VERSION 5.8 ;
BUSBITCHARS "[]" ;
DIVIDERCHAR "/" ;
UNITS
    DATABASE MICRONS 1000 ;
END UNITS

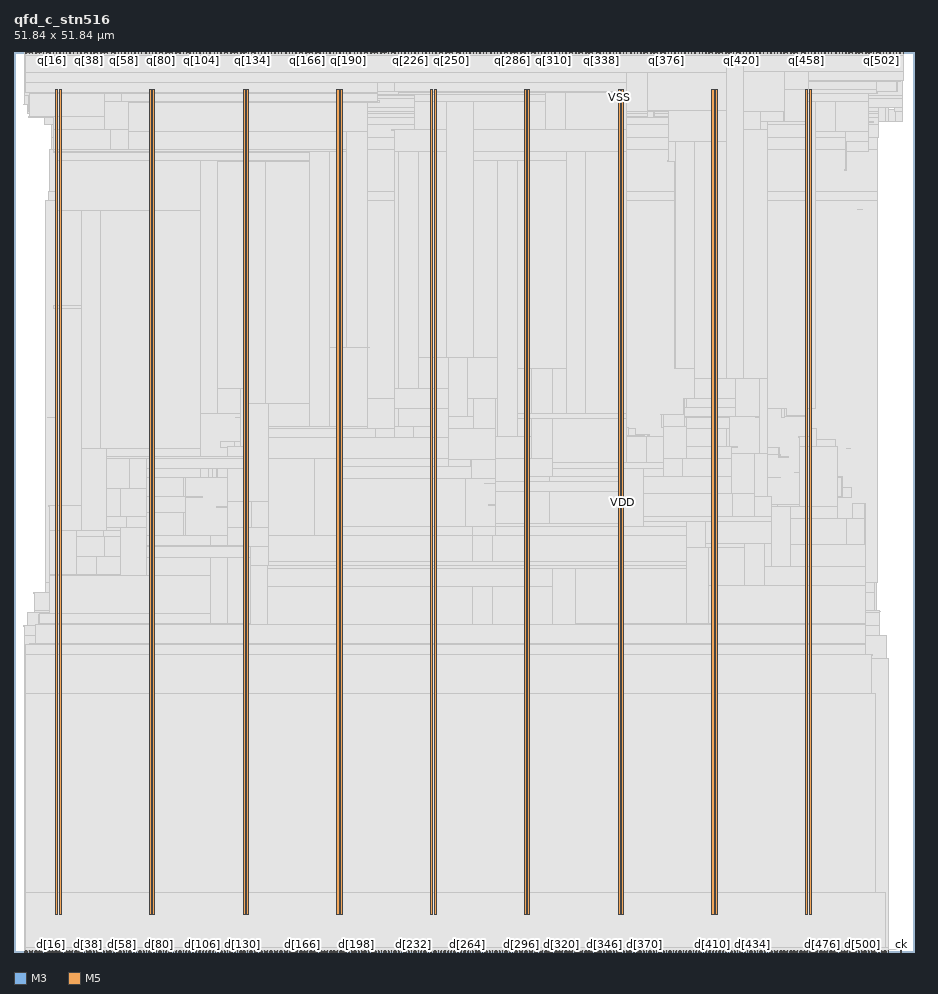
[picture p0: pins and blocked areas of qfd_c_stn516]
MACRO qfd_c_stn516
  FOREIGN qfd_c_stn516 0 0 ;
  CLASS BLOCK ;
  SIZE 51.84 BY 51.84 ;
  PIN ck
    DIRECTION INPUT ;
    USE SIGNAL ;
    PORT
      LAYER M3 ;
        RECT  51.084 0 51.102 0.038 ;
    END
    PORT
      LAYER M3 ;
        RECT  51.084 0.012 51.102 0.173 ;
    END
  END ck
  PIN d[0]
    DIRECTION INPUT ;
    USE SIGNAL ;
    PORT
      LAYER M3 ;
        RECT  0.576 0 0.594 0.038 ;
    END
  END d[0]
  PIN d[100]
    DIRECTION INPUT ;
    USE SIGNAL ;
    PORT
      LAYER M3 ;
        RECT  10.26 0 10.278 0.038 ;
    END
  END d[100]
  PIN d[101]
    DIRECTION INPUT ;
    USE SIGNAL ;
    PORT
      LAYER M5 ;
        RECT  10.32 0 10.344 0.084 ;
    END
  END d[101]
  PIN d[102]
    DIRECTION INPUT ;
    USE SIGNAL ;
    PORT
      LAYER M3 ;
        RECT  10.44 0 10.458 0.038 ;
    END
  END d[102]
  PIN d[103]
    DIRECTION INPUT ;
    USE SIGNAL ;
    PORT
      LAYER M5 ;
        RECT  10.512 0 10.536 0.084 ;
    END
  END d[103]
  PIN d[104]
    DIRECTION INPUT ;
    USE SIGNAL ;
    PORT
      LAYER M3 ;
        RECT  10.62 0 10.638 0.038 ;
    END
  END d[104]
  PIN d[105]
    DIRECTION INPUT ;
    USE SIGNAL ;
    PORT
      LAYER M5 ;
        RECT  10.704 0 10.728 0.084 ;
    END
  END d[105]
  PIN d[106]
    DIRECTION INPUT ;
    USE SIGNAL ;
    PORT
      LAYER M3 ;
        RECT  10.836 0 10.854 0.038 ;
    END
  END d[106]
  PIN d[107]
    DIRECTION INPUT ;
    USE SIGNAL ;
    PORT
      LAYER M5 ;
        RECT  10.896 0 10.92 0.084 ;
    END
  END d[107]
  PIN d[108]
    DIRECTION INPUT ;
    USE SIGNAL ;
    PORT
      LAYER M3 ;
        RECT  11.016 0 11.034 0.038 ;
    END
  END d[108]
  PIN d[109]
    DIRECTION INPUT ;
    USE SIGNAL ;
    PORT
      LAYER M5 ;
        RECT  11.088 0 11.112 0.084 ;
    END
  END d[109]
  PIN d[10]
    DIRECTION INPUT ;
    USE SIGNAL ;
    PORT
      LAYER M3 ;
        RECT  1.548 0 1.566 0.038 ;
    END
  END d[10]
  PIN d[110]
    DIRECTION INPUT ;
    USE SIGNAL ;
    PORT
      LAYER M3 ;
        RECT  11.196 0 11.214 0.038 ;
    END
  END d[110]
  PIN d[111]
    DIRECTION INPUT ;
    USE SIGNAL ;
    PORT
      LAYER M5 ;
        RECT  11.28 0 11.304 0.084 ;
    END
  END d[111]
  PIN d[112]
    DIRECTION INPUT ;
    USE SIGNAL ;
    PORT
      LAYER M3 ;
        RECT  11.412 0 11.43 0.038 ;
    END
  END d[112]
  PIN d[113]
    DIRECTION INPUT ;
    USE SIGNAL ;
    PORT
      LAYER M5 ;
        RECT  11.472 0 11.496 0.084 ;
    END
  END d[113]
  PIN d[114]
    DIRECTION INPUT ;
    USE SIGNAL ;
    PORT
      LAYER M3 ;
        RECT  11.592 0 11.61 0.038 ;
    END
  END d[114]
  PIN d[115]
    DIRECTION INPUT ;
    USE SIGNAL ;
    PORT
      LAYER M5 ;
        RECT  11.712 0 11.736 0.084 ;
    END
  END d[115]
  PIN d[116]
    DIRECTION INPUT ;
    USE SIGNAL ;
    PORT
      LAYER M3 ;
        RECT  11.772 0 11.79 0.038 ;
    END
  END d[116]
  PIN d[117]
    DIRECTION INPUT ;
    USE SIGNAL ;
    PORT
      LAYER M5 ;
        RECT  11.904 0 11.928 0.084 ;
    END
  END d[117]
  PIN d[118]
    DIRECTION INPUT ;
    USE SIGNAL ;
    PORT
      LAYER M3 ;
        RECT  11.988 0 12.006 0.038 ;
    END
  END d[118]
  PIN d[119]
    DIRECTION INPUT ;
    USE SIGNAL ;
    PORT
      LAYER M5 ;
        RECT  12.096 0 12.12 0.084 ;
    END
  END d[119]
  PIN d[11]
    DIRECTION INPUT ;
    USE SIGNAL ;
    PORT
      LAYER M5 ;
        RECT  1.632 0 1.656 0.084 ;
    END
  END d[11]
  PIN d[120]
    DIRECTION INPUT ;
    USE SIGNAL ;
    PORT
      LAYER M3 ;
        RECT  12.168 0 12.186 0.038 ;
    END
  END d[120]
  PIN d[121]
    DIRECTION INPUT ;
    USE SIGNAL ;
    PORT
      LAYER M5 ;
        RECT  12.288 0 12.312 0.084 ;
    END
  END d[121]
  PIN d[122]
    DIRECTION INPUT ;
    USE SIGNAL ;
    PORT
      LAYER M3 ;
        RECT  12.384 0 12.402 0.038 ;
    END
  END d[122]
  PIN d[123]
    DIRECTION INPUT ;
    USE SIGNAL ;
    PORT
      LAYER M5 ;
        RECT  12.48 0 12.504 0.084 ;
    END
  END d[123]
  PIN d[124]
    DIRECTION INPUT ;
    USE SIGNAL ;
    PORT
      LAYER M3 ;
        RECT  12.564 0 12.582 0.038 ;
    END
  END d[124]
  PIN d[125]
    DIRECTION INPUT ;
    USE SIGNAL ;
    PORT
      LAYER M5 ;
        RECT  12.672 0 12.696 0.084 ;
    END
  END d[125]
  PIN d[126]
    DIRECTION INPUT ;
    USE SIGNAL ;
    PORT
      LAYER M3 ;
        RECT  12.744 0 12.762 0.038 ;
    END
  END d[126]
  PIN d[127]
    DIRECTION INPUT ;
    USE SIGNAL ;
    PORT
      LAYER M5 ;
        RECT  12.864 0 12.888 0.084 ;
    END
  END d[127]
  PIN d[128]
    DIRECTION INPUT ;
    USE SIGNAL ;
    PORT
      LAYER M3 ;
        RECT  12.96 0 12.978 0.038 ;
    END
  END d[128]
  PIN d[129]
    DIRECTION INPUT ;
    USE SIGNAL ;
    PORT
      LAYER M5 ;
        RECT  13.056 0 13.08 0.084 ;
    END
  END d[129]
  PIN d[12]
    DIRECTION INPUT ;
    USE SIGNAL ;
    PORT
      LAYER M3 ;
        RECT  1.728 0 1.746 0.038 ;
    END
  END d[12]
  PIN d[130]
    DIRECTION INPUT ;
    USE SIGNAL ;
    PORT
      LAYER M3 ;
        RECT  13.14 0 13.158 0.038 ;
    END
  END d[130]
  PIN d[131]
    DIRECTION INPUT ;
    USE SIGNAL ;
    PORT
      LAYER M5 ;
        RECT  13.248 0 13.272 0.084 ;
    END
  END d[131]
  PIN d[132]
    DIRECTION INPUT ;
    USE SIGNAL ;
    PORT
      LAYER M3 ;
        RECT  13.32 0 13.338 0.038 ;
    END
  END d[132]
  PIN d[133]
    DIRECTION INPUT ;
    USE SIGNAL ;
    PORT
      LAYER M5 ;
        RECT  13.44 0 13.464 0.084 ;
    END
  END d[133]
  PIN d[134]
    DIRECTION INPUT ;
    USE SIGNAL ;
    PORT
      LAYER M3 ;
        RECT  13.536 0 13.554 0.038 ;
    END
  END d[134]
  PIN d[135]
    DIRECTION INPUT ;
    USE SIGNAL ;
    PORT
      LAYER M5 ;
        RECT  13.632 0 13.656 0.084 ;
    END
  END d[135]
  PIN d[136]
    DIRECTION INPUT ;
    USE SIGNAL ;
    PORT
      LAYER M3 ;
        RECT  13.716 0 13.734 0.038 ;
    END
  END d[136]
  PIN d[137]
    DIRECTION INPUT ;
    USE SIGNAL ;
    PORT
      LAYER M5 ;
        RECT  13.824 0 13.848 0.084 ;
    END
  END d[137]
  PIN d[138]
    DIRECTION INPUT ;
    USE SIGNAL ;
    PORT
      LAYER M3 ;
        RECT  13.932 0 13.95 0.038 ;
    END
  END d[138]
  PIN d[139]
    DIRECTION INPUT ;
    USE SIGNAL ;
    PORT
      LAYER M5 ;
        RECT  14.016 0 14.04 0.084 ;
    END
  END d[139]
  PIN d[13]
    DIRECTION INPUT ;
    USE SIGNAL ;
    PORT
      LAYER M5 ;
        RECT  1.824 0 1.848 0.084 ;
    END
  END d[13]
  PIN d[140]
    DIRECTION INPUT ;
    USE SIGNAL ;
    PORT
      LAYER M3 ;
        RECT  14.112 0 14.13 0.038 ;
    END
  END d[140]
  PIN d[141]
    DIRECTION INPUT ;
    USE SIGNAL ;
    PORT
      LAYER M5 ;
        RECT  14.208 0 14.232 0.084 ;
    END
  END d[141]
  PIN d[142]
    DIRECTION INPUT ;
    USE SIGNAL ;
    PORT
      LAYER M3 ;
        RECT  14.292 0 14.31 0.038 ;
    END
  END d[142]
  PIN d[143]
    DIRECTION INPUT ;
    USE SIGNAL ;
    PORT
      LAYER M5 ;
        RECT  14.4 0 14.424 0.084 ;
    END
  END d[143]
  PIN d[144]
    DIRECTION INPUT ;
    USE SIGNAL ;
    PORT
      LAYER M3 ;
        RECT  14.508 0 14.526 0.038 ;
    END
  END d[144]
  PIN d[145]
    DIRECTION INPUT ;
    USE SIGNAL ;
    PORT
      LAYER M5 ;
        RECT  14.592 0 14.616 0.084 ;
    END
  END d[145]
  PIN d[146]
    DIRECTION INPUT ;
    USE SIGNAL ;
    PORT
      LAYER M3 ;
        RECT  14.688 0 14.706 0.038 ;
    END
  END d[146]
  PIN d[147]
    DIRECTION INPUT ;
    USE SIGNAL ;
    PORT
      LAYER M5 ;
        RECT  14.784 0 14.808 0.084 ;
    END
  END d[147]
  PIN d[148]
    DIRECTION INPUT ;
    USE SIGNAL ;
    PORT
      LAYER M3 ;
        RECT  14.868 0 14.886 0.038 ;
    END
  END d[148]
  PIN d[149]
    DIRECTION INPUT ;
    USE SIGNAL ;
    PORT
      LAYER M5 ;
        RECT  14.976 0 15 0.084 ;
    END
  END d[149]
  PIN d[14]
    DIRECTION INPUT ;
    USE SIGNAL ;
    PORT
      LAYER M3 ;
        RECT  1.944 0 1.962 0.038 ;
    END
  END d[14]
  PIN d[150]
    DIRECTION INPUT ;
    USE SIGNAL ;
    PORT
      LAYER M3 ;
        RECT  15.084 0 15.102 0.038 ;
    END
  END d[150]
  PIN d[151]
    DIRECTION INPUT ;
    USE SIGNAL ;
    PORT
      LAYER M5 ;
        RECT  15.168 0 15.192 0.084 ;
    END
  END d[151]
  PIN d[152]
    DIRECTION INPUT ;
    USE SIGNAL ;
    PORT
      LAYER M3 ;
        RECT  15.264 0 15.282 0.038 ;
    END
  END d[152]
  PIN d[153]
    DIRECTION INPUT ;
    USE SIGNAL ;
    PORT
      LAYER M5 ;
        RECT  15.36 0 15.384 0.084 ;
    END
  END d[153]
  PIN d[154]
    DIRECTION INPUT ;
    USE SIGNAL ;
    PORT
      LAYER M3 ;
        RECT  15.444 0 15.462 0.038 ;
    END
  END d[154]
  PIN d[155]
    DIRECTION INPUT ;
    USE SIGNAL ;
    PORT
      LAYER M5 ;
        RECT  15.552 0 15.576 0.084 ;
    END
  END d[155]
  PIN d[156]
    DIRECTION INPUT ;
    USE SIGNAL ;
    PORT
      LAYER M3 ;
        RECT  15.66 0 15.678 0.038 ;
    END
  END d[156]
  PIN d[157]
    DIRECTION INPUT ;
    USE SIGNAL ;
    PORT
      LAYER M5 ;
        RECT  15.744 0 15.768 0.084 ;
    END
  END d[157]
  PIN d[158]
    DIRECTION INPUT ;
    USE SIGNAL ;
    PORT
      LAYER M3 ;
        RECT  15.84 0 15.858 0.038 ;
    END
  END d[158]
  PIN d[159]
    DIRECTION INPUT ;
    USE SIGNAL ;
    PORT
      LAYER M5 ;
        RECT  15.936 0 15.96 0.084 ;
    END
  END d[159]
  PIN d[15]
    DIRECTION INPUT ;
    USE SIGNAL ;
    PORT
      LAYER M5 ;
        RECT  2.016 0 2.04 0.084 ;
    END
  END d[15]
  PIN d[160]
    DIRECTION INPUT ;
    USE SIGNAL ;
    PORT
      LAYER M3 ;
        RECT  16.056 0 16.074 0.038 ;
    END
  END d[160]
  PIN d[161]
    DIRECTION INPUT ;
    USE SIGNAL ;
    PORT
      LAYER M5 ;
        RECT  16.128 0 16.152 0.084 ;
    END
  END d[161]
  PIN d[162]
    DIRECTION INPUT ;
    USE SIGNAL ;
    PORT
      LAYER M3 ;
        RECT  16.236 0 16.254 0.038 ;
    END
  END d[162]
  PIN d[163]
    DIRECTION INPUT ;
    USE SIGNAL ;
    PORT
      LAYER M5 ;
        RECT  16.32 0 16.344 0.084 ;
    END
  END d[163]
  PIN d[164]
    DIRECTION INPUT ;
    USE SIGNAL ;
    PORT
      LAYER M3 ;
        RECT  16.416 0 16.434 0.038 ;
    END
  END d[164]
  PIN d[165]
    DIRECTION INPUT ;
    USE SIGNAL ;
    PORT
      LAYER M5 ;
        RECT  16.512 0 16.536 0.084 ;
    END
  END d[165]
  PIN d[166]
    DIRECTION INPUT ;
    USE SIGNAL ;
    PORT
      LAYER M3 ;
        RECT  16.632 0 16.65 0.038 ;
    END
  END d[166]
  PIN d[167]
    DIRECTION INPUT ;
    USE SIGNAL ;
    PORT
      LAYER M5 ;
        RECT  16.704 0 16.728 0.084 ;
    END
  END d[167]
  PIN d[168]
    DIRECTION INPUT ;
    USE SIGNAL ;
    PORT
      LAYER M3 ;
        RECT  16.812 0 16.83 0.038 ;
    END
  END d[168]
  PIN d[169]
    DIRECTION INPUT ;
    USE SIGNAL ;
    PORT
      LAYER M5 ;
        RECT  16.896 0 16.92 0.084 ;
    END
  END d[169]
  PIN d[16]
    DIRECTION INPUT ;
    USE SIGNAL ;
    PORT
      LAYER M3 ;
        RECT  2.124 0 2.142 0.038 ;
    END
  END d[16]
  PIN d[170]
    DIRECTION INPUT ;
    USE SIGNAL ;
    PORT
      LAYER M3 ;
        RECT  16.992 0 17.01 0.038 ;
    END
  END d[170]
  PIN d[171]
    DIRECTION INPUT ;
    USE SIGNAL ;
    PORT
      LAYER M5 ;
        RECT  17.088 0 17.112 0.084 ;
    END
  END d[171]
  PIN d[172]
    DIRECTION INPUT ;
    USE SIGNAL ;
    PORT
      LAYER M3 ;
        RECT  17.208 0 17.226 0.038 ;
    END
  END d[172]
  PIN d[173]
    DIRECTION INPUT ;
    USE SIGNAL ;
    PORT
      LAYER M5 ;
        RECT  17.28 0 17.304 0.084 ;
    END
  END d[173]
  PIN d[174]
    DIRECTION INPUT ;
    USE SIGNAL ;
    PORT
      LAYER M3 ;
        RECT  17.388 0 17.406 0.038 ;
    END
  END d[174]
  PIN d[175]
    DIRECTION INPUT ;
    USE SIGNAL ;
    PORT
      LAYER M5 ;
        RECT  17.472 0 17.496 0.084 ;
    END
  END d[175]
  PIN d[176]
    DIRECTION INPUT ;
    USE SIGNAL ;
    PORT
      LAYER M3 ;
        RECT  17.604 0 17.622 0.038 ;
    END
  END d[176]
  PIN d[177]
    DIRECTION INPUT ;
    USE SIGNAL ;
    PORT
      LAYER M5 ;
        RECT  17.664 0 17.688 0.084 ;
    END
  END d[177]
  PIN d[178]
    DIRECTION INPUT ;
    USE SIGNAL ;
    PORT
      LAYER M3 ;
        RECT  17.784 0 17.802 0.038 ;
    END
  END d[178]
  PIN d[179]
    DIRECTION INPUT ;
    USE SIGNAL ;
    PORT
      LAYER M5 ;
        RECT  17.856 0 17.88 0.084 ;
    END
  END d[179]
  PIN d[17]
    DIRECTION INPUT ;
    USE SIGNAL ;
    PORT
      LAYER M5 ;
        RECT  2.208 0 2.232 0.084 ;
    END
  END d[17]
  PIN d[180]
    DIRECTION INPUT ;
    USE SIGNAL ;
    PORT
      LAYER M3 ;
        RECT  17.964 0 17.982 0.038 ;
    END
  END d[180]
  PIN d[181]
    DIRECTION INPUT ;
    USE SIGNAL ;
    PORT
      LAYER M5 ;
        RECT  18.048 0 18.072 0.084 ;
    END
  END d[181]
  PIN d[182]
    DIRECTION INPUT ;
    USE SIGNAL ;
    PORT
      LAYER M3 ;
        RECT  18.18 0 18.198 0.038 ;
    END
  END d[182]
  PIN d[183]
    DIRECTION INPUT ;
    USE SIGNAL ;
    PORT
      LAYER M5 ;
        RECT  18.24 0 18.264 0.084 ;
    END
  END d[183]
  PIN d[184]
    DIRECTION INPUT ;
    USE SIGNAL ;
    PORT
      LAYER M3 ;
        RECT  18.36 0 18.378 0.038 ;
    END
  END d[184]
  PIN d[185]
    DIRECTION INPUT ;
    USE SIGNAL ;
    PORT
      LAYER M5 ;
        RECT  18.432 0 18.456 0.084 ;
    END
  END d[185]
  PIN d[186]
    DIRECTION INPUT ;
    USE SIGNAL ;
    PORT
      LAYER M3 ;
        RECT  18.54 0 18.558 0.038 ;
    END
  END d[186]
  PIN d[187]
    DIRECTION INPUT ;
    USE SIGNAL ;
    PORT
      LAYER M5 ;
        RECT  18.624 0 18.648 0.084 ;
    END
  END d[187]
  PIN d[188]
    DIRECTION INPUT ;
    USE SIGNAL ;
    PORT
      LAYER M3 ;
        RECT  18.756 0 18.774 0.038 ;
    END
  END d[188]
  PIN d[189]
    DIRECTION INPUT ;
    USE SIGNAL ;
    PORT
      LAYER M5 ;
        RECT  18.816 0 18.84 0.084 ;
    END
  END d[189]
  PIN d[18]
    DIRECTION INPUT ;
    USE SIGNAL ;
    PORT
      LAYER M3 ;
        RECT  2.304 0 2.322 0.038 ;
    END
  END d[18]
  PIN d[190]
    DIRECTION INPUT ;
    USE SIGNAL ;
    PORT
      LAYER M3 ;
        RECT  18.936 0 18.954 0.038 ;
    END
  END d[190]
  PIN d[191]
    DIRECTION INPUT ;
    USE SIGNAL ;
    PORT
      LAYER M5 ;
        RECT  19.056 0 19.08 0.084 ;
    END
  END d[191]
  PIN d[192]
    DIRECTION INPUT ;
    USE SIGNAL ;
    PORT
      LAYER M3 ;
        RECT  19.116 0 19.134 0.038 ;
    END
  END d[192]
  PIN d[193]
    DIRECTION INPUT ;
    USE SIGNAL ;
    PORT
      LAYER M5 ;
        RECT  19.248 0 19.272 0.084 ;
    END
  END d[193]
  PIN d[194]
    DIRECTION INPUT ;
    USE SIGNAL ;
    PORT
      LAYER M3 ;
        RECT  19.332 0 19.35 0.038 ;
    END
  END d[194]
  PIN d[195]
    DIRECTION INPUT ;
    USE SIGNAL ;
    PORT
      LAYER M5 ;
        RECT  19.44 0 19.464 0.084 ;
    END
  END d[195]
  PIN d[196]
    DIRECTION INPUT ;
    USE SIGNAL ;
    PORT
      LAYER M3 ;
        RECT  19.512 0 19.53 0.038 ;
    END
  END d[196]
  PIN d[197]
    DIRECTION INPUT ;
    USE SIGNAL ;
    PORT
      LAYER M5 ;
        RECT  19.632 0 19.656 0.084 ;
    END
  END d[197]
  PIN d[198]
    DIRECTION INPUT ;
    USE SIGNAL ;
    PORT
      LAYER M3 ;
        RECT  19.728 0 19.746 0.038 ;
    END
  END d[198]
  PIN d[199]
    DIRECTION INPUT ;
    USE SIGNAL ;
    PORT
      LAYER M5 ;
        RECT  19.824 0 19.848 0.084 ;
    END
  END d[199]
  PIN d[19]
    DIRECTION INPUT ;
    USE SIGNAL ;
    PORT
      LAYER M5 ;
        RECT  2.4 0 2.424 0.084 ;
    END
  END d[19]
  PIN d[1]
    DIRECTION INPUT ;
    USE SIGNAL ;
    PORT
      LAYER M5 ;
        RECT  0.672 0 0.696 0.084 ;
    END
  END d[1]
  PIN d[200]
    DIRECTION INPUT ;
    USE SIGNAL ;
    PORT
      LAYER M3 ;
        RECT  19.908 0 19.926 0.038 ;
    END
  END d[200]
  PIN d[201]
    DIRECTION INPUT ;
    USE SIGNAL ;
    PORT
      LAYER M5 ;
        RECT  20.016 0 20.04 0.084 ;
    END
  END d[201]
  PIN d[202]
    DIRECTION INPUT ;
    USE SIGNAL ;
    PORT
      LAYER M3 ;
        RECT  20.088 0 20.106 0.038 ;
    END
  END d[202]
  PIN d[203]
    DIRECTION INPUT ;
    USE SIGNAL ;
    PORT
      LAYER M5 ;
        RECT  20.208 0 20.232 0.084 ;
    END
  END d[203]
  PIN d[204]
    DIRECTION INPUT ;
    USE SIGNAL ;
    PORT
      LAYER M3 ;
        RECT  20.304 0 20.322 0.038 ;
    END
  END d[204]
  PIN d[205]
    DIRECTION INPUT ;
    USE SIGNAL ;
    PORT
      LAYER M5 ;
        RECT  20.4 0 20.424 0.084 ;
    END
  END d[205]
  PIN d[206]
    DIRECTION INPUT ;
    USE SIGNAL ;
    PORT
      LAYER M3 ;
        RECT  20.484 0 20.502 0.038 ;
    END
  END d[206]
  PIN d[207]
    DIRECTION INPUT ;
    USE SIGNAL ;
    PORT
      LAYER M5 ;
        RECT  20.592 0 20.616 0.084 ;
    END
  END d[207]
  PIN d[208]
    DIRECTION INPUT ;
    USE SIGNAL ;
    PORT
      LAYER M3 ;
        RECT  20.664 0 20.682 0.038 ;
    END
  END d[208]
  PIN d[209]
    DIRECTION INPUT ;
    USE SIGNAL ;
    PORT
      LAYER M5 ;
        RECT  20.784 0 20.808 0.084 ;
    END
  END d[209]
  PIN d[20]
    DIRECTION INPUT ;
    USE SIGNAL ;
    PORT
      LAYER M3 ;
        RECT  2.52 0 2.538 0.038 ;
    END
  END d[20]
  PIN d[210]
    DIRECTION INPUT ;
    USE SIGNAL ;
    PORT
      LAYER M3 ;
        RECT  20.88 0 20.898 0.038 ;
    END
  END d[210]
  PIN d[211]
    DIRECTION INPUT ;
    USE SIGNAL ;
    PORT
      LAYER M5 ;
        RECT  20.976 0 21 0.084 ;
    END
  END d[211]
  PIN d[212]
    DIRECTION INPUT ;
    USE SIGNAL ;
    PORT
      LAYER M3 ;
        RECT  21.06 0 21.078 0.038 ;
    END
  END d[212]
  PIN d[213]
    DIRECTION INPUT ;
    USE SIGNAL ;
    PORT
      LAYER M5 ;
        RECT  21.168 0 21.192 0.084 ;
    END
  END d[213]
  PIN d[214]
    DIRECTION INPUT ;
    USE SIGNAL ;
    PORT
      LAYER M3 ;
        RECT  21.276 0 21.294 0.038 ;
    END
  END d[214]
  PIN d[215]
    DIRECTION INPUT ;
    USE SIGNAL ;
    PORT
      LAYER M5 ;
        RECT  21.36 0 21.384 0.084 ;
    END
  END d[215]
  PIN d[216]
    DIRECTION INPUT ;
    USE SIGNAL ;
    PORT
      LAYER M3 ;
        RECT  21.456 0 21.474 0.038 ;
    END
  END d[216]
  PIN d[217]
    DIRECTION INPUT ;
    USE SIGNAL ;
    PORT
      LAYER M5 ;
        RECT  21.552 0 21.576 0.084 ;
    END
  END d[217]
  PIN d[218]
    DIRECTION INPUT ;
    USE SIGNAL ;
    PORT
      LAYER M3 ;
        RECT  21.636 0 21.654 0.038 ;
    END
  END d[218]
  PIN d[219]
    DIRECTION INPUT ;
    USE SIGNAL ;
    PORT
      LAYER M5 ;
        RECT  21.744 0 21.768 0.084 ;
    END
  END d[219]
  PIN d[21]
    DIRECTION INPUT ;
    USE SIGNAL ;
    PORT
      LAYER M5 ;
        RECT  2.592 0 2.616 0.084 ;
    END
  END d[21]
  PIN d[220]
    DIRECTION INPUT ;
    USE SIGNAL ;
    PORT
      LAYER M3 ;
        RECT  21.852 0 21.87 0.038 ;
    END
  END d[220]
  PIN d[221]
    DIRECTION INPUT ;
    USE SIGNAL ;
    PORT
      LAYER M5 ;
        RECT  21.936 0 21.96 0.084 ;
    END
  END d[221]
  PIN d[222]
    DIRECTION INPUT ;
    USE SIGNAL ;
    PORT
      LAYER M3 ;
        RECT  22.032 0 22.05 0.038 ;
    END
  END d[222]
  PIN d[223]
    DIRECTION INPUT ;
    USE SIGNAL ;
    PORT
      LAYER M5 ;
        RECT  22.128 0 22.152 0.084 ;
    END
  END d[223]
  PIN d[224]
    DIRECTION INPUT ;
    USE SIGNAL ;
    PORT
      LAYER M3 ;
        RECT  22.212 0 22.23 0.038 ;
    END
  END d[224]
  PIN d[225]
    DIRECTION INPUT ;
    USE SIGNAL ;
    PORT
      LAYER M5 ;
        RECT  22.32 0 22.344 0.084 ;
    END
  END d[225]
  PIN d[226]
    DIRECTION INPUT ;
    USE SIGNAL ;
    PORT
      LAYER M3 ;
        RECT  22.428 0 22.446 0.038 ;
    END
  END d[226]
  PIN d[227]
    DIRECTION INPUT ;
    USE SIGNAL ;
    PORT
      LAYER M5 ;
        RECT  22.512 0 22.536 0.084 ;
    END
  END d[227]
  PIN d[228]
    DIRECTION INPUT ;
    USE SIGNAL ;
    PORT
      LAYER M3 ;
        RECT  22.608 0 22.626 0.038 ;
    END
  END d[228]
  PIN d[229]
    DIRECTION INPUT ;
    USE SIGNAL ;
    PORT
      LAYER M5 ;
        RECT  22.704 0 22.728 0.084 ;
    END
  END d[229]
  PIN d[22]
    DIRECTION INPUT ;
    USE SIGNAL ;
    PORT
      LAYER M3 ;
        RECT  2.7 0 2.718 0.038 ;
    END
  END d[22]
  PIN d[230]
    DIRECTION INPUT ;
    USE SIGNAL ;
    PORT
      LAYER M3 ;
        RECT  22.788 0 22.806 0.038 ;
    END
  END d[230]
  PIN d[231]
    DIRECTION INPUT ;
    USE SIGNAL ;
    PORT
      LAYER M5 ;
        RECT  22.896 0 22.92 0.084 ;
    END
  END d[231]
  PIN d[232]
    DIRECTION INPUT ;
    USE SIGNAL ;
    PORT
      LAYER M3 ;
        RECT  23.004 0 23.022 0.038 ;
    END
  END d[232]
  PIN d[233]
    DIRECTION INPUT ;
    USE SIGNAL ;
    PORT
      LAYER M5 ;
        RECT  23.088 0 23.112 0.084 ;
    END
  END d[233]
  PIN d[234]
    DIRECTION INPUT ;
    USE SIGNAL ;
    PORT
      LAYER M3 ;
        RECT  23.184 0 23.202 0.038 ;
    END
  END d[234]
  PIN d[235]
    DIRECTION INPUT ;
    USE SIGNAL ;
    PORT
      LAYER M5 ;
        RECT  23.28 0 23.304 0.084 ;
    END
  END d[235]
  PIN d[236]
    DIRECTION INPUT ;
    USE SIGNAL ;
    PORT
      LAYER M3 ;
        RECT  23.4 0 23.418 0.038 ;
    END
  END d[236]
  PIN d[237]
    DIRECTION INPUT ;
    USE SIGNAL ;
    PORT
      LAYER M5 ;
        RECT  23.472 0 23.496 0.084 ;
    END
  END d[237]
  PIN d[238]
    DIRECTION INPUT ;
    USE SIGNAL ;
    PORT
      LAYER M3 ;
        RECT  23.58 0 23.598 0.038 ;
    END
  END d[238]
  PIN d[239]
    DIRECTION INPUT ;
    USE SIGNAL ;
    PORT
      LAYER M5 ;
        RECT  23.664 0 23.688 0.084 ;
    END
  END d[239]
  PIN d[23]
    DIRECTION INPUT ;
    USE SIGNAL ;
    PORT
      LAYER M5 ;
        RECT  2.784 0 2.808 0.084 ;
    END
  END d[23]
  PIN d[240]
    DIRECTION INPUT ;
    USE SIGNAL ;
    PORT
      LAYER M3 ;
        RECT  23.76 0 23.778 0.038 ;
    END
  END d[240]
  PIN d[241]
    DIRECTION INPUT ;
    USE SIGNAL ;
    PORT
      LAYER M5 ;
        RECT  23.856 0 23.88 0.084 ;
    END
  END d[241]
  PIN d[242]
    DIRECTION INPUT ;
    USE SIGNAL ;
    PORT
      LAYER M3 ;
        RECT  23.976 0 23.994 0.038 ;
    END
  END d[242]
  PIN d[243]
    DIRECTION INPUT ;
    USE SIGNAL ;
    PORT
      LAYER M5 ;
        RECT  24.048 0 24.072 0.084 ;
    END
  END d[243]
  PIN d[244]
    DIRECTION INPUT ;
    USE SIGNAL ;
    PORT
      LAYER M3 ;
        RECT  24.156 0 24.174 0.038 ;
    END
  END d[244]
  PIN d[245]
    DIRECTION INPUT ;
    USE SIGNAL ;
    PORT
      LAYER M5 ;
        RECT  24.24 0 24.264 0.084 ;
    END
  END d[245]
  PIN d[246]
    DIRECTION INPUT ;
    USE SIGNAL ;
    PORT
      LAYER M3 ;
        RECT  24.336 0 24.354 0.038 ;
    END
  END d[246]
  PIN d[247]
    DIRECTION INPUT ;
    USE SIGNAL ;
    PORT
      LAYER M5 ;
        RECT  24.432 0 24.456 0.084 ;
    END
  END d[247]
  PIN d[248]
    DIRECTION INPUT ;
    USE SIGNAL ;
    PORT
      LAYER M3 ;
        RECT  24.552 0 24.57 0.038 ;
    END
  END d[248]
  PIN d[249]
    DIRECTION INPUT ;
    USE SIGNAL ;
    PORT
      LAYER M5 ;
        RECT  24.624 0 24.648 0.084 ;
    END
  END d[249]
  PIN d[24]
    DIRECTION INPUT ;
    USE SIGNAL ;
    PORT
      LAYER M3 ;
        RECT  2.916 0 2.934 0.038 ;
    END
  END d[24]
  PIN d[250]
    DIRECTION INPUT ;
    USE SIGNAL ;
    PORT
      LAYER M3 ;
        RECT  24.732 0 24.75 0.038 ;
    END
  END d[250]
  PIN d[251]
    DIRECTION INPUT ;
    USE SIGNAL ;
    PORT
      LAYER M5 ;
        RECT  24.816 0 24.84 0.084 ;
    END
  END d[251]
  PIN d[252]
    DIRECTION INPUT ;
    USE SIGNAL ;
    PORT
      LAYER M3 ;
        RECT  24.948 0 24.966 0.038 ;
    END
  END d[252]
  PIN d[253]
    DIRECTION INPUT ;
    USE SIGNAL ;
    PORT
      LAYER M5 ;
        RECT  25.008 0 25.032 0.084 ;
    END
  END d[253]
  PIN d[254]
    DIRECTION INPUT ;
    USE SIGNAL ;
    PORT
      LAYER M3 ;
        RECT  25.128 0 25.146 0.038 ;
    END
  END d[254]
  PIN d[255]
    DIRECTION INPUT ;
    USE SIGNAL ;
    PORT
      LAYER M5 ;
        RECT  25.2 0 25.224 0.084 ;
    END
  END d[255]
  PIN d[256]
    DIRECTION INPUT ;
    USE SIGNAL ;
    PORT
      LAYER M3 ;
        RECT  25.308 0 25.326 0.038 ;
    END
  END d[256]
  PIN d[257]
    DIRECTION INPUT ;
    USE SIGNAL ;
    PORT
      LAYER M5 ;
        RECT  25.392 0 25.416 0.084 ;
    END
  END d[257]
  PIN d[258]
    DIRECTION INPUT ;
    USE SIGNAL ;
    PORT
      LAYER M3 ;
        RECT  25.524 0 25.542 0.038 ;
    END
  END d[258]
  PIN d[259]
    DIRECTION INPUT ;
    USE SIGNAL ;
    PORT
      LAYER M5 ;
        RECT  25.584 0 25.608 0.084 ;
    END
  END d[259]
  PIN d[25]
    DIRECTION INPUT ;
    USE SIGNAL ;
    PORT
      LAYER M5 ;
        RECT  2.976 0 3 0.084 ;
    END
  END d[25]
  PIN d[260]
    DIRECTION INPUT ;
    USE SIGNAL ;
    PORT
      LAYER M3 ;
        RECT  25.704 0 25.722 0.038 ;
    END
  END d[260]
  PIN d[261]
    DIRECTION INPUT ;
    USE SIGNAL ;
    PORT
      LAYER M5 ;
        RECT  25.776 0 25.8 0.084 ;
    END
  END d[261]
  PIN d[262]
    DIRECTION INPUT ;
    USE SIGNAL ;
    PORT
      LAYER M3 ;
        RECT  25.884 0 25.902 0.038 ;
    END
  END d[262]
  PIN d[263]
    DIRECTION INPUT ;
    USE SIGNAL ;
    PORT
      LAYER M5 ;
        RECT  25.968 0 25.992 0.084 ;
    END
  END d[263]
  PIN d[264]
    DIRECTION INPUT ;
    USE SIGNAL ;
    PORT
      LAYER M3 ;
        RECT  26.1 0 26.118 0.038 ;
    END
  END d[264]
  PIN d[265]
    DIRECTION INPUT ;
    USE SIGNAL ;
    PORT
      LAYER M5 ;
        RECT  26.16 0 26.184 0.084 ;
    END
  END d[265]
  PIN d[266]
    DIRECTION INPUT ;
    USE SIGNAL ;
    PORT
      LAYER M3 ;
        RECT  26.28 0 26.298 0.038 ;
    END
  END d[266]
  PIN d[267]
    DIRECTION INPUT ;
    USE SIGNAL ;
    PORT
      LAYER M5 ;
        RECT  26.4 0 26.424 0.084 ;
    END
  END d[267]
  PIN d[268]
    DIRECTION INPUT ;
    USE SIGNAL ;
    PORT
      LAYER M3 ;
        RECT  26.46 0 26.478 0.038 ;
    END
  END d[268]
  PIN d[269]
    DIRECTION INPUT ;
    USE SIGNAL ;
    PORT
      LAYER M5 ;
        RECT  26.592 0 26.616 0.084 ;
    END
  END d[269]
  PIN d[26]
    DIRECTION INPUT ;
    USE SIGNAL ;
    PORT
      LAYER M3 ;
        RECT  3.096 0 3.114 0.038 ;
    END
  END d[26]
  PIN d[270]
    DIRECTION INPUT ;
    USE SIGNAL ;
    PORT
      LAYER M3 ;
        RECT  26.676 0 26.694 0.038 ;
    END
  END d[270]
  PIN d[271]
    DIRECTION INPUT ;
    USE SIGNAL ;
    PORT
      LAYER M5 ;
        RECT  26.784 0 26.808 0.084 ;
    END
  END d[271]
  PIN d[272]
    DIRECTION INPUT ;
    USE SIGNAL ;
    PORT
      LAYER M3 ;
        RECT  26.856 0 26.874 0.038 ;
    END
  END d[272]
  PIN d[273]
    DIRECTION INPUT ;
    USE SIGNAL ;
    PORT
      LAYER M5 ;
        RECT  26.976 0 27 0.084 ;
    END
  END d[273]
  PIN d[274]
    DIRECTION INPUT ;
    USE SIGNAL ;
    PORT
      LAYER M3 ;
        RECT  27.072 0 27.09 0.038 ;
    END
  END d[274]
  PIN d[275]
    DIRECTION INPUT ;
    USE SIGNAL ;
    PORT
      LAYER M5 ;
        RECT  27.168 0 27.192 0.084 ;
    END
  END d[275]
  PIN d[276]
    DIRECTION INPUT ;
    USE SIGNAL ;
    PORT
      LAYER M3 ;
        RECT  27.252 0 27.27 0.038 ;
    END
  END d[276]
  PIN d[277]
    DIRECTION INPUT ;
    USE SIGNAL ;
    PORT
      LAYER M5 ;
        RECT  27.36 0 27.384 0.084 ;
    END
  END d[277]
  PIN d[278]
    DIRECTION INPUT ;
    USE SIGNAL ;
    PORT
      LAYER M3 ;
        RECT  27.432 0 27.45 0.038 ;
    END
  END d[278]
  PIN d[279]
    DIRECTION INPUT ;
    USE SIGNAL ;
    PORT
      LAYER M5 ;
        RECT  27.552 0 27.576 0.084 ;
    END
  END d[279]
  PIN d[27]
    DIRECTION INPUT ;
    USE SIGNAL ;
    PORT
      LAYER M5 ;
        RECT  3.168 0 3.192 0.084 ;
    END
  END d[27]
  PIN d[280]
    DIRECTION INPUT ;
    USE SIGNAL ;
    PORT
      LAYER M3 ;
        RECT  27.648 0 27.666 0.038 ;
    END
  END d[280]
  PIN d[281]
    DIRECTION INPUT ;
    USE SIGNAL ;
    PORT
      LAYER M5 ;
        RECT  27.744 0 27.768 0.084 ;
    END
  END d[281]
  PIN d[282]
    DIRECTION INPUT ;
    USE SIGNAL ;
    PORT
      LAYER M3 ;
        RECT  27.828 0 27.846 0.038 ;
    END
  END d[282]
  PIN d[283]
    DIRECTION INPUT ;
    USE SIGNAL ;
    PORT
      LAYER M5 ;
        RECT  27.936 0 27.96 0.084 ;
    END
  END d[283]
  PIN d[284]
    DIRECTION INPUT ;
    USE SIGNAL ;
    PORT
      LAYER M3 ;
        RECT  28.008 0 28.026 0.038 ;
    END
  END d[284]
  PIN d[285]
    DIRECTION INPUT ;
    USE SIGNAL ;
    PORT
      LAYER M5 ;
        RECT  28.128 0 28.152 0.084 ;
    END
  END d[285]
  PIN d[286]
    DIRECTION INPUT ;
    USE SIGNAL ;
    PORT
      LAYER M3 ;
        RECT  28.224 0 28.242 0.038 ;
    END
  END d[286]
  PIN d[287]
    DIRECTION INPUT ;
    USE SIGNAL ;
    PORT
      LAYER M5 ;
        RECT  28.32 0 28.344 0.084 ;
    END
  END d[287]
  PIN d[288]
    DIRECTION INPUT ;
    USE SIGNAL ;
    PORT
      LAYER M3 ;
        RECT  28.404 0 28.422 0.038 ;
    END
  END d[288]
  PIN d[289]
    DIRECTION INPUT ;
    USE SIGNAL ;
    PORT
      LAYER M5 ;
        RECT  28.512 0 28.536 0.084 ;
    END
  END d[289]
  PIN d[28]
    DIRECTION INPUT ;
    USE SIGNAL ;
    PORT
      LAYER M3 ;
        RECT  3.276 0 3.294 0.038 ;
    END
  END d[28]
  PIN d[290]
    DIRECTION INPUT ;
    USE SIGNAL ;
    PORT
      LAYER M3 ;
        RECT  28.584 0 28.602 0.038 ;
    END
  END d[290]
  PIN d[291]
    DIRECTION INPUT ;
    USE SIGNAL ;
    PORT
      LAYER M5 ;
        RECT  28.704 0 28.728 0.084 ;
    END
  END d[291]
  PIN d[292]
    DIRECTION INPUT ;
    USE SIGNAL ;
    PORT
      LAYER M3 ;
        RECT  28.8 0 28.818 0.038 ;
    END
  END d[292]
  PIN d[293]
    DIRECTION INPUT ;
    USE SIGNAL ;
    PORT
      LAYER M5 ;
        RECT  28.896 0 28.92 0.084 ;
    END
  END d[293]
  PIN d[294]
    DIRECTION INPUT ;
    USE SIGNAL ;
    PORT
      LAYER M3 ;
        RECT  28.98 0 28.998 0.038 ;
    END
  END d[294]
  PIN d[295]
    DIRECTION INPUT ;
    USE SIGNAL ;
    PORT
      LAYER M5 ;
        RECT  29.088 0 29.112 0.084 ;
    END
  END d[295]
  PIN d[296]
    DIRECTION INPUT ;
    USE SIGNAL ;
    PORT
      LAYER M3 ;
        RECT  29.196 0 29.214 0.038 ;
    END
  END d[296]
  PIN d[297]
    DIRECTION INPUT ;
    USE SIGNAL ;
    PORT
      LAYER M5 ;
        RECT  29.28 0 29.304 0.084 ;
    END
  END d[297]
  PIN d[298]
    DIRECTION INPUT ;
    USE SIGNAL ;
    PORT
      LAYER M3 ;
        RECT  29.376 0 29.394 0.038 ;
    END
  END d[298]
  PIN d[299]
    DIRECTION INPUT ;
    USE SIGNAL ;
    PORT
      LAYER M5 ;
        RECT  29.472 0 29.496 0.084 ;
    END
  END d[299]
  PIN d[29]
    DIRECTION INPUT ;
    USE SIGNAL ;
    PORT
      LAYER M5 ;
        RECT  3.36 0 3.384 0.084 ;
    END
  END d[29]
  PIN d[2]
    DIRECTION INPUT ;
    USE SIGNAL ;
    PORT
      LAYER M3 ;
        RECT  0.756 0 0.774 0.038 ;
    END
  END d[2]
  PIN d[300]
    DIRECTION INPUT ;
    USE SIGNAL ;
    PORT
      LAYER M3 ;
        RECT  29.556 0 29.574 0.038 ;
    END
  END d[300]
  PIN d[301]
    DIRECTION INPUT ;
    USE SIGNAL ;
    PORT
      LAYER M5 ;
        RECT  29.664 0 29.688 0.084 ;
    END
  END d[301]
  PIN d[302]
    DIRECTION INPUT ;
    USE SIGNAL ;
    PORT
      LAYER M3 ;
        RECT  29.772 0 29.79 0.038 ;
    END
  END d[302]
  PIN d[303]
    DIRECTION INPUT ;
    USE SIGNAL ;
    PORT
      LAYER M5 ;
        RECT  29.856 0 29.88 0.084 ;
    END
  END d[303]
  PIN d[304]
    DIRECTION INPUT ;
    USE SIGNAL ;
    PORT
      LAYER M3 ;
        RECT  29.952 0 29.97 0.038 ;
    END
  END d[304]
  PIN d[305]
    DIRECTION INPUT ;
    USE SIGNAL ;
    PORT
      LAYER M5 ;
        RECT  30.048 0 30.072 0.084 ;
    END
  END d[305]
  PIN d[306]
    DIRECTION INPUT ;
    USE SIGNAL ;
    PORT
      LAYER M3 ;
        RECT  30.132 0 30.15 0.038 ;
    END
  END d[306]
  PIN d[307]
    DIRECTION INPUT ;
    USE SIGNAL ;
    PORT
      LAYER M5 ;
        RECT  30.24 0 30.264 0.084 ;
    END
  END d[307]
  PIN d[308]
    DIRECTION INPUT ;
    USE SIGNAL ;
    PORT
      LAYER M3 ;
        RECT  30.348 0 30.366 0.038 ;
    END
  END d[308]
  PIN d[309]
    DIRECTION INPUT ;
    USE SIGNAL ;
    PORT
      LAYER M5 ;
        RECT  30.432 0 30.456 0.084 ;
    END
  END d[309]
  PIN d[30]
    DIRECTION INPUT ;
    USE SIGNAL ;
    PORT
      LAYER M3 ;
        RECT  3.492 0 3.51 0.038 ;
    END
  END d[30]
  PIN d[310]
    DIRECTION INPUT ;
    USE SIGNAL ;
    PORT
      LAYER M3 ;
        RECT  30.528 0 30.546 0.038 ;
    END
  END d[310]
  PIN d[311]
    DIRECTION INPUT ;
    USE SIGNAL ;
    PORT
      LAYER M5 ;
        RECT  30.624 0 30.648 0.084 ;
    END
  END d[311]
  PIN d[312]
    DIRECTION INPUT ;
    USE SIGNAL ;
    PORT
      LAYER M3 ;
        RECT  30.744 0 30.762 0.038 ;
    END
  END d[312]
  PIN d[313]
    DIRECTION INPUT ;
    USE SIGNAL ;
    PORT
      LAYER M5 ;
        RECT  30.816 0 30.84 0.084 ;
    END
  END d[313]
  PIN d[314]
    DIRECTION INPUT ;
    USE SIGNAL ;
    PORT
      LAYER M3 ;
        RECT  30.924 0 30.942 0.038 ;
    END
  END d[314]
  PIN d[315]
    DIRECTION INPUT ;
    USE SIGNAL ;
    PORT
      LAYER M5 ;
        RECT  31.008 0 31.032 0.084 ;
    END
  END d[315]
  PIN d[316]
    DIRECTION INPUT ;
    USE SIGNAL ;
    PORT
      LAYER M3 ;
        RECT  31.104 0 31.122 0.038 ;
    END
  END d[316]
  PIN d[317]
    DIRECTION INPUT ;
    USE SIGNAL ;
    PORT
      LAYER M5 ;
        RECT  31.2 0 31.224 0.084 ;
    END
  END d[317]
  PIN d[318]
    DIRECTION INPUT ;
    USE SIGNAL ;
    PORT
      LAYER M3 ;
        RECT  31.32 0 31.338 0.038 ;
    END
  END d[318]
  PIN d[319]
    DIRECTION INPUT ;
    USE SIGNAL ;
    PORT
      LAYER M5 ;
        RECT  31.392 0 31.416 0.084 ;
    END
  END d[319]
  PIN d[31]
    DIRECTION INPUT ;
    USE SIGNAL ;
    PORT
      LAYER M5 ;
        RECT  3.552 0 3.576 0.084 ;
    END
  END d[31]
  PIN d[320]
    DIRECTION INPUT ;
    USE SIGNAL ;
    PORT
      LAYER M3 ;
        RECT  31.5 0 31.518 0.038 ;
    END
  END d[320]
  PIN d[321]
    DIRECTION INPUT ;
    USE SIGNAL ;
    PORT
      LAYER M5 ;
        RECT  31.584 0 31.608 0.084 ;
    END
  END d[321]
  PIN d[322]
    DIRECTION INPUT ;
    USE SIGNAL ;
    PORT
      LAYER M3 ;
        RECT  31.68 0 31.698 0.038 ;
    END
  END d[322]
  PIN d[323]
    DIRECTION INPUT ;
    USE SIGNAL ;
    PORT
      LAYER M5 ;
        RECT  31.776 0 31.8 0.084 ;
    END
  END d[323]
  PIN d[324]
    DIRECTION INPUT ;
    USE SIGNAL ;
    PORT
      LAYER M3 ;
        RECT  31.896 0 31.914 0.038 ;
    END
  END d[324]
  PIN d[325]
    DIRECTION INPUT ;
    USE SIGNAL ;
    PORT
      LAYER M5 ;
        RECT  31.968 0 31.992 0.084 ;
    END
  END d[325]
  PIN d[326]
    DIRECTION INPUT ;
    USE SIGNAL ;
    PORT
      LAYER M3 ;
        RECT  32.076 0 32.094 0.038 ;
    END
  END d[326]
  PIN d[327]
    DIRECTION INPUT ;
    USE SIGNAL ;
    PORT
      LAYER M5 ;
        RECT  32.16 0 32.184 0.084 ;
    END
  END d[327]
  PIN d[328]
    DIRECTION INPUT ;
    USE SIGNAL ;
    PORT
      LAYER M3 ;
        RECT  32.256 0 32.274 0.038 ;
    END
  END d[328]
  PIN d[329]
    DIRECTION INPUT ;
    USE SIGNAL ;
    PORT
      LAYER M5 ;
        RECT  32.352 0 32.376 0.084 ;
    END
  END d[329]
  PIN d[32]
    DIRECTION INPUT ;
    USE SIGNAL ;
    PORT
      LAYER M3 ;
        RECT  3.672 0 3.69 0.038 ;
    END
  END d[32]
  PIN d[330]
    DIRECTION INPUT ;
    USE SIGNAL ;
    PORT
      LAYER M3 ;
        RECT  32.472 0 32.49 0.038 ;
    END
  END d[330]
  PIN d[331]
    DIRECTION INPUT ;
    USE SIGNAL ;
    PORT
      LAYER M5 ;
        RECT  32.544 0 32.568 0.084 ;
    END
  END d[331]
  PIN d[332]
    DIRECTION INPUT ;
    USE SIGNAL ;
    PORT
      LAYER M3 ;
        RECT  32.652 0 32.67 0.038 ;
    END
  END d[332]
  PIN d[333]
    DIRECTION INPUT ;
    USE SIGNAL ;
    PORT
      LAYER M5 ;
        RECT  32.736 0 32.76 0.084 ;
    END
  END d[333]
  PIN d[334]
    DIRECTION INPUT ;
    USE SIGNAL ;
    PORT
      LAYER M3 ;
        RECT  32.868 0 32.886 0.038 ;
    END
  END d[334]
  PIN d[335]
    DIRECTION INPUT ;
    USE SIGNAL ;
    PORT
      LAYER M5 ;
        RECT  32.928 0 32.952 0.084 ;
    END
  END d[335]
  PIN d[336]
    DIRECTION INPUT ;
    USE SIGNAL ;
    PORT
      LAYER M3 ;
        RECT  33.048 0 33.066 0.038 ;
    END
  END d[336]
  PIN d[337]
    DIRECTION INPUT ;
    USE SIGNAL ;
    PORT
      LAYER M5 ;
        RECT  33.12 0 33.144 0.084 ;
    END
  END d[337]
  PIN d[338]
    DIRECTION INPUT ;
    USE SIGNAL ;
    PORT
      LAYER M3 ;
        RECT  33.228 0 33.246 0.038 ;
    END
  END d[338]
  PIN d[339]
    DIRECTION INPUT ;
    USE SIGNAL ;
    PORT
      LAYER M5 ;
        RECT  33.312 0 33.336 0.084 ;
    END
  END d[339]
  PIN d[33]
    DIRECTION INPUT ;
    USE SIGNAL ;
    PORT
      LAYER M5 ;
        RECT  3.744 0 3.768 0.084 ;
    END
  END d[33]
  PIN d[340]
    DIRECTION INPUT ;
    USE SIGNAL ;
    PORT
      LAYER M3 ;
        RECT  33.444 0 33.462 0.038 ;
    END
  END d[340]
  PIN d[341]
    DIRECTION INPUT ;
    USE SIGNAL ;
    PORT
      LAYER M5 ;
        RECT  33.504 0 33.528 0.084 ;
    END
  END d[341]
  PIN d[342]
    DIRECTION INPUT ;
    USE SIGNAL ;
    PORT
      LAYER M3 ;
        RECT  33.624 0 33.642 0.038 ;
    END
  END d[342]
  PIN d[343]
    DIRECTION INPUT ;
    USE SIGNAL ;
    PORT
      LAYER M5 ;
        RECT  33.744 0 33.768 0.084 ;
    END
  END d[343]
  PIN d[344]
    DIRECTION INPUT ;
    USE SIGNAL ;
    PORT
      LAYER M3 ;
        RECT  33.804 0 33.822 0.038 ;
    END
  END d[344]
  PIN d[345]
    DIRECTION INPUT ;
    USE SIGNAL ;
    PORT
      LAYER M5 ;
        RECT  33.936 0 33.96 0.084 ;
    END
  END d[345]
  PIN d[346]
    DIRECTION INPUT ;
    USE SIGNAL ;
    PORT
      LAYER M3 ;
        RECT  34.02 0 34.038 0.038 ;
    END
  END d[346]
  PIN d[347]
    DIRECTION INPUT ;
    USE SIGNAL ;
    PORT
      LAYER M5 ;
        RECT  34.128 0 34.152 0.084 ;
    END
  END d[347]
  PIN d[348]
    DIRECTION INPUT ;
    USE SIGNAL ;
    PORT
      LAYER M3 ;
        RECT  34.2 0 34.218 0.038 ;
    END
  END d[348]
  PIN d[349]
    DIRECTION INPUT ;
    USE SIGNAL ;
    PORT
      LAYER M5 ;
        RECT  34.32 0 34.344 0.084 ;
    END
  END d[349]
  PIN d[34]
    DIRECTION INPUT ;
    USE SIGNAL ;
    PORT
      LAYER M3 ;
        RECT  3.852 0 3.87 0.038 ;
    END
  END d[34]
  PIN d[350]
    DIRECTION INPUT ;
    USE SIGNAL ;
    PORT
      LAYER M3 ;
        RECT  34.416 0 34.434 0.038 ;
    END
  END d[350]
  PIN d[351]
    DIRECTION INPUT ;
    USE SIGNAL ;
    PORT
      LAYER M5 ;
        RECT  34.512 0 34.536 0.084 ;
    END
  END d[351]
  PIN d[352]
    DIRECTION INPUT ;
    USE SIGNAL ;
    PORT
      LAYER M3 ;
        RECT  34.596 0 34.614 0.038 ;
    END
  END d[352]
  PIN d[353]
    DIRECTION INPUT ;
    USE SIGNAL ;
    PORT
      LAYER M5 ;
        RECT  34.704 0 34.728 0.084 ;
    END
  END d[353]
  PIN d[354]
    DIRECTION INPUT ;
    USE SIGNAL ;
    PORT
      LAYER M3 ;
        RECT  34.776 0 34.794 0.038 ;
    END
  END d[354]
  PIN d[355]
    DIRECTION INPUT ;
    USE SIGNAL ;
    PORT
      LAYER M5 ;
        RECT  34.896 0 34.92 0.084 ;
    END
  END d[355]
  PIN d[356]
    DIRECTION INPUT ;
    USE SIGNAL ;
    PORT
      LAYER M3 ;
        RECT  34.992 0 35.01 0.038 ;
    END
  END d[356]
  PIN d[357]
    DIRECTION INPUT ;
    USE SIGNAL ;
    PORT
      LAYER M5 ;
        RECT  35.088 0 35.112 0.084 ;
    END
  END d[357]
  PIN d[358]
    DIRECTION INPUT ;
    USE SIGNAL ;
    PORT
      LAYER M3 ;
        RECT  35.172 0 35.19 0.038 ;
    END
  END d[358]
  PIN d[359]
    DIRECTION INPUT ;
    USE SIGNAL ;
    PORT
      LAYER M5 ;
        RECT  35.28 0 35.304 0.084 ;
    END
  END d[359]
  PIN d[35]
    DIRECTION INPUT ;
    USE SIGNAL ;
    PORT
      LAYER M5 ;
        RECT  3.936 0 3.96 0.084 ;
    END
  END d[35]
  PIN d[360]
    DIRECTION INPUT ;
    USE SIGNAL ;
    PORT
      LAYER M3 ;
        RECT  35.352 0 35.37 0.038 ;
    END
  END d[360]
  PIN d[361]
    DIRECTION INPUT ;
    USE SIGNAL ;
    PORT
      LAYER M5 ;
        RECT  35.472 0 35.496 0.084 ;
    END
  END d[361]
  PIN d[362]
    DIRECTION INPUT ;
    USE SIGNAL ;
    PORT
      LAYER M3 ;
        RECT  35.568 0 35.586 0.038 ;
    END
  END d[362]
  PIN d[363]
    DIRECTION INPUT ;
    USE SIGNAL ;
    PORT
      LAYER M5 ;
        RECT  35.664 0 35.688 0.084 ;
    END
  END d[363]
  PIN d[364]
    DIRECTION INPUT ;
    USE SIGNAL ;
    PORT
      LAYER M3 ;
        RECT  35.748 0 35.766 0.038 ;
    END
  END d[364]
  PIN d[365]
    DIRECTION INPUT ;
    USE SIGNAL ;
    PORT
      LAYER M5 ;
        RECT  35.856 0 35.88 0.084 ;
    END
  END d[365]
  PIN d[366]
    DIRECTION INPUT ;
    USE SIGNAL ;
    PORT
      LAYER M3 ;
        RECT  35.928 0 35.946 0.038 ;
    END
  END d[366]
  PIN d[367]
    DIRECTION INPUT ;
    USE SIGNAL ;
    PORT
      LAYER M5 ;
        RECT  36.048 0 36.072 0.084 ;
    END
  END d[367]
  PIN d[368]
    DIRECTION INPUT ;
    USE SIGNAL ;
    PORT
      LAYER M3 ;
        RECT  36.144 0 36.162 0.038 ;
    END
  END d[368]
  PIN d[369]
    DIRECTION INPUT ;
    USE SIGNAL ;
    PORT
      LAYER M5 ;
        RECT  36.24 0 36.264 0.084 ;
    END
  END d[369]
  PIN d[36]
    DIRECTION INPUT ;
    USE SIGNAL ;
    PORT
      LAYER M3 ;
        RECT  4.068 0 4.086 0.038 ;
    END
  END d[36]
  PIN d[370]
    DIRECTION INPUT ;
    USE SIGNAL ;
    PORT
      LAYER M3 ;
        RECT  36.324 0 36.342 0.038 ;
    END
  END d[370]
  PIN d[371]
    DIRECTION INPUT ;
    USE SIGNAL ;
    PORT
      LAYER M5 ;
        RECT  36.432 0 36.456 0.084 ;
    END
  END d[371]
  PIN d[372]
    DIRECTION INPUT ;
    USE SIGNAL ;
    PORT
      LAYER M3 ;
        RECT  36.54 0 36.558 0.038 ;
    END
  END d[372]
  PIN d[373]
    DIRECTION INPUT ;
    USE SIGNAL ;
    PORT
      LAYER M5 ;
        RECT  36.624 0 36.648 0.084 ;
    END
  END d[373]
  PIN d[374]
    DIRECTION INPUT ;
    USE SIGNAL ;
    PORT
      LAYER M3 ;
        RECT  36.72 0 36.738 0.038 ;
    END
  END d[374]
  PIN d[375]
    DIRECTION INPUT ;
    USE SIGNAL ;
    PORT
      LAYER M5 ;
        RECT  36.816 0 36.84 0.084 ;
    END
  END d[375]
  PIN d[376]
    DIRECTION INPUT ;
    USE SIGNAL ;
    PORT
      LAYER M3 ;
        RECT  36.9 0 36.918 0.038 ;
    END
  END d[376]
  PIN d[377]
    DIRECTION INPUT ;
    USE SIGNAL ;
    PORT
      LAYER M5 ;
        RECT  37.008 0 37.032 0.084 ;
    END
  END d[377]
  PIN d[378]
    DIRECTION INPUT ;
    USE SIGNAL ;
    PORT
      LAYER M3 ;
        RECT  37.116 0 37.134 0.038 ;
    END
  END d[378]
  PIN d[379]
    DIRECTION INPUT ;
    USE SIGNAL ;
    PORT
      LAYER M5 ;
        RECT  37.2 0 37.224 0.084 ;
    END
  END d[379]
  PIN d[37]
    DIRECTION INPUT ;
    USE SIGNAL ;
    PORT
      LAYER M5 ;
        RECT  4.176 0 4.2 0.084 ;
    END
  END d[37]
  PIN d[380]
    DIRECTION INPUT ;
    USE SIGNAL ;
    PORT
      LAYER M3 ;
        RECT  37.296 0 37.314 0.038 ;
    END
  END d[380]
  PIN d[381]
    DIRECTION INPUT ;
    USE SIGNAL ;
    PORT
      LAYER M5 ;
        RECT  37.392 0 37.416 0.084 ;
    END
  END d[381]
  PIN d[382]
    DIRECTION INPUT ;
    USE SIGNAL ;
    PORT
      LAYER M3 ;
        RECT  37.476 0 37.494 0.038 ;
    END
  END d[382]
  PIN d[383]
    DIRECTION INPUT ;
    USE SIGNAL ;
    PORT
      LAYER M5 ;
        RECT  37.584 0 37.608 0.084 ;
    END
  END d[383]
  PIN d[384]
    DIRECTION INPUT ;
    USE SIGNAL ;
    PORT
      LAYER M3 ;
        RECT  37.692 0 37.71 0.038 ;
    END
  END d[384]
  PIN d[385]
    DIRECTION INPUT ;
    USE SIGNAL ;
    PORT
      LAYER M5 ;
        RECT  37.776 0 37.8 0.084 ;
    END
  END d[385]
  PIN d[386]
    DIRECTION INPUT ;
    USE SIGNAL ;
    PORT
      LAYER M3 ;
        RECT  37.872 0 37.89 0.038 ;
    END
  END d[386]
  PIN d[387]
    DIRECTION INPUT ;
    USE SIGNAL ;
    PORT
      LAYER M5 ;
        RECT  37.968 0 37.992 0.084 ;
    END
  END d[387]
  PIN d[388]
    DIRECTION INPUT ;
    USE SIGNAL ;
    PORT
      LAYER M3 ;
        RECT  38.088 0 38.106 0.038 ;
    END
  END d[388]
  PIN d[389]
    DIRECTION INPUT ;
    USE SIGNAL ;
    PORT
      LAYER M5 ;
        RECT  38.16 0 38.184 0.084 ;
    END
  END d[389]
  PIN d[38]
    DIRECTION INPUT ;
    USE SIGNAL ;
    PORT
      LAYER M3 ;
        RECT  4.248 0 4.266 0.038 ;
    END
  END d[38]
  PIN d[390]
    DIRECTION INPUT ;
    USE SIGNAL ;
    PORT
      LAYER M3 ;
        RECT  38.268 0 38.286 0.038 ;
    END
  END d[390]
  PIN d[391]
    DIRECTION INPUT ;
    USE SIGNAL ;
    PORT
      LAYER M5 ;
        RECT  38.352 0 38.376 0.084 ;
    END
  END d[391]
  PIN d[392]
    DIRECTION INPUT ;
    USE SIGNAL ;
    PORT
      LAYER M3 ;
        RECT  38.448 0 38.466 0.038 ;
    END
  END d[392]
  PIN d[393]
    DIRECTION INPUT ;
    USE SIGNAL ;
    PORT
      LAYER M5 ;
        RECT  38.544 0 38.568 0.084 ;
    END
  END d[393]
  PIN d[394]
    DIRECTION INPUT ;
    USE SIGNAL ;
    PORT
      LAYER M3 ;
        RECT  38.664 0 38.682 0.038 ;
    END
  END d[394]
  PIN d[395]
    DIRECTION INPUT ;
    USE SIGNAL ;
    PORT
      LAYER M5 ;
        RECT  38.736 0 38.76 0.084 ;
    END
  END d[395]
  PIN d[396]
    DIRECTION INPUT ;
    USE SIGNAL ;
    PORT
      LAYER M3 ;
        RECT  38.844 0 38.862 0.038 ;
    END
  END d[396]
  PIN d[397]
    DIRECTION INPUT ;
    USE SIGNAL ;
    PORT
      LAYER M5 ;
        RECT  38.928 0 38.952 0.084 ;
    END
  END d[397]
  PIN d[398]
    DIRECTION INPUT ;
    USE SIGNAL ;
    PORT
      LAYER M3 ;
        RECT  39.024 0 39.042 0.038 ;
    END
  END d[398]
  PIN d[399]
    DIRECTION INPUT ;
    USE SIGNAL ;
    PORT
      LAYER M5 ;
        RECT  39.12 0 39.144 0.084 ;
    END
  END d[399]
  PIN d[39]
    DIRECTION INPUT ;
    USE SIGNAL ;
    PORT
      LAYER M5 ;
        RECT  4.368 0 4.392 0.084 ;
    END
  END d[39]
  PIN d[3]
    DIRECTION INPUT ;
    USE SIGNAL ;
    PORT
      LAYER M5 ;
        RECT  0.864 0 0.888 0.084 ;
    END
  END d[3]
  PIN d[400]
    DIRECTION INPUT ;
    USE SIGNAL ;
    PORT
      LAYER M3 ;
        RECT  39.24 0 39.258 0.038 ;
    END
  END d[400]
  PIN d[401]
    DIRECTION INPUT ;
    USE SIGNAL ;
    PORT
      LAYER M5 ;
        RECT  39.312 0 39.336 0.084 ;
    END
  END d[401]
  PIN d[402]
    DIRECTION INPUT ;
    USE SIGNAL ;
    PORT
      LAYER M3 ;
        RECT  39.42 0 39.438 0.038 ;
    END
  END d[402]
  PIN d[403]
    DIRECTION INPUT ;
    USE SIGNAL ;
    PORT
      LAYER M5 ;
        RECT  39.504 0 39.528 0.084 ;
    END
  END d[403]
  PIN d[404]
    DIRECTION INPUT ;
    USE SIGNAL ;
    PORT
      LAYER M3 ;
        RECT  39.6 0 39.618 0.038 ;
    END
  END d[404]
  PIN d[405]
    DIRECTION INPUT ;
    USE SIGNAL ;
    PORT
      LAYER M5 ;
        RECT  39.696 0 39.72 0.084 ;
    END
  END d[405]
  PIN d[406]
    DIRECTION INPUT ;
    USE SIGNAL ;
    PORT
      LAYER M3 ;
        RECT  39.816 0 39.834 0.038 ;
    END
  END d[406]
  PIN d[407]
    DIRECTION INPUT ;
    USE SIGNAL ;
    PORT
      LAYER M5 ;
        RECT  39.888 0 39.912 0.084 ;
    END
  END d[407]
  PIN d[408]
    DIRECTION INPUT ;
    USE SIGNAL ;
    PORT
      LAYER M3 ;
        RECT  39.996 0 40.014 0.038 ;
    END
  END d[408]
  PIN d[409]
    DIRECTION INPUT ;
    USE SIGNAL ;
    PORT
      LAYER M5 ;
        RECT  40.08 0 40.104 0.084 ;
    END
  END d[409]
  PIN d[40]
    DIRECTION INPUT ;
    USE SIGNAL ;
    PORT
      LAYER M3 ;
        RECT  4.428 0 4.446 0.038 ;
    END
  END d[40]
  PIN d[410]
    DIRECTION INPUT ;
    USE SIGNAL ;
    PORT
      LAYER M3 ;
        RECT  40.212 0 40.23 0.038 ;
    END
  END d[410]
  PIN d[411]
    DIRECTION INPUT ;
    USE SIGNAL ;
    PORT
      LAYER M5 ;
        RECT  40.272 0 40.296 0.084 ;
    END
  END d[411]
  PIN d[412]
    DIRECTION INPUT ;
    USE SIGNAL ;
    PORT
      LAYER M3 ;
        RECT  40.392 0 40.41 0.038 ;
    END
  END d[412]
  PIN d[413]
    DIRECTION INPUT ;
    USE SIGNAL ;
    PORT
      LAYER M5 ;
        RECT  40.464 0 40.488 0.084 ;
    END
  END d[413]
  PIN d[414]
    DIRECTION INPUT ;
    USE SIGNAL ;
    PORT
      LAYER M3 ;
        RECT  40.572 0 40.59 0.038 ;
    END
  END d[414]
  PIN d[415]
    DIRECTION INPUT ;
    USE SIGNAL ;
    PORT
      LAYER M5 ;
        RECT  40.656 0 40.68 0.084 ;
    END
  END d[415]
  PIN d[416]
    DIRECTION INPUT ;
    USE SIGNAL ;
    PORT
      LAYER M3 ;
        RECT  40.788 0 40.806 0.038 ;
    END
  END d[416]
  PIN d[417]
    DIRECTION INPUT ;
    USE SIGNAL ;
    PORT
      LAYER M5 ;
        RECT  40.848 0 40.872 0.084 ;
    END
  END d[417]
  PIN d[418]
    DIRECTION INPUT ;
    USE SIGNAL ;
    PORT
      LAYER M3 ;
        RECT  40.968 0 40.986 0.038 ;
    END
  END d[418]
  PIN d[419]
    DIRECTION INPUT ;
    USE SIGNAL ;
    PORT
      LAYER M5 ;
        RECT  41.04 0 41.064 0.084 ;
    END
  END d[419]
  PIN d[41]
    DIRECTION INPUT ;
    USE SIGNAL ;
    PORT
      LAYER M5 ;
        RECT  4.56 0 4.584 0.084 ;
    END
  END d[41]
  PIN d[420]
    DIRECTION INPUT ;
    USE SIGNAL ;
    PORT
      LAYER M3 ;
        RECT  41.148 0 41.166 0.038 ;
    END
  END d[420]
  PIN d[421]
    DIRECTION INPUT ;
    USE SIGNAL ;
    PORT
      LAYER M5 ;
        RECT  41.28 0 41.304 0.084 ;
    END
  END d[421]
  PIN d[422]
    DIRECTION INPUT ;
    USE SIGNAL ;
    PORT
      LAYER M3 ;
        RECT  41.364 0 41.382 0.038 ;
    END
  END d[422]
  PIN d[423]
    DIRECTION INPUT ;
    USE SIGNAL ;
    PORT
      LAYER M5 ;
        RECT  41.472 0 41.496 0.084 ;
    END
  END d[423]
  PIN d[424]
    DIRECTION INPUT ;
    USE SIGNAL ;
    PORT
      LAYER M3 ;
        RECT  41.544 0 41.562 0.038 ;
    END
  END d[424]
  PIN d[425]
    DIRECTION INPUT ;
    USE SIGNAL ;
    PORT
      LAYER M5 ;
        RECT  41.664 0 41.688 0.084 ;
    END
  END d[425]
  PIN d[426]
    DIRECTION INPUT ;
    USE SIGNAL ;
    PORT
      LAYER M3 ;
        RECT  41.76 0 41.778 0.038 ;
    END
  END d[426]
  PIN d[427]
    DIRECTION INPUT ;
    USE SIGNAL ;
    PORT
      LAYER M5 ;
        RECT  41.856 0 41.88 0.084 ;
    END
  END d[427]
  PIN d[428]
    DIRECTION INPUT ;
    USE SIGNAL ;
    PORT
      LAYER M3 ;
        RECT  41.94 0 41.958 0.038 ;
    END
  END d[428]
  PIN d[429]
    DIRECTION INPUT ;
    USE SIGNAL ;
    PORT
      LAYER M5 ;
        RECT  42.048 0 42.072 0.084 ;
    END
  END d[429]
  PIN d[42]
    DIRECTION INPUT ;
    USE SIGNAL ;
    PORT
      LAYER M3 ;
        RECT  4.644 0 4.662 0.038 ;
    END
  END d[42]
  PIN d[430]
    DIRECTION INPUT ;
    USE SIGNAL ;
    PORT
      LAYER M3 ;
        RECT  42.12 0 42.138 0.038 ;
    END
  END d[430]
  PIN d[431]
    DIRECTION INPUT ;
    USE SIGNAL ;
    PORT
      LAYER M5 ;
        RECT  42.24 0 42.264 0.084 ;
    END
  END d[431]
  PIN d[432]
    DIRECTION INPUT ;
    USE SIGNAL ;
    PORT
      LAYER M3 ;
        RECT  42.336 0 42.354 0.038 ;
    END
  END d[432]
  PIN d[433]
    DIRECTION INPUT ;
    USE SIGNAL ;
    PORT
      LAYER M5 ;
        RECT  42.432 0 42.456 0.084 ;
    END
  END d[433]
  PIN d[434]
    DIRECTION INPUT ;
    USE SIGNAL ;
    PORT
      LAYER M3 ;
        RECT  42.516 0 42.534 0.038 ;
    END
  END d[434]
  PIN d[435]
    DIRECTION INPUT ;
    USE SIGNAL ;
    PORT
      LAYER M5 ;
        RECT  42.624 0 42.648 0.084 ;
    END
  END d[435]
  PIN d[436]
    DIRECTION INPUT ;
    USE SIGNAL ;
    PORT
      LAYER M3 ;
        RECT  42.696 0 42.714 0.038 ;
    END
  END d[436]
  PIN d[437]
    DIRECTION INPUT ;
    USE SIGNAL ;
    PORT
      LAYER M5 ;
        RECT  42.816 0 42.84 0.084 ;
    END
  END d[437]
  PIN d[438]
    DIRECTION INPUT ;
    USE SIGNAL ;
    PORT
      LAYER M3 ;
        RECT  42.912 0 42.93 0.038 ;
    END
  END d[438]
  PIN d[439]
    DIRECTION INPUT ;
    USE SIGNAL ;
    PORT
      LAYER M5 ;
        RECT  43.008 0 43.032 0.084 ;
    END
  END d[439]
  PIN d[43]
    DIRECTION INPUT ;
    USE SIGNAL ;
    PORT
      LAYER M5 ;
        RECT  4.752 0 4.776 0.084 ;
    END
  END d[43]
  PIN d[440]
    DIRECTION INPUT ;
    USE SIGNAL ;
    PORT
      LAYER M3 ;
        RECT  43.092 0 43.11 0.038 ;
    END
  END d[440]
  PIN d[441]
    DIRECTION INPUT ;
    USE SIGNAL ;
    PORT
      LAYER M5 ;
        RECT  43.2 0 43.224 0.084 ;
    END
  END d[441]
  PIN d[442]
    DIRECTION INPUT ;
    USE SIGNAL ;
    PORT
      LAYER M3 ;
        RECT  43.272 0 43.29 0.038 ;
    END
  END d[442]
  PIN d[443]
    DIRECTION INPUT ;
    USE SIGNAL ;
    PORT
      LAYER M5 ;
        RECT  43.392 0 43.416 0.084 ;
    END
  END d[443]
  PIN d[444]
    DIRECTION INPUT ;
    USE SIGNAL ;
    PORT
      LAYER M3 ;
        RECT  43.488 0 43.506 0.038 ;
    END
  END d[444]
  PIN d[445]
    DIRECTION INPUT ;
    USE SIGNAL ;
    PORT
      LAYER M5 ;
        RECT  43.584 0 43.608 0.084 ;
    END
  END d[445]
  PIN d[446]
    DIRECTION INPUT ;
    USE SIGNAL ;
    PORT
      LAYER M3 ;
        RECT  43.668 0 43.686 0.038 ;
    END
  END d[446]
  PIN d[447]
    DIRECTION INPUT ;
    USE SIGNAL ;
    PORT
      LAYER M5 ;
        RECT  43.776 0 43.8 0.084 ;
    END
  END d[447]
  PIN d[448]
    DIRECTION INPUT ;
    USE SIGNAL ;
    PORT
      LAYER M3 ;
        RECT  43.884 0 43.902 0.038 ;
    END
  END d[448]
  PIN d[449]
    DIRECTION INPUT ;
    USE SIGNAL ;
    PORT
      LAYER M5 ;
        RECT  43.968 0 43.992 0.084 ;
    END
  END d[449]
  PIN d[44]
    DIRECTION INPUT ;
    USE SIGNAL ;
    PORT
      LAYER M3 ;
        RECT  4.824 0 4.842 0.038 ;
    END
  END d[44]
  PIN d[450]
    DIRECTION INPUT ;
    USE SIGNAL ;
    PORT
      LAYER M3 ;
        RECT  44.064 0 44.082 0.038 ;
    END
  END d[450]
  PIN d[451]
    DIRECTION INPUT ;
    USE SIGNAL ;
    PORT
      LAYER M5 ;
        RECT  44.16 0 44.184 0.084 ;
    END
  END d[451]
  PIN d[452]
    DIRECTION INPUT ;
    USE SIGNAL ;
    PORT
      LAYER M3 ;
        RECT  44.244 0 44.262 0.038 ;
    END
  END d[452]
  PIN d[453]
    DIRECTION INPUT ;
    USE SIGNAL ;
    PORT
      LAYER M5 ;
        RECT  44.352 0 44.376 0.084 ;
    END
  END d[453]
  PIN d[454]
    DIRECTION INPUT ;
    USE SIGNAL ;
    PORT
      LAYER M3 ;
        RECT  44.46 0 44.478 0.038 ;
    END
  END d[454]
  PIN d[455]
    DIRECTION INPUT ;
    USE SIGNAL ;
    PORT
      LAYER M5 ;
        RECT  44.544 0 44.568 0.084 ;
    END
  END d[455]
  PIN d[456]
    DIRECTION INPUT ;
    USE SIGNAL ;
    PORT
      LAYER M3 ;
        RECT  44.64 0 44.658 0.038 ;
    END
  END d[456]
  PIN d[457]
    DIRECTION INPUT ;
    USE SIGNAL ;
    PORT
      LAYER M5 ;
        RECT  44.736 0 44.76 0.084 ;
    END
  END d[457]
  PIN d[458]
    DIRECTION INPUT ;
    USE SIGNAL ;
    PORT
      LAYER M3 ;
        RECT  44.82 0 44.838 0.038 ;
    END
  END d[458]
  PIN d[459]
    DIRECTION INPUT ;
    USE SIGNAL ;
    PORT
      LAYER M5 ;
        RECT  44.928 0 44.952 0.084 ;
    END
  END d[459]
  PIN d[45]
    DIRECTION INPUT ;
    USE SIGNAL ;
    PORT
      LAYER M5 ;
        RECT  4.944 0 4.968 0.084 ;
    END
  END d[45]
  PIN d[460]
    DIRECTION INPUT ;
    USE SIGNAL ;
    PORT
      LAYER M3 ;
        RECT  45.036 0 45.054 0.038 ;
    END
  END d[460]
  PIN d[461]
    DIRECTION INPUT ;
    USE SIGNAL ;
    PORT
      LAYER M5 ;
        RECT  45.12 0 45.144 0.084 ;
    END
  END d[461]
  PIN d[462]
    DIRECTION INPUT ;
    USE SIGNAL ;
    PORT
      LAYER M3 ;
        RECT  45.216 0 45.234 0.038 ;
    END
  END d[462]
  PIN d[463]
    DIRECTION INPUT ;
    USE SIGNAL ;
    PORT
      LAYER M5 ;
        RECT  45.312 0 45.336 0.084 ;
    END
  END d[463]
  PIN d[464]
    DIRECTION INPUT ;
    USE SIGNAL ;
    PORT
      LAYER M3 ;
        RECT  45.432 0 45.45 0.038 ;
    END
  END d[464]
  PIN d[465]
    DIRECTION INPUT ;
    USE SIGNAL ;
    PORT
      LAYER M5 ;
        RECT  45.504 0 45.528 0.084 ;
    END
  END d[465]
  PIN d[466]
    DIRECTION INPUT ;
    USE SIGNAL ;
    PORT
      LAYER M3 ;
        RECT  45.612 0 45.63 0.038 ;
    END
  END d[466]
  PIN d[467]
    DIRECTION INPUT ;
    USE SIGNAL ;
    PORT
      LAYER M5 ;
        RECT  45.696 0 45.72 0.084 ;
    END
  END d[467]
  PIN d[468]
    DIRECTION INPUT ;
    USE SIGNAL ;
    PORT
      LAYER M3 ;
        RECT  45.792 0 45.81 0.038 ;
    END
  END d[468]
  PIN d[469]
    DIRECTION INPUT ;
    USE SIGNAL ;
    PORT
      LAYER M5 ;
        RECT  45.888 0 45.912 0.084 ;
    END
  END d[469]
  PIN d[46]
    DIRECTION INPUT ;
    USE SIGNAL ;
    PORT
      LAYER M3 ;
        RECT  5.04 0 5.058 0.038 ;
    END
  END d[46]
  PIN d[470]
    DIRECTION INPUT ;
    USE SIGNAL ;
    PORT
      LAYER M3 ;
        RECT  46.008 0 46.026 0.038 ;
    END
  END d[470]
  PIN d[471]
    DIRECTION INPUT ;
    USE SIGNAL ;
    PORT
      LAYER M5 ;
        RECT  46.08 0 46.104 0.084 ;
    END
  END d[471]
  PIN d[472]
    DIRECTION INPUT ;
    USE SIGNAL ;
    PORT
      LAYER M3 ;
        RECT  46.188 0 46.206 0.038 ;
    END
  END d[472]
  PIN d[473]
    DIRECTION INPUT ;
    USE SIGNAL ;
    PORT
      LAYER M5 ;
        RECT  46.272 0 46.296 0.084 ;
    END
  END d[473]
  PIN d[474]
    DIRECTION INPUT ;
    USE SIGNAL ;
    PORT
      LAYER M3 ;
        RECT  46.368 0 46.386 0.038 ;
    END
  END d[474]
  PIN d[475]
    DIRECTION INPUT ;
    USE SIGNAL ;
    PORT
      LAYER M5 ;
        RECT  46.464 0 46.488 0.084 ;
    END
  END d[475]
  PIN d[476]
    DIRECTION INPUT ;
    USE SIGNAL ;
    PORT
      LAYER M3 ;
        RECT  46.584 0 46.602 0.038 ;
    END
  END d[476]
  PIN d[477]
    DIRECTION INPUT ;
    USE SIGNAL ;
    PORT
      LAYER M5 ;
        RECT  46.656 0 46.68 0.084 ;
    END
  END d[477]
  PIN d[478]
    DIRECTION INPUT ;
    USE SIGNAL ;
    PORT
      LAYER M3 ;
        RECT  46.764 0 46.782 0.038 ;
    END
  END d[478]
  PIN d[479]
    DIRECTION INPUT ;
    USE SIGNAL ;
    PORT
      LAYER M5 ;
        RECT  46.848 0 46.872 0.084 ;
    END
  END d[479]
  PIN d[47]
    DIRECTION INPUT ;
    USE SIGNAL ;
    PORT
      LAYER M5 ;
        RECT  5.136 0 5.16 0.084 ;
    END
  END d[47]
  PIN d[480]
    DIRECTION INPUT ;
    USE SIGNAL ;
    PORT
      LAYER M3 ;
        RECT  46.944 0 46.962 0.038 ;
    END
  END d[480]
  PIN d[481]
    DIRECTION INPUT ;
    USE SIGNAL ;
    PORT
      LAYER M5 ;
        RECT  47.04 0 47.064 0.084 ;
    END
  END d[481]
  PIN d[482]
    DIRECTION INPUT ;
    USE SIGNAL ;
    PORT
      LAYER M3 ;
        RECT  47.16 0 47.178 0.038 ;
    END
  END d[482]
  PIN d[483]
    DIRECTION INPUT ;
    USE SIGNAL ;
    PORT
      LAYER M5 ;
        RECT  47.232 0 47.256 0.084 ;
    END
  END d[483]
  PIN d[484]
    DIRECTION INPUT ;
    USE SIGNAL ;
    PORT
      LAYER M3 ;
        RECT  47.34 0 47.358 0.038 ;
    END
  END d[484]
  PIN d[485]
    DIRECTION INPUT ;
    USE SIGNAL ;
    PORT
      LAYER M5 ;
        RECT  47.424 0 47.448 0.084 ;
    END
  END d[485]
  PIN d[486]
    DIRECTION INPUT ;
    USE SIGNAL ;
    PORT
      LAYER M3 ;
        RECT  47.556 0 47.574 0.038 ;
    END
  END d[486]
  PIN d[487]
    DIRECTION INPUT ;
    USE SIGNAL ;
    PORT
      LAYER M5 ;
        RECT  47.616 0 47.64 0.084 ;
    END
  END d[487]
  PIN d[488]
    DIRECTION INPUT ;
    USE SIGNAL ;
    PORT
      LAYER M3 ;
        RECT  47.736 0 47.754 0.038 ;
    END
  END d[488]
  PIN d[489]
    DIRECTION INPUT ;
    USE SIGNAL ;
    PORT
      LAYER M5 ;
        RECT  47.808 0 47.832 0.084 ;
    END
  END d[489]
  PIN d[48]
    DIRECTION INPUT ;
    USE SIGNAL ;
    PORT
      LAYER M3 ;
        RECT  5.22 0 5.238 0.038 ;
    END
  END d[48]
  PIN d[490]
    DIRECTION INPUT ;
    USE SIGNAL ;
    PORT
      LAYER M3 ;
        RECT  47.916 0 47.934 0.038 ;
    END
  END d[490]
  PIN d[491]
    DIRECTION INPUT ;
    USE SIGNAL ;
    PORT
      LAYER M5 ;
        RECT  48 0 48.024 0.084 ;
    END
  END d[491]
  PIN d[492]
    DIRECTION INPUT ;
    USE SIGNAL ;
    PORT
      LAYER M3 ;
        RECT  48.132 0 48.15 0.038 ;
    END
  END d[492]
  PIN d[493]
    DIRECTION INPUT ;
    USE SIGNAL ;
    PORT
      LAYER M5 ;
        RECT  48.192 0 48.216 0.084 ;
    END
  END d[493]
  PIN d[494]
    DIRECTION INPUT ;
    USE SIGNAL ;
    PORT
      LAYER M3 ;
        RECT  48.312 0 48.33 0.038 ;
    END
  END d[494]
  PIN d[495]
    DIRECTION INPUT ;
    USE SIGNAL ;
    PORT
      LAYER M5 ;
        RECT  48.384 0 48.408 0.084 ;
    END
  END d[495]
  PIN d[496]
    DIRECTION INPUT ;
    USE SIGNAL ;
    PORT
      LAYER M3 ;
        RECT  48.492 0 48.51 0.038 ;
    END
  END d[496]
  PIN d[497]
    DIRECTION INPUT ;
    USE SIGNAL ;
    PORT
      LAYER M5 ;
        RECT  48.624 0 48.648 0.084 ;
    END
  END d[497]
  PIN d[498]
    DIRECTION INPUT ;
    USE SIGNAL ;
    PORT
      LAYER M3 ;
        RECT  48.708 0 48.726 0.038 ;
    END
  END d[498]
  PIN d[499]
    DIRECTION INPUT ;
    USE SIGNAL ;
    PORT
      LAYER M5 ;
        RECT  48.816 0 48.84 0.084 ;
    END
  END d[499]
  PIN d[49]
    DIRECTION INPUT ;
    USE SIGNAL ;
    PORT
      LAYER M5 ;
        RECT  5.328 0 5.352 0.084 ;
    END
  END d[49]
  PIN d[4]
    DIRECTION INPUT ;
    USE SIGNAL ;
    PORT
      LAYER M3 ;
        RECT  0.972 0 0.99 0.038 ;
    END
  END d[4]
  PIN d[500]
    DIRECTION INPUT ;
    USE SIGNAL ;
    PORT
      LAYER M3 ;
        RECT  48.888 0 48.906 0.038 ;
    END
  END d[500]
  PIN d[501]
    DIRECTION INPUT ;
    USE SIGNAL ;
    PORT
      LAYER M5 ;
        RECT  49.008 0 49.032 0.084 ;
    END
  END d[501]
  PIN d[502]
    DIRECTION INPUT ;
    USE SIGNAL ;
    PORT
      LAYER M3 ;
        RECT  49.104 0 49.122 0.038 ;
    END
  END d[502]
  PIN d[503]
    DIRECTION INPUT ;
    USE SIGNAL ;
    PORT
      LAYER M5 ;
        RECT  49.2 0 49.224 0.084 ;
    END
  END d[503]
  PIN d[504]
    DIRECTION INPUT ;
    USE SIGNAL ;
    PORT
      LAYER M3 ;
        RECT  49.284 0 49.302 0.038 ;
    END
  END d[504]
  PIN d[505]
    DIRECTION INPUT ;
    USE SIGNAL ;
    PORT
      LAYER M5 ;
        RECT  49.392 0 49.416 0.084 ;
    END
  END d[505]
  PIN d[506]
    DIRECTION INPUT ;
    USE SIGNAL ;
    PORT
      LAYER M3 ;
        RECT  49.464 0 49.482 0.038 ;
    END
  END d[506]
  PIN d[507]
    DIRECTION INPUT ;
    USE SIGNAL ;
    PORT
      LAYER M5 ;
        RECT  49.584 0 49.608 0.084 ;
    END
  END d[507]
  PIN d[508]
    DIRECTION INPUT ;
    USE SIGNAL ;
    PORT
      LAYER M3 ;
        RECT  49.68 0 49.698 0.038 ;
    END
  END d[508]
  PIN d[509]
    DIRECTION INPUT ;
    USE SIGNAL ;
    PORT
      LAYER M5 ;
        RECT  49.776 0 49.8 0.084 ;
    END
  END d[509]
  PIN d[50]
    DIRECTION INPUT ;
    USE SIGNAL ;
    PORT
      LAYER M3 ;
        RECT  5.4 0 5.418 0.038 ;
    END
  END d[50]
  PIN d[510]
    DIRECTION INPUT ;
    USE SIGNAL ;
    PORT
      LAYER M3 ;
        RECT  49.86 0 49.878 0.038 ;
    END
  END d[510]
  PIN d[511]
    DIRECTION INPUT ;
    USE SIGNAL ;
    PORT
      LAYER M5 ;
        RECT  49.968 0 49.992 0.084 ;
    END
  END d[511]
  PIN d[512]
    DIRECTION INPUT ;
    USE SIGNAL ;
    PORT
      LAYER M3 ;
        RECT  50.04 0 50.058 0.038 ;
    END
  END d[512]
  PIN d[513]
    DIRECTION INPUT ;
    USE SIGNAL ;
    PORT
      LAYER M5 ;
        RECT  50.16 0 50.184 0.084 ;
    END
  END d[513]
  PIN d[514]
    DIRECTION INPUT ;
    USE SIGNAL ;
    PORT
      LAYER M3 ;
        RECT  50.256 0 50.274 0.038 ;
    END
  END d[514]
  PIN d[515]
    DIRECTION INPUT ;
    USE SIGNAL ;
    PORT
      LAYER M5 ;
        RECT  50.352 0 50.376 0.084 ;
    END
  END d[515]
  PIN d[51]
    DIRECTION INPUT ;
    USE SIGNAL ;
    PORT
      LAYER M5 ;
        RECT  5.52 0 5.544 0.084 ;
    END
  END d[51]
  PIN d[52]
    DIRECTION INPUT ;
    USE SIGNAL ;
    PORT
      LAYER M3 ;
        RECT  5.616 0 5.634 0.038 ;
    END
  END d[52]
  PIN d[53]
    DIRECTION INPUT ;
    USE SIGNAL ;
    PORT
      LAYER M5 ;
        RECT  5.712 0 5.736 0.084 ;
    END
  END d[53]
  PIN d[54]
    DIRECTION INPUT ;
    USE SIGNAL ;
    PORT
      LAYER M3 ;
        RECT  5.796 0 5.814 0.038 ;
    END
  END d[54]
  PIN d[55]
    DIRECTION INPUT ;
    USE SIGNAL ;
    PORT
      LAYER M5 ;
        RECT  5.904 0 5.928 0.084 ;
    END
  END d[55]
  PIN d[56]
    DIRECTION INPUT ;
    USE SIGNAL ;
    PORT
      LAYER M3 ;
        RECT  5.976 0 5.994 0.038 ;
    END
  END d[56]
  PIN d[57]
    DIRECTION INPUT ;
    USE SIGNAL ;
    PORT
      LAYER M5 ;
        RECT  6.096 0 6.12 0.084 ;
    END
  END d[57]
  PIN d[58]
    DIRECTION INPUT ;
    USE SIGNAL ;
    PORT
      LAYER M3 ;
        RECT  6.192 0 6.21 0.038 ;
    END
  END d[58]
  PIN d[59]
    DIRECTION INPUT ;
    USE SIGNAL ;
    PORT
      LAYER M5 ;
        RECT  6.288 0 6.312 0.084 ;
    END
  END d[59]
  PIN d[5]
    DIRECTION INPUT ;
    USE SIGNAL ;
    PORT
      LAYER M5 ;
        RECT  1.056 0 1.08 0.084 ;
    END
  END d[5]
  PIN d[60]
    DIRECTION INPUT ;
    USE SIGNAL ;
    PORT
      LAYER M3 ;
        RECT  6.372 0 6.39 0.038 ;
    END
  END d[60]
  PIN d[61]
    DIRECTION INPUT ;
    USE SIGNAL ;
    PORT
      LAYER M5 ;
        RECT  6.48 0 6.504 0.084 ;
    END
  END d[61]
  PIN d[62]
    DIRECTION INPUT ;
    USE SIGNAL ;
    PORT
      LAYER M3 ;
        RECT  6.588 0 6.606 0.038 ;
    END
  END d[62]
  PIN d[63]
    DIRECTION INPUT ;
    USE SIGNAL ;
    PORT
      LAYER M5 ;
        RECT  6.672 0 6.696 0.084 ;
    END
  END d[63]
  PIN d[64]
    DIRECTION INPUT ;
    USE SIGNAL ;
    PORT
      LAYER M3 ;
        RECT  6.768 0 6.786 0.038 ;
    END
  END d[64]
  PIN d[65]
    DIRECTION INPUT ;
    USE SIGNAL ;
    PORT
      LAYER M5 ;
        RECT  6.864 0 6.888 0.084 ;
    END
  END d[65]
  PIN d[66]
    DIRECTION INPUT ;
    USE SIGNAL ;
    PORT
      LAYER M3 ;
        RECT  6.948 0 6.966 0.038 ;
    END
  END d[66]
  PIN d[67]
    DIRECTION INPUT ;
    USE SIGNAL ;
    PORT
      LAYER M5 ;
        RECT  7.056 0 7.08 0.084 ;
    END
  END d[67]
  PIN d[68]
    DIRECTION INPUT ;
    USE SIGNAL ;
    PORT
      LAYER M3 ;
        RECT  7.164 0 7.182 0.038 ;
    END
  END d[68]
  PIN d[69]
    DIRECTION INPUT ;
    USE SIGNAL ;
    PORT
      LAYER M5 ;
        RECT  7.248 0 7.272 0.084 ;
    END
  END d[69]
  PIN d[6]
    DIRECTION INPUT ;
    USE SIGNAL ;
    PORT
      LAYER M3 ;
        RECT  1.152 0 1.17 0.038 ;
    END
  END d[6]
  PIN d[70]
    DIRECTION INPUT ;
    USE SIGNAL ;
    PORT
      LAYER M3 ;
        RECT  7.344 0 7.362 0.038 ;
    END
  END d[70]
  PIN d[71]
    DIRECTION INPUT ;
    USE SIGNAL ;
    PORT
      LAYER M5 ;
        RECT  7.44 0 7.464 0.084 ;
    END
  END d[71]
  PIN d[72]
    DIRECTION INPUT ;
    USE SIGNAL ;
    PORT
      LAYER M3 ;
        RECT  7.524 0 7.542 0.038 ;
    END
  END d[72]
  PIN d[73]
    DIRECTION INPUT ;
    USE SIGNAL ;
    PORT
      LAYER M5 ;
        RECT  7.632 0 7.656 0.084 ;
    END
  END d[73]
  PIN d[74]
    DIRECTION INPUT ;
    USE SIGNAL ;
    PORT
      LAYER M3 ;
        RECT  7.74 0 7.758 0.038 ;
    END
  END d[74]
  PIN d[75]
    DIRECTION INPUT ;
    USE SIGNAL ;
    PORT
      LAYER M5 ;
        RECT  7.824 0 7.848 0.084 ;
    END
  END d[75]
  PIN d[76]
    DIRECTION INPUT ;
    USE SIGNAL ;
    PORT
      LAYER M3 ;
        RECT  7.92 0 7.938 0.038 ;
    END
  END d[76]
  PIN d[77]
    DIRECTION INPUT ;
    USE SIGNAL ;
    PORT
      LAYER M5 ;
        RECT  8.016 0 8.04 0.084 ;
    END
  END d[77]
  PIN d[78]
    DIRECTION INPUT ;
    USE SIGNAL ;
    PORT
      LAYER M3 ;
        RECT  8.1 0 8.118 0.038 ;
    END
  END d[78]
  PIN d[79]
    DIRECTION INPUT ;
    USE SIGNAL ;
    PORT
      LAYER M5 ;
        RECT  8.208 0 8.232 0.084 ;
    END
  END d[79]
  PIN d[7]
    DIRECTION INPUT ;
    USE SIGNAL ;
    PORT
      LAYER M5 ;
        RECT  1.248 0 1.272 0.084 ;
    END
  END d[7]
  PIN d[80]
    DIRECTION INPUT ;
    USE SIGNAL ;
    PORT
      LAYER M3 ;
        RECT  8.316 0 8.334 0.038 ;
    END
  END d[80]
  PIN d[81]
    DIRECTION INPUT ;
    USE SIGNAL ;
    PORT
      LAYER M5 ;
        RECT  8.4 0 8.424 0.084 ;
    END
  END d[81]
  PIN d[82]
    DIRECTION INPUT ;
    USE SIGNAL ;
    PORT
      LAYER M3 ;
        RECT  8.496 0 8.514 0.038 ;
    END
  END d[82]
  PIN d[83]
    DIRECTION INPUT ;
    USE SIGNAL ;
    PORT
      LAYER M5 ;
        RECT  8.592 0 8.616 0.084 ;
    END
  END d[83]
  PIN d[84]
    DIRECTION INPUT ;
    USE SIGNAL ;
    PORT
      LAYER M3 ;
        RECT  8.712 0 8.73 0.038 ;
    END
  END d[84]
  PIN d[85]
    DIRECTION INPUT ;
    USE SIGNAL ;
    PORT
      LAYER M5 ;
        RECT  8.784 0 8.808 0.084 ;
    END
  END d[85]
  PIN d[86]
    DIRECTION INPUT ;
    USE SIGNAL ;
    PORT
      LAYER M3 ;
        RECT  8.892 0 8.91 0.038 ;
    END
  END d[86]
  PIN d[87]
    DIRECTION INPUT ;
    USE SIGNAL ;
    PORT
      LAYER M5 ;
        RECT  8.976 0 9 0.084 ;
    END
  END d[87]
  PIN d[88]
    DIRECTION INPUT ;
    USE SIGNAL ;
    PORT
      LAYER M3 ;
        RECT  9.072 0 9.09 0.038 ;
    END
  END d[88]
  PIN d[89]
    DIRECTION INPUT ;
    USE SIGNAL ;
    PORT
      LAYER M5 ;
        RECT  9.168 0 9.192 0.084 ;
    END
  END d[89]
  PIN d[8]
    DIRECTION INPUT ;
    USE SIGNAL ;
    PORT
      LAYER M3 ;
        RECT  1.368 0 1.386 0.038 ;
    END
  END d[8]
  PIN d[90]
    DIRECTION INPUT ;
    USE SIGNAL ;
    PORT
      LAYER M3 ;
        RECT  9.288 0 9.306 0.038 ;
    END
  END d[90]
  PIN d[91]
    DIRECTION INPUT ;
    USE SIGNAL ;
    PORT
      LAYER M5 ;
        RECT  9.36 0 9.384 0.084 ;
    END
  END d[91]
  PIN d[92]
    DIRECTION INPUT ;
    USE SIGNAL ;
    PORT
      LAYER M3 ;
        RECT  9.468 0 9.486 0.038 ;
    END
  END d[92]
  PIN d[93]
    DIRECTION INPUT ;
    USE SIGNAL ;
    PORT
      LAYER M5 ;
        RECT  9.552 0 9.576 0.084 ;
    END
  END d[93]
  PIN d[94]
    DIRECTION INPUT ;
    USE SIGNAL ;
    PORT
      LAYER M3 ;
        RECT  9.648 0 9.666 0.038 ;
    END
  END d[94]
  PIN d[95]
    DIRECTION INPUT ;
    USE SIGNAL ;
    PORT
      LAYER M5 ;
        RECT  9.744 0 9.768 0.084 ;
    END
  END d[95]
  PIN d[96]
    DIRECTION INPUT ;
    USE SIGNAL ;
    PORT
      LAYER M3 ;
        RECT  9.864 0 9.882 0.038 ;
    END
  END d[96]
  PIN d[97]
    DIRECTION INPUT ;
    USE SIGNAL ;
    PORT
      LAYER M5 ;
        RECT  9.936 0 9.96 0.084 ;
    END
  END d[97]
  PIN d[98]
    DIRECTION INPUT ;
    USE SIGNAL ;
    PORT
      LAYER M3 ;
        RECT  10.044 0 10.062 0.038 ;
    END
  END d[98]
  PIN d[99]
    DIRECTION INPUT ;
    USE SIGNAL ;
    PORT
      LAYER M5 ;
        RECT  10.128 0 10.152 0.084 ;
    END
  END d[99]
  PIN d[9]
    DIRECTION INPUT ;
    USE SIGNAL ;
    PORT
      LAYER M5 ;
        RECT  1.44 0 1.464 0.084 ;
    END
  END d[9]
  PIN q[0]
    DIRECTION OUTPUT ;
    USE SIGNAL ;
    PORT
      LAYER M3 ;
        RECT  0.576 51.802 0.594 51.84 ;
    END
  END q[0]
  PIN q[100]
    DIRECTION OUTPUT ;
    USE SIGNAL ;
    PORT
      LAYER M3 ;
        RECT  10.404 51.802 10.422 51.84 ;
    END
  END q[100]
  PIN q[101]
    DIRECTION OUTPUT ;
    USE SIGNAL ;
    PORT
      LAYER M5 ;
        RECT  10.512 51.756 10.536 51.84 ;
    END
  END q[101]
  PIN q[102]
    DIRECTION OUTPUT ;
    USE SIGNAL ;
    PORT
      LAYER M3 ;
        RECT  10.62 51.802 10.638 51.84 ;
    END
  END q[102]
  PIN q[103]
    DIRECTION OUTPUT ;
    USE SIGNAL ;
    PORT
      LAYER M5 ;
        RECT  10.704 51.756 10.728 51.84 ;
    END
  END q[103]
  PIN q[104]
    DIRECTION OUTPUT ;
    USE SIGNAL ;
    PORT
      LAYER M3 ;
        RECT  10.8 51.802 10.818 51.84 ;
    END
  END q[104]
  PIN q[105]
    DIRECTION OUTPUT ;
    USE SIGNAL ;
    PORT
      LAYER M5 ;
        RECT  10.896 51.756 10.92 51.84 ;
    END
  END q[105]
  PIN q[106]
    DIRECTION OUTPUT ;
    USE SIGNAL ;
    PORT
      LAYER M3 ;
        RECT  11.016 51.802 11.034 51.84 ;
    END
  END q[106]
  PIN q[107]
    DIRECTION OUTPUT ;
    USE SIGNAL ;
    PORT
      LAYER M5 ;
        RECT  11.088 51.756 11.112 51.84 ;
    END
  END q[107]
  PIN q[108]
    DIRECTION OUTPUT ;
    USE SIGNAL ;
    PORT
      LAYER M3 ;
        RECT  11.196 51.802 11.214 51.84 ;
    END
  END q[108]
  PIN q[109]
    DIRECTION OUTPUT ;
    USE SIGNAL ;
    PORT
      LAYER M5 ;
        RECT  11.28 51.756 11.304 51.84 ;
    END
  END q[109]
  PIN q[10]
    DIRECTION OUTPUT ;
    USE SIGNAL ;
    PORT
      LAYER M3 ;
        RECT  1.548 51.802 1.566 51.84 ;
    END
  END q[10]
  PIN q[110]
    DIRECTION OUTPUT ;
    USE SIGNAL ;
    PORT
      LAYER M3 ;
        RECT  11.412 51.802 11.43 51.84 ;
    END
  END q[110]
  PIN q[111]
    DIRECTION OUTPUT ;
    USE SIGNAL ;
    PORT
      LAYER M5 ;
        RECT  11.52 51.756 11.544 51.84 ;
    END
  END q[111]
  PIN q[112]
    DIRECTION OUTPUT ;
    USE SIGNAL ;
    PORT
      LAYER M3 ;
        RECT  11.592 51.802 11.61 51.84 ;
    END
  END q[112]
  PIN q[113]
    DIRECTION OUTPUT ;
    USE SIGNAL ;
    PORT
      LAYER M5 ;
        RECT  11.712 51.756 11.736 51.84 ;
    END
  END q[113]
  PIN q[114]
    DIRECTION OUTPUT ;
    USE SIGNAL ;
    PORT
      LAYER M3 ;
        RECT  11.808 51.802 11.826 51.84 ;
    END
  END q[114]
  PIN q[115]
    DIRECTION OUTPUT ;
    USE SIGNAL ;
    PORT
      LAYER M5 ;
        RECT  11.904 51.756 11.928 51.84 ;
    END
  END q[115]
  PIN q[116]
    DIRECTION OUTPUT ;
    USE SIGNAL ;
    PORT
      LAYER M3 ;
        RECT  11.988 51.802 12.006 51.84 ;
    END
  END q[116]
  PIN q[117]
    DIRECTION OUTPUT ;
    USE SIGNAL ;
    PORT
      LAYER M5 ;
        RECT  12.096 51.756 12.12 51.84 ;
    END
  END q[117]
  PIN q[118]
    DIRECTION OUTPUT ;
    USE SIGNAL ;
    PORT
      LAYER M3 ;
        RECT  12.204 51.802 12.222 51.84 ;
    END
  END q[118]
  PIN q[119]
    DIRECTION OUTPUT ;
    USE SIGNAL ;
    PORT
      LAYER M5 ;
        RECT  12.288 51.756 12.312 51.84 ;
    END
  END q[119]
  PIN q[11]
    DIRECTION OUTPUT ;
    USE SIGNAL ;
    PORT
      LAYER M5 ;
        RECT  1.68 51.756 1.704 51.84 ;
    END
  END q[11]
  PIN q[120]
    DIRECTION OUTPUT ;
    USE SIGNAL ;
    PORT
      LAYER M3 ;
        RECT  12.384 51.802 12.402 51.84 ;
    END
  END q[120]
  PIN q[121]
    DIRECTION OUTPUT ;
    USE SIGNAL ;
    PORT
      LAYER M5 ;
        RECT  12.48 51.756 12.504 51.84 ;
    END
  END q[121]
  PIN q[122]
    DIRECTION OUTPUT ;
    USE SIGNAL ;
    PORT
      LAYER M3 ;
        RECT  12.6 51.802 12.618 51.84 ;
    END
  END q[122]
  PIN q[123]
    DIRECTION OUTPUT ;
    USE SIGNAL ;
    PORT
      LAYER M5 ;
        RECT  12.672 51.756 12.696 51.84 ;
    END
  END q[123]
  PIN q[124]
    DIRECTION OUTPUT ;
    USE SIGNAL ;
    PORT
      LAYER M3 ;
        RECT  12.78 51.802 12.798 51.84 ;
    END
  END q[124]
  PIN q[125]
    DIRECTION OUTPUT ;
    USE SIGNAL ;
    PORT
      LAYER M5 ;
        RECT  12.864 51.756 12.888 51.84 ;
    END
  END q[125]
  PIN q[126]
    DIRECTION OUTPUT ;
    USE SIGNAL ;
    PORT
      LAYER M3 ;
        RECT  12.96 51.802 12.978 51.84 ;
    END
  END q[126]
  PIN q[127]
    DIRECTION OUTPUT ;
    USE SIGNAL ;
    PORT
      LAYER M5 ;
        RECT  13.056 51.756 13.08 51.84 ;
    END
  END q[127]
  PIN q[128]
    DIRECTION OUTPUT ;
    USE SIGNAL ;
    PORT
      LAYER M3 ;
        RECT  13.176 51.802 13.194 51.84 ;
    END
  END q[128]
  PIN q[129]
    DIRECTION OUTPUT ;
    USE SIGNAL ;
    PORT
      LAYER M5 ;
        RECT  13.248 51.756 13.272 51.84 ;
    END
  END q[129]
  PIN q[12]
    DIRECTION OUTPUT ;
    USE SIGNAL ;
    PORT
      LAYER M3 ;
        RECT  1.764 51.802 1.782 51.84 ;
    END
  END q[12]
  PIN q[130]
    DIRECTION OUTPUT ;
    USE SIGNAL ;
    PORT
      LAYER M3 ;
        RECT  13.356 51.802 13.374 51.84 ;
    END
  END q[130]
  PIN q[131]
    DIRECTION OUTPUT ;
    USE SIGNAL ;
    PORT
      LAYER M5 ;
        RECT  13.488 51.756 13.512 51.84 ;
    END
  END q[131]
  PIN q[132]
    DIRECTION OUTPUT ;
    USE SIGNAL ;
    PORT
      LAYER M3 ;
        RECT  13.572 51.802 13.59 51.84 ;
    END
  END q[132]
  PIN q[133]
    DIRECTION OUTPUT ;
    USE SIGNAL ;
    PORT
      LAYER M5 ;
        RECT  13.68 51.756 13.704 51.84 ;
    END
  END q[133]
  PIN q[134]
    DIRECTION OUTPUT ;
    USE SIGNAL ;
    PORT
      LAYER M3 ;
        RECT  13.752 51.802 13.77 51.84 ;
    END
  END q[134]
  PIN q[135]
    DIRECTION OUTPUT ;
    USE SIGNAL ;
    PORT
      LAYER M5 ;
        RECT  13.872 51.756 13.896 51.84 ;
    END
  END q[135]
  PIN q[136]
    DIRECTION OUTPUT ;
    USE SIGNAL ;
    PORT
      LAYER M3 ;
        RECT  13.968 51.802 13.986 51.84 ;
    END
  END q[136]
  PIN q[137]
    DIRECTION OUTPUT ;
    USE SIGNAL ;
    PORT
      LAYER M5 ;
        RECT  14.064 51.756 14.088 51.84 ;
    END
  END q[137]
  PIN q[138]
    DIRECTION OUTPUT ;
    USE SIGNAL ;
    PORT
      LAYER M3 ;
        RECT  14.148 51.802 14.166 51.84 ;
    END
  END q[138]
  PIN q[139]
    DIRECTION OUTPUT ;
    USE SIGNAL ;
    PORT
      LAYER M5 ;
        RECT  14.256 51.756 14.28 51.84 ;
    END
  END q[139]
  PIN q[13]
    DIRECTION OUTPUT ;
    USE SIGNAL ;
    PORT
      LAYER M5 ;
        RECT  1.872 51.756 1.896 51.84 ;
    END
  END q[13]
  PIN q[140]
    DIRECTION OUTPUT ;
    USE SIGNAL ;
    PORT
      LAYER M3 ;
        RECT  14.364 51.802 14.382 51.84 ;
    END
  END q[140]
  PIN q[141]
    DIRECTION OUTPUT ;
    USE SIGNAL ;
    PORT
      LAYER M5 ;
        RECT  14.448 51.756 14.472 51.84 ;
    END
  END q[141]
  PIN q[142]
    DIRECTION OUTPUT ;
    USE SIGNAL ;
    PORT
      LAYER M3 ;
        RECT  14.544 51.802 14.562 51.84 ;
    END
  END q[142]
  PIN q[143]
    DIRECTION OUTPUT ;
    USE SIGNAL ;
    PORT
      LAYER M5 ;
        RECT  14.64 51.756 14.664 51.84 ;
    END
  END q[143]
  PIN q[144]
    DIRECTION OUTPUT ;
    USE SIGNAL ;
    PORT
      LAYER M3 ;
        RECT  14.76 51.802 14.778 51.84 ;
    END
  END q[144]
  PIN q[145]
    DIRECTION OUTPUT ;
    USE SIGNAL ;
    PORT
      LAYER M5 ;
        RECT  14.832 51.756 14.856 51.84 ;
    END
  END q[145]
  PIN q[146]
    DIRECTION OUTPUT ;
    USE SIGNAL ;
    PORT
      LAYER M3 ;
        RECT  14.94 51.802 14.958 51.84 ;
    END
  END q[146]
  PIN q[147]
    DIRECTION OUTPUT ;
    USE SIGNAL ;
    PORT
      LAYER M5 ;
        RECT  15.024 51.756 15.048 51.84 ;
    END
  END q[147]
  PIN q[148]
    DIRECTION OUTPUT ;
    USE SIGNAL ;
    PORT
      LAYER M3 ;
        RECT  15.156 51.802 15.174 51.84 ;
    END
  END q[148]
  PIN q[149]
    DIRECTION OUTPUT ;
    USE SIGNAL ;
    PORT
      LAYER M5 ;
        RECT  15.216 51.756 15.24 51.84 ;
    END
  END q[149]
  PIN q[14]
    DIRECTION OUTPUT ;
    USE SIGNAL ;
    PORT
      LAYER M3 ;
        RECT  1.944 51.802 1.962 51.84 ;
    END
  END q[14]
  PIN q[150]
    DIRECTION OUTPUT ;
    USE SIGNAL ;
    PORT
      LAYER M3 ;
        RECT  15.336 51.802 15.354 51.84 ;
    END
  END q[150]
  PIN q[151]
    DIRECTION OUTPUT ;
    USE SIGNAL ;
    PORT
      LAYER M5 ;
        RECT  15.408 51.756 15.432 51.84 ;
    END
  END q[151]
  PIN q[152]
    DIRECTION OUTPUT ;
    USE SIGNAL ;
    PORT
      LAYER M3 ;
        RECT  15.516 51.802 15.534 51.84 ;
    END
  END q[152]
  PIN q[153]
    DIRECTION OUTPUT ;
    USE SIGNAL ;
    PORT
      LAYER M5 ;
        RECT  15.648 51.756 15.672 51.84 ;
    END
  END q[153]
  PIN q[154]
    DIRECTION OUTPUT ;
    USE SIGNAL ;
    PORT
      LAYER M3 ;
        RECT  15.732 51.802 15.75 51.84 ;
    END
  END q[154]
  PIN q[155]
    DIRECTION OUTPUT ;
    USE SIGNAL ;
    PORT
      LAYER M5 ;
        RECT  15.84 51.756 15.864 51.84 ;
    END
  END q[155]
  PIN q[156]
    DIRECTION OUTPUT ;
    USE SIGNAL ;
    PORT
      LAYER M3 ;
        RECT  15.912 51.802 15.93 51.84 ;
    END
  END q[156]
  PIN q[157]
    DIRECTION OUTPUT ;
    USE SIGNAL ;
    PORT
      LAYER M5 ;
        RECT  16.032 51.756 16.056 51.84 ;
    END
  END q[157]
  PIN q[158]
    DIRECTION OUTPUT ;
    USE SIGNAL ;
    PORT
      LAYER M3 ;
        RECT  16.128 51.802 16.146 51.84 ;
    END
  END q[158]
  PIN q[159]
    DIRECTION OUTPUT ;
    USE SIGNAL ;
    PORT
      LAYER M5 ;
        RECT  16.224 51.756 16.248 51.84 ;
    END
  END q[159]
  PIN q[15]
    DIRECTION OUTPUT ;
    USE SIGNAL ;
    PORT
      LAYER M5 ;
        RECT  2.064 51.756 2.088 51.84 ;
    END
  END q[15]
  PIN q[160]
    DIRECTION OUTPUT ;
    USE SIGNAL ;
    PORT
      LAYER M3 ;
        RECT  16.308 51.802 16.326 51.84 ;
    END
  END q[160]
  PIN q[161]
    DIRECTION OUTPUT ;
    USE SIGNAL ;
    PORT
      LAYER M5 ;
        RECT  16.416 51.756 16.44 51.84 ;
    END
  END q[161]
  PIN q[162]
    DIRECTION OUTPUT ;
    USE SIGNAL ;
    PORT
      LAYER M3 ;
        RECT  16.524 51.802 16.542 51.84 ;
    END
  END q[162]
  PIN q[163]
    DIRECTION OUTPUT ;
    USE SIGNAL ;
    PORT
      LAYER M5 ;
        RECT  16.608 51.756 16.632 51.84 ;
    END
  END q[163]
  PIN q[164]
    DIRECTION OUTPUT ;
    USE SIGNAL ;
    PORT
      LAYER M3 ;
        RECT  16.704 51.802 16.722 51.84 ;
    END
  END q[164]
  PIN q[165]
    DIRECTION OUTPUT ;
    USE SIGNAL ;
    PORT
      LAYER M5 ;
        RECT  16.8 51.756 16.824 51.84 ;
    END
  END q[165]
  PIN q[166]
    DIRECTION OUTPUT ;
    USE SIGNAL ;
    PORT
      LAYER M3 ;
        RECT  16.92 51.802 16.938 51.84 ;
    END
  END q[166]
  PIN q[167]
    DIRECTION OUTPUT ;
    USE SIGNAL ;
    PORT
      LAYER M5 ;
        RECT  16.992 51.756 17.016 51.84 ;
    END
  END q[167]
  PIN q[168]
    DIRECTION OUTPUT ;
    USE SIGNAL ;
    PORT
      LAYER M3 ;
        RECT  17.1 51.802 17.118 51.84 ;
    END
  END q[168]
  PIN q[169]
    DIRECTION OUTPUT ;
    USE SIGNAL ;
    PORT
      LAYER M5 ;
        RECT  17.184 51.756 17.208 51.84 ;
    END
  END q[169]
  PIN q[16]
    DIRECTION OUTPUT ;
    USE SIGNAL ;
    PORT
      LAYER M3 ;
        RECT  2.16 51.802 2.178 51.84 ;
    END
  END q[16]
  PIN q[170]
    DIRECTION OUTPUT ;
    USE SIGNAL ;
    PORT
      LAYER M3 ;
        RECT  17.316 51.802 17.334 51.84 ;
    END
  END q[170]
  PIN q[171]
    DIRECTION OUTPUT ;
    USE SIGNAL ;
    PORT
      LAYER M5 ;
        RECT  17.376 51.756 17.4 51.84 ;
    END
  END q[171]
  PIN q[172]
    DIRECTION OUTPUT ;
    USE SIGNAL ;
    PORT
      LAYER M3 ;
        RECT  17.496 51.802 17.514 51.84 ;
    END
  END q[172]
  PIN q[173]
    DIRECTION OUTPUT ;
    USE SIGNAL ;
    PORT
      LAYER M5 ;
        RECT  17.616 51.756 17.64 51.84 ;
    END
  END q[173]
  PIN q[174]
    DIRECTION OUTPUT ;
    USE SIGNAL ;
    PORT
      LAYER M3 ;
        RECT  17.712 51.802 17.73 51.84 ;
    END
  END q[174]
  PIN q[175]
    DIRECTION OUTPUT ;
    USE SIGNAL ;
    PORT
      LAYER M5 ;
        RECT  17.808 51.756 17.832 51.84 ;
    END
  END q[175]
  PIN q[176]
    DIRECTION OUTPUT ;
    USE SIGNAL ;
    PORT
      LAYER M3 ;
        RECT  17.892 51.802 17.91 51.84 ;
    END
  END q[176]
  PIN q[177]
    DIRECTION OUTPUT ;
    USE SIGNAL ;
    PORT
      LAYER M5 ;
        RECT  18 51.756 18.024 51.84 ;
    END
  END q[177]
  PIN q[178]
    DIRECTION OUTPUT ;
    USE SIGNAL ;
    PORT
      LAYER M3 ;
        RECT  18.108 51.802 18.126 51.84 ;
    END
  END q[178]
  PIN q[179]
    DIRECTION OUTPUT ;
    USE SIGNAL ;
    PORT
      LAYER M5 ;
        RECT  18.192 51.756 18.216 51.84 ;
    END
  END q[179]
  PIN q[17]
    DIRECTION OUTPUT ;
    USE SIGNAL ;
    PORT
      LAYER M5 ;
        RECT  2.256 51.756 2.28 51.84 ;
    END
  END q[17]
  PIN q[180]
    DIRECTION OUTPUT ;
    USE SIGNAL ;
    PORT
      LAYER M3 ;
        RECT  18.288 51.802 18.306 51.84 ;
    END
  END q[180]
  PIN q[181]
    DIRECTION OUTPUT ;
    USE SIGNAL ;
    PORT
      LAYER M5 ;
        RECT  18.384 51.756 18.408 51.84 ;
    END
  END q[181]
  PIN q[182]
    DIRECTION OUTPUT ;
    USE SIGNAL ;
    PORT
      LAYER M3 ;
        RECT  18.468 51.802 18.486 51.84 ;
    END
  END q[182]
  PIN q[183]
    DIRECTION OUTPUT ;
    USE SIGNAL ;
    PORT
      LAYER M5 ;
        RECT  18.576 51.756 18.6 51.84 ;
    END
  END q[183]
  PIN q[184]
    DIRECTION OUTPUT ;
    USE SIGNAL ;
    PORT
      LAYER M3 ;
        RECT  18.684 51.802 18.702 51.84 ;
    END
  END q[184]
  PIN q[185]
    DIRECTION OUTPUT ;
    USE SIGNAL ;
    PORT
      LAYER M5 ;
        RECT  18.768 51.756 18.792 51.84 ;
    END
  END q[185]
  PIN q[186]
    DIRECTION OUTPUT ;
    USE SIGNAL ;
    PORT
      LAYER M3 ;
        RECT  18.864 51.802 18.882 51.84 ;
    END
  END q[186]
  PIN q[187]
    DIRECTION OUTPUT ;
    USE SIGNAL ;
    PORT
      LAYER M5 ;
        RECT  18.96 51.756 18.984 51.84 ;
    END
  END q[187]
  PIN q[188]
    DIRECTION OUTPUT ;
    USE SIGNAL ;
    PORT
      LAYER M3 ;
        RECT  19.08 51.802 19.098 51.84 ;
    END
  END q[188]
  PIN q[189]
    DIRECTION OUTPUT ;
    USE SIGNAL ;
    PORT
      LAYER M5 ;
        RECT  19.152 51.756 19.176 51.84 ;
    END
  END q[189]
  PIN q[18]
    DIRECTION OUTPUT ;
    USE SIGNAL ;
    PORT
      LAYER M3 ;
        RECT  2.34 51.802 2.358 51.84 ;
    END
  END q[18]
  PIN q[190]
    DIRECTION OUTPUT ;
    USE SIGNAL ;
    PORT
      LAYER M3 ;
        RECT  19.26 51.802 19.278 51.84 ;
    END
  END q[190]
  PIN q[191]
    DIRECTION OUTPUT ;
    USE SIGNAL ;
    PORT
      LAYER M5 ;
        RECT  19.344 51.756 19.368 51.84 ;
    END
  END q[191]
  PIN q[192]
    DIRECTION OUTPUT ;
    USE SIGNAL ;
    PORT
      LAYER M3 ;
        RECT  19.476 51.802 19.494 51.84 ;
    END
  END q[192]
  PIN q[193]
    DIRECTION OUTPUT ;
    USE SIGNAL ;
    PORT
      LAYER M5 ;
        RECT  19.584 51.756 19.608 51.84 ;
    END
  END q[193]
  PIN q[194]
    DIRECTION OUTPUT ;
    USE SIGNAL ;
    PORT
      LAYER M3 ;
        RECT  19.656 51.802 19.674 51.84 ;
    END
  END q[194]
  PIN q[195]
    DIRECTION OUTPUT ;
    USE SIGNAL ;
    PORT
      LAYER M5 ;
        RECT  19.776 51.756 19.8 51.84 ;
    END
  END q[195]
  PIN q[196]
    DIRECTION OUTPUT ;
    USE SIGNAL ;
    PORT
      LAYER M3 ;
        RECT  19.872 51.802 19.89 51.84 ;
    END
  END q[196]
  PIN q[197]
    DIRECTION OUTPUT ;
    USE SIGNAL ;
    PORT
      LAYER M5 ;
        RECT  19.968 51.756 19.992 51.84 ;
    END
  END q[197]
  PIN q[198]
    DIRECTION OUTPUT ;
    USE SIGNAL ;
    PORT
      LAYER M3 ;
        RECT  20.052 51.802 20.07 51.84 ;
    END
  END q[198]
  PIN q[199]
    DIRECTION OUTPUT ;
    USE SIGNAL ;
    PORT
      LAYER M5 ;
        RECT  20.16 51.756 20.184 51.84 ;
    END
  END q[199]
  PIN q[19]
    DIRECTION OUTPUT ;
    USE SIGNAL ;
    PORT
      LAYER M5 ;
        RECT  2.448 51.756 2.472 51.84 ;
    END
  END q[19]
  PIN q[1]
    DIRECTION OUTPUT ;
    USE SIGNAL ;
    PORT
      LAYER M5 ;
        RECT  0.672 51.756 0.696 51.84 ;
    END
  END q[1]
  PIN q[200]
    DIRECTION OUTPUT ;
    USE SIGNAL ;
    PORT
      LAYER M3 ;
        RECT  20.268 51.802 20.286 51.84 ;
    END
  END q[200]
  PIN q[201]
    DIRECTION OUTPUT ;
    USE SIGNAL ;
    PORT
      LAYER M5 ;
        RECT  20.352 51.756 20.376 51.84 ;
    END
  END q[201]
  PIN q[202]
    DIRECTION OUTPUT ;
    USE SIGNAL ;
    PORT
      LAYER M3 ;
        RECT  20.448 51.802 20.466 51.84 ;
    END
  END q[202]
  PIN q[203]
    DIRECTION OUTPUT ;
    USE SIGNAL ;
    PORT
      LAYER M5 ;
        RECT  20.544 51.756 20.568 51.84 ;
    END
  END q[203]
  PIN q[204]
    DIRECTION OUTPUT ;
    USE SIGNAL ;
    PORT
      LAYER M3 ;
        RECT  20.664 51.802 20.682 51.84 ;
    END
  END q[204]
  PIN q[205]
    DIRECTION OUTPUT ;
    USE SIGNAL ;
    PORT
      LAYER M5 ;
        RECT  20.736 51.756 20.76 51.84 ;
    END
  END q[205]
  PIN q[206]
    DIRECTION OUTPUT ;
    USE SIGNAL ;
    PORT
      LAYER M3 ;
        RECT  20.844 51.802 20.862 51.84 ;
    END
  END q[206]
  PIN q[207]
    DIRECTION OUTPUT ;
    USE SIGNAL ;
    PORT
      LAYER M5 ;
        RECT  20.928 51.756 20.952 51.84 ;
    END
  END q[207]
  PIN q[208]
    DIRECTION OUTPUT ;
    USE SIGNAL ;
    PORT
      LAYER M3 ;
        RECT  21.06 51.802 21.078 51.84 ;
    END
  END q[208]
  PIN q[209]
    DIRECTION OUTPUT ;
    USE SIGNAL ;
    PORT
      LAYER M5 ;
        RECT  21.12 51.756 21.144 51.84 ;
    END
  END q[209]
  PIN q[20]
    DIRECTION OUTPUT ;
    USE SIGNAL ;
    PORT
      LAYER M3 ;
        RECT  2.556 51.802 2.574 51.84 ;
    END
  END q[20]
  PIN q[210]
    DIRECTION OUTPUT ;
    USE SIGNAL ;
    PORT
      LAYER M3 ;
        RECT  21.24 51.802 21.258 51.84 ;
    END
  END q[210]
  PIN q[211]
    DIRECTION OUTPUT ;
    USE SIGNAL ;
    PORT
      LAYER M5 ;
        RECT  21.312 51.756 21.336 51.84 ;
    END
  END q[211]
  PIN q[212]
    DIRECTION OUTPUT ;
    USE SIGNAL ;
    PORT
      LAYER M3 ;
        RECT  21.42 51.802 21.438 51.84 ;
    END
  END q[212]
  PIN q[213]
    DIRECTION OUTPUT ;
    USE SIGNAL ;
    PORT
      LAYER M5 ;
        RECT  21.552 51.756 21.576 51.84 ;
    END
  END q[213]
  PIN q[214]
    DIRECTION OUTPUT ;
    USE SIGNAL ;
    PORT
      LAYER M3 ;
        RECT  21.636 51.802 21.654 51.84 ;
    END
  END q[214]
  PIN q[215]
    DIRECTION OUTPUT ;
    USE SIGNAL ;
    PORT
      LAYER M5 ;
        RECT  21.744 51.756 21.768 51.84 ;
    END
  END q[215]
  PIN q[216]
    DIRECTION OUTPUT ;
    USE SIGNAL ;
    PORT
      LAYER M3 ;
        RECT  21.816 51.802 21.834 51.84 ;
    END
  END q[216]
  PIN q[217]
    DIRECTION OUTPUT ;
    USE SIGNAL ;
    PORT
      LAYER M5 ;
        RECT  21.936 51.756 21.96 51.84 ;
    END
  END q[217]
  PIN q[218]
    DIRECTION OUTPUT ;
    USE SIGNAL ;
    PORT
      LAYER M3 ;
        RECT  22.032 51.802 22.05 51.84 ;
    END
  END q[218]
  PIN q[219]
    DIRECTION OUTPUT ;
    USE SIGNAL ;
    PORT
      LAYER M5 ;
        RECT  22.128 51.756 22.152 51.84 ;
    END
  END q[219]
  PIN q[21]
    DIRECTION OUTPUT ;
    USE SIGNAL ;
    PORT
      LAYER M5 ;
        RECT  2.64 51.756 2.664 51.84 ;
    END
  END q[21]
  PIN q[220]
    DIRECTION OUTPUT ;
    USE SIGNAL ;
    PORT
      LAYER M3 ;
        RECT  22.212 51.802 22.23 51.84 ;
    END
  END q[220]
  PIN q[221]
    DIRECTION OUTPUT ;
    USE SIGNAL ;
    PORT
      LAYER M5 ;
        RECT  22.32 51.756 22.344 51.84 ;
    END
  END q[221]
  PIN q[222]
    DIRECTION OUTPUT ;
    USE SIGNAL ;
    PORT
      LAYER M3 ;
        RECT  22.428 51.802 22.446 51.84 ;
    END
  END q[222]
  PIN q[223]
    DIRECTION OUTPUT ;
    USE SIGNAL ;
    PORT
      LAYER M5 ;
        RECT  22.512 51.756 22.536 51.84 ;
    END
  END q[223]
  PIN q[224]
    DIRECTION OUTPUT ;
    USE SIGNAL ;
    PORT
      LAYER M3 ;
        RECT  22.608 51.802 22.626 51.84 ;
    END
  END q[224]
  PIN q[225]
    DIRECTION OUTPUT ;
    USE SIGNAL ;
    PORT
      LAYER M5 ;
        RECT  22.704 51.756 22.728 51.84 ;
    END
  END q[225]
  PIN q[226]
    DIRECTION OUTPUT ;
    USE SIGNAL ;
    PORT
      LAYER M3 ;
        RECT  22.824 51.802 22.842 51.84 ;
    END
  END q[226]
  PIN q[227]
    DIRECTION OUTPUT ;
    USE SIGNAL ;
    PORT
      LAYER M5 ;
        RECT  22.896 51.756 22.92 51.84 ;
    END
  END q[227]
  PIN q[228]
    DIRECTION OUTPUT ;
    USE SIGNAL ;
    PORT
      LAYER M3 ;
        RECT  23.004 51.802 23.022 51.84 ;
    END
  END q[228]
  PIN q[229]
    DIRECTION OUTPUT ;
    USE SIGNAL ;
    PORT
      LAYER M5 ;
        RECT  23.088 51.756 23.112 51.84 ;
    END
  END q[229]
  PIN q[22]
    DIRECTION OUTPUT ;
    USE SIGNAL ;
    PORT
      LAYER M3 ;
        RECT  2.736 51.802 2.754 51.84 ;
    END
  END q[22]
  PIN q[230]
    DIRECTION OUTPUT ;
    USE SIGNAL ;
    PORT
      LAYER M3 ;
        RECT  23.22 51.802 23.238 51.84 ;
    END
  END q[230]
  PIN q[231]
    DIRECTION OUTPUT ;
    USE SIGNAL ;
    PORT
      LAYER M5 ;
        RECT  23.28 51.756 23.304 51.84 ;
    END
  END q[231]
  PIN q[232]
    DIRECTION OUTPUT ;
    USE SIGNAL ;
    PORT
      LAYER M3 ;
        RECT  23.4 51.802 23.418 51.84 ;
    END
  END q[232]
  PIN q[233]
    DIRECTION OUTPUT ;
    USE SIGNAL ;
    PORT
      LAYER M5 ;
        RECT  23.52 51.756 23.544 51.84 ;
    END
  END q[233]
  PIN q[234]
    DIRECTION OUTPUT ;
    USE SIGNAL ;
    PORT
      LAYER M3 ;
        RECT  23.616 51.802 23.634 51.84 ;
    END
  END q[234]
  PIN q[235]
    DIRECTION OUTPUT ;
    USE SIGNAL ;
    PORT
      LAYER M5 ;
        RECT  23.712 51.756 23.736 51.84 ;
    END
  END q[235]
  PIN q[236]
    DIRECTION OUTPUT ;
    USE SIGNAL ;
    PORT
      LAYER M3 ;
        RECT  23.796 51.802 23.814 51.84 ;
    END
  END q[236]
  PIN q[237]
    DIRECTION OUTPUT ;
    USE SIGNAL ;
    PORT
      LAYER M5 ;
        RECT  23.904 51.756 23.928 51.84 ;
    END
  END q[237]
  PIN q[238]
    DIRECTION OUTPUT ;
    USE SIGNAL ;
    PORT
      LAYER M3 ;
        RECT  23.976 51.802 23.994 51.84 ;
    END
  END q[238]
  PIN q[239]
    DIRECTION OUTPUT ;
    USE SIGNAL ;
    PORT
      LAYER M5 ;
        RECT  24.096 51.756 24.12 51.84 ;
    END
  END q[239]
  PIN q[23]
    DIRECTION OUTPUT ;
    USE SIGNAL ;
    PORT
      LAYER M5 ;
        RECT  2.832 51.756 2.856 51.84 ;
    END
  END q[23]
  PIN q[240]
    DIRECTION OUTPUT ;
    USE SIGNAL ;
    PORT
      LAYER M3 ;
        RECT  24.192 51.802 24.21 51.84 ;
    END
  END q[240]
  PIN q[241]
    DIRECTION OUTPUT ;
    USE SIGNAL ;
    PORT
      LAYER M5 ;
        RECT  24.288 51.756 24.312 51.84 ;
    END
  END q[241]
  PIN q[242]
    DIRECTION OUTPUT ;
    USE SIGNAL ;
    PORT
      LAYER M3 ;
        RECT  24.372 51.802 24.39 51.84 ;
    END
  END q[242]
  PIN q[243]
    DIRECTION OUTPUT ;
    USE SIGNAL ;
    PORT
      LAYER M5 ;
        RECT  24.48 51.756 24.504 51.84 ;
    END
  END q[243]
  PIN q[244]
    DIRECTION OUTPUT ;
    USE SIGNAL ;
    PORT
      LAYER M3 ;
        RECT  24.588 51.802 24.606 51.84 ;
    END
  END q[244]
  PIN q[245]
    DIRECTION OUTPUT ;
    USE SIGNAL ;
    PORT
      LAYER M5 ;
        RECT  24.672 51.756 24.696 51.84 ;
    END
  END q[245]
  PIN q[246]
    DIRECTION OUTPUT ;
    USE SIGNAL ;
    PORT
      LAYER M3 ;
        RECT  24.768 51.802 24.786 51.84 ;
    END
  END q[246]
  PIN q[247]
    DIRECTION OUTPUT ;
    USE SIGNAL ;
    PORT
      LAYER M5 ;
        RECT  24.864 51.756 24.888 51.84 ;
    END
  END q[247]
  PIN q[248]
    DIRECTION OUTPUT ;
    USE SIGNAL ;
    PORT
      LAYER M3 ;
        RECT  24.984 51.802 25.002 51.84 ;
    END
  END q[248]
  PIN q[249]
    DIRECTION OUTPUT ;
    USE SIGNAL ;
    PORT
      LAYER M5 ;
        RECT  25.056 51.756 25.08 51.84 ;
    END
  END q[249]
  PIN q[24]
    DIRECTION OUTPUT ;
    USE SIGNAL ;
    PORT
      LAYER M3 ;
        RECT  2.952 51.802 2.97 51.84 ;
    END
  END q[24]
  PIN q[250]
    DIRECTION OUTPUT ;
    USE SIGNAL ;
    PORT
      LAYER M3 ;
        RECT  25.164 51.802 25.182 51.84 ;
    END
  END q[250]
  PIN q[251]
    DIRECTION OUTPUT ;
    USE SIGNAL ;
    PORT
      LAYER M5 ;
        RECT  25.248 51.756 25.272 51.84 ;
    END
  END q[251]
  PIN q[252]
    DIRECTION OUTPUT ;
    USE SIGNAL ;
    PORT
      LAYER M3 ;
        RECT  25.38 51.802 25.398 51.84 ;
    END
  END q[252]
  PIN q[253]
    DIRECTION OUTPUT ;
    USE SIGNAL ;
    PORT
      LAYER M5 ;
        RECT  25.488 51.756 25.512 51.84 ;
    END
  END q[253]
  PIN q[254]
    DIRECTION OUTPUT ;
    USE SIGNAL ;
    PORT
      LAYER M3 ;
        RECT  25.56 51.802 25.578 51.84 ;
    END
  END q[254]
  PIN q[255]
    DIRECTION OUTPUT ;
    USE SIGNAL ;
    PORT
      LAYER M5 ;
        RECT  25.68 51.756 25.704 51.84 ;
    END
  END q[255]
  PIN q[256]
    DIRECTION OUTPUT ;
    USE SIGNAL ;
    PORT
      LAYER M3 ;
        RECT  25.776 51.802 25.794 51.84 ;
    END
  END q[256]
  PIN q[257]
    DIRECTION OUTPUT ;
    USE SIGNAL ;
    PORT
      LAYER M5 ;
        RECT  25.872 51.756 25.896 51.84 ;
    END
  END q[257]
  PIN q[258]
    DIRECTION OUTPUT ;
    USE SIGNAL ;
    PORT
      LAYER M3 ;
        RECT  25.956 51.802 25.974 51.84 ;
    END
  END q[258]
  PIN q[259]
    DIRECTION OUTPUT ;
    USE SIGNAL ;
    PORT
      LAYER M5 ;
        RECT  26.064 51.756 26.088 51.84 ;
    END
  END q[259]
  PIN q[25]
    DIRECTION OUTPUT ;
    USE SIGNAL ;
    PORT
      LAYER M5 ;
        RECT  3.024 51.756 3.048 51.84 ;
    END
  END q[25]
  PIN q[260]
    DIRECTION OUTPUT ;
    USE SIGNAL ;
    PORT
      LAYER M3 ;
        RECT  26.172 51.802 26.19 51.84 ;
    END
  END q[260]
  PIN q[261]
    DIRECTION OUTPUT ;
    USE SIGNAL ;
    PORT
      LAYER M5 ;
        RECT  26.256 51.756 26.28 51.84 ;
    END
  END q[261]
  PIN q[262]
    DIRECTION OUTPUT ;
    USE SIGNAL ;
    PORT
      LAYER M3 ;
        RECT  26.352 51.802 26.37 51.84 ;
    END
  END q[262]
  PIN q[263]
    DIRECTION OUTPUT ;
    USE SIGNAL ;
    PORT
      LAYER M5 ;
        RECT  26.448 51.756 26.472 51.84 ;
    END
  END q[263]
  PIN q[264]
    DIRECTION OUTPUT ;
    USE SIGNAL ;
    PORT
      LAYER M3 ;
        RECT  26.568 51.802 26.586 51.84 ;
    END
  END q[264]
  PIN q[265]
    DIRECTION OUTPUT ;
    USE SIGNAL ;
    PORT
      LAYER M5 ;
        RECT  26.64 51.756 26.664 51.84 ;
    END
  END q[265]
  PIN q[266]
    DIRECTION OUTPUT ;
    USE SIGNAL ;
    PORT
      LAYER M3 ;
        RECT  26.748 51.802 26.766 51.84 ;
    END
  END q[266]
  PIN q[267]
    DIRECTION OUTPUT ;
    USE SIGNAL ;
    PORT
      LAYER M5 ;
        RECT  26.832 51.756 26.856 51.84 ;
    END
  END q[267]
  PIN q[268]
    DIRECTION OUTPUT ;
    USE SIGNAL ;
    PORT
      LAYER M3 ;
        RECT  26.928 51.802 26.946 51.84 ;
    END
  END q[268]
  PIN q[269]
    DIRECTION OUTPUT ;
    USE SIGNAL ;
    PORT
      LAYER M5 ;
        RECT  27.024 51.756 27.048 51.84 ;
    END
  END q[269]
  PIN q[26]
    DIRECTION OUTPUT ;
    USE SIGNAL ;
    PORT
      LAYER M3 ;
        RECT  3.132 51.802 3.15 51.84 ;
    END
  END q[26]
  PIN q[270]
    DIRECTION OUTPUT ;
    USE SIGNAL ;
    PORT
      LAYER M3 ;
        RECT  27.144 51.802 27.162 51.84 ;
    END
  END q[270]
  PIN q[271]
    DIRECTION OUTPUT ;
    USE SIGNAL ;
    PORT
      LAYER M5 ;
        RECT  27.216 51.756 27.24 51.84 ;
    END
  END q[271]
  PIN q[272]
    DIRECTION OUTPUT ;
    USE SIGNAL ;
    PORT
      LAYER M3 ;
        RECT  27.324 51.802 27.342 51.84 ;
    END
  END q[272]
  PIN q[273]
    DIRECTION OUTPUT ;
    USE SIGNAL ;
    PORT
      LAYER M5 ;
        RECT  27.456 51.756 27.48 51.84 ;
    END
  END q[273]
  PIN q[274]
    DIRECTION OUTPUT ;
    USE SIGNAL ;
    PORT
      LAYER M3 ;
        RECT  27.54 51.802 27.558 51.84 ;
    END
  END q[274]
  PIN q[275]
    DIRECTION OUTPUT ;
    USE SIGNAL ;
    PORT
      LAYER M5 ;
        RECT  27.648 51.756 27.672 51.84 ;
    END
  END q[275]
  PIN q[276]
    DIRECTION OUTPUT ;
    USE SIGNAL ;
    PORT
      LAYER M3 ;
        RECT  27.72 51.802 27.738 51.84 ;
    END
  END q[276]
  PIN q[277]
    DIRECTION OUTPUT ;
    USE SIGNAL ;
    PORT
      LAYER M5 ;
        RECT  27.84 51.756 27.864 51.84 ;
    END
  END q[277]
  PIN q[278]
    DIRECTION OUTPUT ;
    USE SIGNAL ;
    PORT
      LAYER M3 ;
        RECT  27.936 51.802 27.954 51.84 ;
    END
  END q[278]
  PIN q[279]
    DIRECTION OUTPUT ;
    USE SIGNAL ;
    PORT
      LAYER M5 ;
        RECT  28.032 51.756 28.056 51.84 ;
    END
  END q[279]
  PIN q[27]
    DIRECTION OUTPUT ;
    USE SIGNAL ;
    PORT
      LAYER M5 ;
        RECT  3.216 51.756 3.24 51.84 ;
    END
  END q[27]
  PIN q[280]
    DIRECTION OUTPUT ;
    USE SIGNAL ;
    PORT
      LAYER M3 ;
        RECT  28.116 51.802 28.134 51.84 ;
    END
  END q[280]
  PIN q[281]
    DIRECTION OUTPUT ;
    USE SIGNAL ;
    PORT
      LAYER M5 ;
        RECT  28.224 51.756 28.248 51.84 ;
    END
  END q[281]
  PIN q[282]
    DIRECTION OUTPUT ;
    USE SIGNAL ;
    PORT
      LAYER M3 ;
        RECT  28.332 51.802 28.35 51.84 ;
    END
  END q[282]
  PIN q[283]
    DIRECTION OUTPUT ;
    USE SIGNAL ;
    PORT
      LAYER M5 ;
        RECT  28.416 51.756 28.44 51.84 ;
    END
  END q[283]
  PIN q[284]
    DIRECTION OUTPUT ;
    USE SIGNAL ;
    PORT
      LAYER M3 ;
        RECT  28.512 51.802 28.53 51.84 ;
    END
  END q[284]
  PIN q[285]
    DIRECTION OUTPUT ;
    USE SIGNAL ;
    PORT
      LAYER M5 ;
        RECT  28.608 51.756 28.632 51.84 ;
    END
  END q[285]
  PIN q[286]
    DIRECTION OUTPUT ;
    USE SIGNAL ;
    PORT
      LAYER M3 ;
        RECT  28.728 51.802 28.746 51.84 ;
    END
  END q[286]
  PIN q[287]
    DIRECTION OUTPUT ;
    USE SIGNAL ;
    PORT
      LAYER M5 ;
        RECT  28.8 51.756 28.824 51.84 ;
    END
  END q[287]
  PIN q[288]
    DIRECTION OUTPUT ;
    USE SIGNAL ;
    PORT
      LAYER M3 ;
        RECT  28.908 51.802 28.926 51.84 ;
    END
  END q[288]
  PIN q[289]
    DIRECTION OUTPUT ;
    USE SIGNAL ;
    PORT
      LAYER M5 ;
        RECT  28.992 51.756 29.016 51.84 ;
    END
  END q[289]
  PIN q[28]
    DIRECTION OUTPUT ;
    USE SIGNAL ;
    PORT
      LAYER M3 ;
        RECT  3.348 51.802 3.366 51.84 ;
    END
  END q[28]
  PIN q[290]
    DIRECTION OUTPUT ;
    USE SIGNAL ;
    PORT
      LAYER M3 ;
        RECT  29.124 51.802 29.142 51.84 ;
    END
  END q[290]
  PIN q[291]
    DIRECTION OUTPUT ;
    USE SIGNAL ;
    PORT
      LAYER M5 ;
        RECT  29.184 51.756 29.208 51.84 ;
    END
  END q[291]
  PIN q[292]
    DIRECTION OUTPUT ;
    USE SIGNAL ;
    PORT
      LAYER M3 ;
        RECT  29.304 51.802 29.322 51.84 ;
    END
  END q[292]
  PIN q[293]
    DIRECTION OUTPUT ;
    USE SIGNAL ;
    PORT
      LAYER M5 ;
        RECT  29.424 51.756 29.448 51.84 ;
    END
  END q[293]
  PIN q[294]
    DIRECTION OUTPUT ;
    USE SIGNAL ;
    PORT
      LAYER M3 ;
        RECT  29.52 51.802 29.538 51.84 ;
    END
  END q[294]
  PIN q[295]
    DIRECTION OUTPUT ;
    USE SIGNAL ;
    PORT
      LAYER M5 ;
        RECT  29.616 51.756 29.64 51.84 ;
    END
  END q[295]
  PIN q[296]
    DIRECTION OUTPUT ;
    USE SIGNAL ;
    PORT
      LAYER M3 ;
        RECT  29.7 51.802 29.718 51.84 ;
    END
  END q[296]
  PIN q[297]
    DIRECTION OUTPUT ;
    USE SIGNAL ;
    PORT
      LAYER M5 ;
        RECT  29.808 51.756 29.832 51.84 ;
    END
  END q[297]
  PIN q[298]
    DIRECTION OUTPUT ;
    USE SIGNAL ;
    PORT
      LAYER M3 ;
        RECT  29.88 51.802 29.898 51.84 ;
    END
  END q[298]
  PIN q[299]
    DIRECTION OUTPUT ;
    USE SIGNAL ;
    PORT
      LAYER M5 ;
        RECT  30 51.756 30.024 51.84 ;
    END
  END q[299]
  PIN q[29]
    DIRECTION OUTPUT ;
    USE SIGNAL ;
    PORT
      LAYER M5 ;
        RECT  3.408 51.756 3.432 51.84 ;
    END
  END q[29]
  PIN q[2]
    DIRECTION OUTPUT ;
    USE SIGNAL ;
    PORT
      LAYER M3 ;
        RECT  0.792 51.802 0.81 51.84 ;
    END
  END q[2]
  PIN q[300]
    DIRECTION OUTPUT ;
    USE SIGNAL ;
    PORT
      LAYER M3 ;
        RECT  30.096 51.802 30.114 51.84 ;
    END
  END q[300]
  PIN q[301]
    DIRECTION OUTPUT ;
    USE SIGNAL ;
    PORT
      LAYER M5 ;
        RECT  30.192 51.756 30.216 51.84 ;
    END
  END q[301]
  PIN q[302]
    DIRECTION OUTPUT ;
    USE SIGNAL ;
    PORT
      LAYER M3 ;
        RECT  30.276 51.802 30.294 51.84 ;
    END
  END q[302]
  PIN q[303]
    DIRECTION OUTPUT ;
    USE SIGNAL ;
    PORT
      LAYER M5 ;
        RECT  30.384 51.756 30.408 51.84 ;
    END
  END q[303]
  PIN q[304]
    DIRECTION OUTPUT ;
    USE SIGNAL ;
    PORT
      LAYER M3 ;
        RECT  30.492 51.802 30.51 51.84 ;
    END
  END q[304]
  PIN q[305]
    DIRECTION OUTPUT ;
    USE SIGNAL ;
    PORT
      LAYER M5 ;
        RECT  30.576 51.756 30.6 51.84 ;
    END
  END q[305]
  PIN q[306]
    DIRECTION OUTPUT ;
    USE SIGNAL ;
    PORT
      LAYER M3 ;
        RECT  30.672 51.802 30.69 51.84 ;
    END
  END q[306]
  PIN q[307]
    DIRECTION OUTPUT ;
    USE SIGNAL ;
    PORT
      LAYER M5 ;
        RECT  30.768 51.756 30.792 51.84 ;
    END
  END q[307]
  PIN q[308]
    DIRECTION OUTPUT ;
    USE SIGNAL ;
    PORT
      LAYER M3 ;
        RECT  30.888 51.802 30.906 51.84 ;
    END
  END q[308]
  PIN q[309]
    DIRECTION OUTPUT ;
    USE SIGNAL ;
    PORT
      LAYER M5 ;
        RECT  30.96 51.756 30.984 51.84 ;
    END
  END q[309]
  PIN q[30]
    DIRECTION OUTPUT ;
    USE SIGNAL ;
    PORT
      LAYER M3 ;
        RECT  3.528 51.802 3.546 51.84 ;
    END
  END q[30]
  PIN q[310]
    DIRECTION OUTPUT ;
    USE SIGNAL ;
    PORT
      LAYER M3 ;
        RECT  31.068 51.802 31.086 51.84 ;
    END
  END q[310]
  PIN q[311]
    DIRECTION OUTPUT ;
    USE SIGNAL ;
    PORT
      LAYER M5 ;
        RECT  31.152 51.756 31.176 51.84 ;
    END
  END q[311]
  PIN q[312]
    DIRECTION OUTPUT ;
    USE SIGNAL ;
    PORT
      LAYER M3 ;
        RECT  31.284 51.802 31.302 51.84 ;
    END
  END q[312]
  PIN q[313]
    DIRECTION OUTPUT ;
    USE SIGNAL ;
    PORT
      LAYER M5 ;
        RECT  31.392 51.756 31.416 51.84 ;
    END
  END q[313]
  PIN q[314]
    DIRECTION OUTPUT ;
    USE SIGNAL ;
    PORT
      LAYER M3 ;
        RECT  31.464 51.802 31.482 51.84 ;
    END
  END q[314]
  PIN q[315]
    DIRECTION OUTPUT ;
    USE SIGNAL ;
    PORT
      LAYER M5 ;
        RECT  31.584 51.756 31.608 51.84 ;
    END
  END q[315]
  PIN q[316]
    DIRECTION OUTPUT ;
    USE SIGNAL ;
    PORT
      LAYER M3 ;
        RECT  31.68 51.802 31.698 51.84 ;
    END
  END q[316]
  PIN q[317]
    DIRECTION OUTPUT ;
    USE SIGNAL ;
    PORT
      LAYER M5 ;
        RECT  31.776 51.756 31.8 51.84 ;
    END
  END q[317]
  PIN q[318]
    DIRECTION OUTPUT ;
    USE SIGNAL ;
    PORT
      LAYER M3 ;
        RECT  31.86 51.802 31.878 51.84 ;
    END
  END q[318]
  PIN q[319]
    DIRECTION OUTPUT ;
    USE SIGNAL ;
    PORT
      LAYER M5 ;
        RECT  31.968 51.756 31.992 51.84 ;
    END
  END q[319]
  PIN q[31]
    DIRECTION OUTPUT ;
    USE SIGNAL ;
    PORT
      LAYER M5 ;
        RECT  3.648 51.756 3.672 51.84 ;
    END
  END q[31]
  PIN q[320]
    DIRECTION OUTPUT ;
    USE SIGNAL ;
    PORT
      LAYER M3 ;
        RECT  32.076 51.802 32.094 51.84 ;
    END
  END q[320]
  PIN q[321]
    DIRECTION OUTPUT ;
    USE SIGNAL ;
    PORT
      LAYER M5 ;
        RECT  32.16 51.756 32.184 51.84 ;
    END
  END q[321]
  PIN q[322]
    DIRECTION OUTPUT ;
    USE SIGNAL ;
    PORT
      LAYER M3 ;
        RECT  32.256 51.802 32.274 51.84 ;
    END
  END q[322]
  PIN q[323]
    DIRECTION OUTPUT ;
    USE SIGNAL ;
    PORT
      LAYER M5 ;
        RECT  32.352 51.756 32.376 51.84 ;
    END
  END q[323]
  PIN q[324]
    DIRECTION OUTPUT ;
    USE SIGNAL ;
    PORT
      LAYER M3 ;
        RECT  32.436 51.802 32.454 51.84 ;
    END
  END q[324]
  PIN q[325]
    DIRECTION OUTPUT ;
    USE SIGNAL ;
    PORT
      LAYER M5 ;
        RECT  32.544 51.756 32.568 51.84 ;
    END
  END q[325]
  PIN q[326]
    DIRECTION OUTPUT ;
    USE SIGNAL ;
    PORT
      LAYER M3 ;
        RECT  32.652 51.802 32.67 51.84 ;
    END
  END q[326]
  PIN q[327]
    DIRECTION OUTPUT ;
    USE SIGNAL ;
    PORT
      LAYER M5 ;
        RECT  32.736 51.756 32.76 51.84 ;
    END
  END q[327]
  PIN q[328]
    DIRECTION OUTPUT ;
    USE SIGNAL ;
    PORT
      LAYER M3 ;
        RECT  32.832 51.802 32.85 51.84 ;
    END
  END q[328]
  PIN q[329]
    DIRECTION OUTPUT ;
    USE SIGNAL ;
    PORT
      LAYER M5 ;
        RECT  32.928 51.756 32.952 51.84 ;
    END
  END q[329]
  PIN q[32]
    DIRECTION OUTPUT ;
    USE SIGNAL ;
    PORT
      LAYER M3 ;
        RECT  3.744 51.802 3.762 51.84 ;
    END
  END q[32]
  PIN q[330]
    DIRECTION OUTPUT ;
    USE SIGNAL ;
    PORT
      LAYER M3 ;
        RECT  33.048 51.802 33.066 51.84 ;
    END
  END q[330]
  PIN q[331]
    DIRECTION OUTPUT ;
    USE SIGNAL ;
    PORT
      LAYER M5 ;
        RECT  33.12 51.756 33.144 51.84 ;
    END
  END q[331]
  PIN q[332]
    DIRECTION OUTPUT ;
    USE SIGNAL ;
    PORT
      LAYER M3 ;
        RECT  33.228 51.802 33.246 51.84 ;
    END
  END q[332]
  PIN q[333]
    DIRECTION OUTPUT ;
    USE SIGNAL ;
    PORT
      LAYER M5 ;
        RECT  33.312 51.756 33.336 51.84 ;
    END
  END q[333]
  PIN q[334]
    DIRECTION OUTPUT ;
    USE SIGNAL ;
    PORT
      LAYER M3 ;
        RECT  33.444 51.802 33.462 51.84 ;
    END
  END q[334]
  PIN q[335]
    DIRECTION OUTPUT ;
    USE SIGNAL ;
    PORT
      LAYER M5 ;
        RECT  33.552 51.756 33.576 51.84 ;
    END
  END q[335]
  PIN q[336]
    DIRECTION OUTPUT ;
    USE SIGNAL ;
    PORT
      LAYER M3 ;
        RECT  33.624 51.802 33.642 51.84 ;
    END
  END q[336]
  PIN q[337]
    DIRECTION OUTPUT ;
    USE SIGNAL ;
    PORT
      LAYER M5 ;
        RECT  33.744 51.756 33.768 51.84 ;
    END
  END q[337]
  PIN q[338]
    DIRECTION OUTPUT ;
    USE SIGNAL ;
    PORT
      LAYER M3 ;
        RECT  33.84 51.802 33.858 51.84 ;
    END
  END q[338]
  PIN q[339]
    DIRECTION OUTPUT ;
    USE SIGNAL ;
    PORT
      LAYER M5 ;
        RECT  33.936 51.756 33.96 51.84 ;
    END
  END q[339]
  PIN q[33]
    DIRECTION OUTPUT ;
    USE SIGNAL ;
    PORT
      LAYER M5 ;
        RECT  3.84 51.756 3.864 51.84 ;
    END
  END q[33]
  PIN q[340]
    DIRECTION OUTPUT ;
    USE SIGNAL ;
    PORT
      LAYER M3 ;
        RECT  34.02 51.802 34.038 51.84 ;
    END
  END q[340]
  PIN q[341]
    DIRECTION OUTPUT ;
    USE SIGNAL ;
    PORT
      LAYER M5 ;
        RECT  34.128 51.756 34.152 51.84 ;
    END
  END q[341]
  PIN q[342]
    DIRECTION OUTPUT ;
    USE SIGNAL ;
    PORT
      LAYER M3 ;
        RECT  34.236 51.802 34.254 51.84 ;
    END
  END q[342]
  PIN q[343]
    DIRECTION OUTPUT ;
    USE SIGNAL ;
    PORT
      LAYER M5 ;
        RECT  34.32 51.756 34.344 51.84 ;
    END
  END q[343]
  PIN q[344]
    DIRECTION OUTPUT ;
    USE SIGNAL ;
    PORT
      LAYER M3 ;
        RECT  34.416 51.802 34.434 51.84 ;
    END
  END q[344]
  PIN q[345]
    DIRECTION OUTPUT ;
    USE SIGNAL ;
    PORT
      LAYER M5 ;
        RECT  34.512 51.756 34.536 51.84 ;
    END
  END q[345]
  PIN q[346]
    DIRECTION OUTPUT ;
    USE SIGNAL ;
    PORT
      LAYER M3 ;
        RECT  34.632 51.802 34.65 51.84 ;
    END
  END q[346]
  PIN q[347]
    DIRECTION OUTPUT ;
    USE SIGNAL ;
    PORT
      LAYER M5 ;
        RECT  34.704 51.756 34.728 51.84 ;
    END
  END q[347]
  PIN q[348]
    DIRECTION OUTPUT ;
    USE SIGNAL ;
    PORT
      LAYER M3 ;
        RECT  34.812 51.802 34.83 51.84 ;
    END
  END q[348]
  PIN q[349]
    DIRECTION OUTPUT ;
    USE SIGNAL ;
    PORT
      LAYER M5 ;
        RECT  34.896 51.756 34.92 51.84 ;
    END
  END q[349]
  PIN q[34]
    DIRECTION OUTPUT ;
    USE SIGNAL ;
    PORT
      LAYER M3 ;
        RECT  3.924 51.802 3.942 51.84 ;
    END
  END q[34]
  PIN q[350]
    DIRECTION OUTPUT ;
    USE SIGNAL ;
    PORT
      LAYER M3 ;
        RECT  35.028 51.802 35.046 51.84 ;
    END
  END q[350]
  PIN q[351]
    DIRECTION OUTPUT ;
    USE SIGNAL ;
    PORT
      LAYER M5 ;
        RECT  35.088 51.756 35.112 51.84 ;
    END
  END q[351]
  PIN q[352]
    DIRECTION OUTPUT ;
    USE SIGNAL ;
    PORT
      LAYER M3 ;
        RECT  35.208 51.802 35.226 51.84 ;
    END
  END q[352]
  PIN q[353]
    DIRECTION OUTPUT ;
    USE SIGNAL ;
    PORT
      LAYER M5 ;
        RECT  35.28 51.756 35.304 51.84 ;
    END
  END q[353]
  PIN q[354]
    DIRECTION OUTPUT ;
    USE SIGNAL ;
    PORT
      LAYER M3 ;
        RECT  35.388 51.802 35.406 51.84 ;
    END
  END q[354]
  PIN q[355]
    DIRECTION OUTPUT ;
    USE SIGNAL ;
    PORT
      LAYER M5 ;
        RECT  35.52 51.756 35.544 51.84 ;
    END
  END q[355]
  PIN q[356]
    DIRECTION OUTPUT ;
    USE SIGNAL ;
    PORT
      LAYER M3 ;
        RECT  35.604 51.802 35.622 51.84 ;
    END
  END q[356]
  PIN q[357]
    DIRECTION OUTPUT ;
    USE SIGNAL ;
    PORT
      LAYER M5 ;
        RECT  35.712 51.756 35.736 51.84 ;
    END
  END q[357]
  PIN q[358]
    DIRECTION OUTPUT ;
    USE SIGNAL ;
    PORT
      LAYER M3 ;
        RECT  35.784 51.802 35.802 51.84 ;
    END
  END q[358]
  PIN q[359]
    DIRECTION OUTPUT ;
    USE SIGNAL ;
    PORT
      LAYER M5 ;
        RECT  35.904 51.756 35.928 51.84 ;
    END
  END q[359]
  PIN q[35]
    DIRECTION OUTPUT ;
    USE SIGNAL ;
    PORT
      LAYER M5 ;
        RECT  4.032 51.756 4.056 51.84 ;
    END
  END q[35]
  PIN q[360]
    DIRECTION OUTPUT ;
    USE SIGNAL ;
    PORT
      LAYER M3 ;
        RECT  36 51.802 36.018 51.84 ;
    END
  END q[360]
  PIN q[361]
    DIRECTION OUTPUT ;
    USE SIGNAL ;
    PORT
      LAYER M5 ;
        RECT  36.096 51.756 36.12 51.84 ;
    END
  END q[361]
  PIN q[362]
    DIRECTION OUTPUT ;
    USE SIGNAL ;
    PORT
      LAYER M3 ;
        RECT  36.18 51.802 36.198 51.84 ;
    END
  END q[362]
  PIN q[363]
    DIRECTION OUTPUT ;
    USE SIGNAL ;
    PORT
      LAYER M5 ;
        RECT  36.288 51.756 36.312 51.84 ;
    END
  END q[363]
  PIN q[364]
    DIRECTION OUTPUT ;
    USE SIGNAL ;
    PORT
      LAYER M3 ;
        RECT  36.396 51.802 36.414 51.84 ;
    END
  END q[364]
  PIN q[365]
    DIRECTION OUTPUT ;
    USE SIGNAL ;
    PORT
      LAYER M5 ;
        RECT  36.48 51.756 36.504 51.84 ;
    END
  END q[365]
  PIN q[366]
    DIRECTION OUTPUT ;
    USE SIGNAL ;
    PORT
      LAYER M3 ;
        RECT  36.576 51.802 36.594 51.84 ;
    END
  END q[366]
  PIN q[367]
    DIRECTION OUTPUT ;
    USE SIGNAL ;
    PORT
      LAYER M5 ;
        RECT  36.672 51.756 36.696 51.84 ;
    END
  END q[367]
  PIN q[368]
    DIRECTION OUTPUT ;
    USE SIGNAL ;
    PORT
      LAYER M3 ;
        RECT  36.792 51.802 36.81 51.84 ;
    END
  END q[368]
  PIN q[369]
    DIRECTION OUTPUT ;
    USE SIGNAL ;
    PORT
      LAYER M5 ;
        RECT  36.864 51.756 36.888 51.84 ;
    END
  END q[369]
  PIN q[36]
    DIRECTION OUTPUT ;
    USE SIGNAL ;
    PORT
      LAYER M3 ;
        RECT  4.14 51.802 4.158 51.84 ;
    END
  END q[36]
  PIN q[370]
    DIRECTION OUTPUT ;
    USE SIGNAL ;
    PORT
      LAYER M3 ;
        RECT  36.972 51.802 36.99 51.84 ;
    END
  END q[370]
  PIN q[371]
    DIRECTION OUTPUT ;
    USE SIGNAL ;
    PORT
      LAYER M5 ;
        RECT  37.056 51.756 37.08 51.84 ;
    END
  END q[371]
  PIN q[372]
    DIRECTION OUTPUT ;
    USE SIGNAL ;
    PORT
      LAYER M3 ;
        RECT  37.188 51.802 37.206 51.84 ;
    END
  END q[372]
  PIN q[373]
    DIRECTION OUTPUT ;
    USE SIGNAL ;
    PORT
      LAYER M5 ;
        RECT  37.248 51.756 37.272 51.84 ;
    END
  END q[373]
  PIN q[374]
    DIRECTION OUTPUT ;
    USE SIGNAL ;
    PORT
      LAYER M3 ;
        RECT  37.368 51.802 37.386 51.84 ;
    END
  END q[374]
  PIN q[375]
    DIRECTION OUTPUT ;
    USE SIGNAL ;
    PORT
      LAYER M5 ;
        RECT  37.488 51.756 37.512 51.84 ;
    END
  END q[375]
  PIN q[376]
    DIRECTION OUTPUT ;
    USE SIGNAL ;
    PORT
      LAYER M3 ;
        RECT  37.584 51.802 37.602 51.84 ;
    END
  END q[376]
  PIN q[377]
    DIRECTION OUTPUT ;
    USE SIGNAL ;
    PORT
      LAYER M5 ;
        RECT  37.68 51.756 37.704 51.84 ;
    END
  END q[377]
  PIN q[378]
    DIRECTION OUTPUT ;
    USE SIGNAL ;
    PORT
      LAYER M3 ;
        RECT  37.764 51.802 37.782 51.84 ;
    END
  END q[378]
  PIN q[379]
    DIRECTION OUTPUT ;
    USE SIGNAL ;
    PORT
      LAYER M5 ;
        RECT  37.872 51.756 37.896 51.84 ;
    END
  END q[379]
  PIN q[37]
    DIRECTION OUTPUT ;
    USE SIGNAL ;
    PORT
      LAYER M5 ;
        RECT  4.224 51.756 4.248 51.84 ;
    END
  END q[37]
  PIN q[380]
    DIRECTION OUTPUT ;
    USE SIGNAL ;
    PORT
      LAYER M3 ;
        RECT  37.98 51.802 37.998 51.84 ;
    END
  END q[380]
  PIN q[381]
    DIRECTION OUTPUT ;
    USE SIGNAL ;
    PORT
      LAYER M5 ;
        RECT  38.064 51.756 38.088 51.84 ;
    END
  END q[381]
  PIN q[382]
    DIRECTION OUTPUT ;
    USE SIGNAL ;
    PORT
      LAYER M3 ;
        RECT  38.16 51.802 38.178 51.84 ;
    END
  END q[382]
  PIN q[383]
    DIRECTION OUTPUT ;
    USE SIGNAL ;
    PORT
      LAYER M5 ;
        RECT  38.256 51.756 38.28 51.84 ;
    END
  END q[383]
  PIN q[384]
    DIRECTION OUTPUT ;
    USE SIGNAL ;
    PORT
      LAYER M3 ;
        RECT  38.34 51.802 38.358 51.84 ;
    END
  END q[384]
  PIN q[385]
    DIRECTION OUTPUT ;
    USE SIGNAL ;
    PORT
      LAYER M5 ;
        RECT  38.448 51.756 38.472 51.84 ;
    END
  END q[385]
  PIN q[386]
    DIRECTION OUTPUT ;
    USE SIGNAL ;
    PORT
      LAYER M3 ;
        RECT  38.556 51.802 38.574 51.84 ;
    END
  END q[386]
  PIN q[387]
    DIRECTION OUTPUT ;
    USE SIGNAL ;
    PORT
      LAYER M5 ;
        RECT  38.64 51.756 38.664 51.84 ;
    END
  END q[387]
  PIN q[388]
    DIRECTION OUTPUT ;
    USE SIGNAL ;
    PORT
      LAYER M3 ;
        RECT  38.736 51.802 38.754 51.84 ;
    END
  END q[388]
  PIN q[389]
    DIRECTION OUTPUT ;
    USE SIGNAL ;
    PORT
      LAYER M5 ;
        RECT  38.832 51.756 38.856 51.84 ;
    END
  END q[389]
  PIN q[38]
    DIRECTION OUTPUT ;
    USE SIGNAL ;
    PORT
      LAYER M3 ;
        RECT  4.32 51.802 4.338 51.84 ;
    END
  END q[38]
  PIN q[390]
    DIRECTION OUTPUT ;
    USE SIGNAL ;
    PORT
      LAYER M3 ;
        RECT  38.952 51.802 38.97 51.84 ;
    END
  END q[390]
  PIN q[391]
    DIRECTION OUTPUT ;
    USE SIGNAL ;
    PORT
      LAYER M5 ;
        RECT  39.024 51.756 39.048 51.84 ;
    END
  END q[391]
  PIN q[392]
    DIRECTION OUTPUT ;
    USE SIGNAL ;
    PORT
      LAYER M3 ;
        RECT  39.132 51.802 39.15 51.84 ;
    END
  END q[392]
  PIN q[393]
    DIRECTION OUTPUT ;
    USE SIGNAL ;
    PORT
      LAYER M5 ;
        RECT  39.216 51.756 39.24 51.84 ;
    END
  END q[393]
  PIN q[394]
    DIRECTION OUTPUT ;
    USE SIGNAL ;
    PORT
      LAYER M3 ;
        RECT  39.348 51.802 39.366 51.84 ;
    END
  END q[394]
  PIN q[395]
    DIRECTION OUTPUT ;
    USE SIGNAL ;
    PORT
      LAYER M5 ;
        RECT  39.456 51.756 39.48 51.84 ;
    END
  END q[395]
  PIN q[396]
    DIRECTION OUTPUT ;
    USE SIGNAL ;
    PORT
      LAYER M3 ;
        RECT  39.528 51.802 39.546 51.84 ;
    END
  END q[396]
  PIN q[397]
    DIRECTION OUTPUT ;
    USE SIGNAL ;
    PORT
      LAYER M5 ;
        RECT  39.648 51.756 39.672 51.84 ;
    END
  END q[397]
  PIN q[398]
    DIRECTION OUTPUT ;
    USE SIGNAL ;
    PORT
      LAYER M3 ;
        RECT  39.744 51.802 39.762 51.84 ;
    END
  END q[398]
  PIN q[399]
    DIRECTION OUTPUT ;
    USE SIGNAL ;
    PORT
      LAYER M5 ;
        RECT  39.84 51.756 39.864 51.84 ;
    END
  END q[399]
  PIN q[39]
    DIRECTION OUTPUT ;
    USE SIGNAL ;
    PORT
      LAYER M5 ;
        RECT  4.416 51.756 4.44 51.84 ;
    END
  END q[39]
  PIN q[3]
    DIRECTION OUTPUT ;
    USE SIGNAL ;
    PORT
      LAYER M5 ;
        RECT  0.864 51.756 0.888 51.84 ;
    END
  END q[3]
  PIN q[400]
    DIRECTION OUTPUT ;
    USE SIGNAL ;
    PORT
      LAYER M3 ;
        RECT  39.924 51.802 39.942 51.84 ;
    END
  END q[400]
  PIN q[401]
    DIRECTION OUTPUT ;
    USE SIGNAL ;
    PORT
      LAYER M5 ;
        RECT  40.032 51.756 40.056 51.84 ;
    END
  END q[401]
  PIN q[402]
    DIRECTION OUTPUT ;
    USE SIGNAL ;
    PORT
      LAYER M3 ;
        RECT  40.14 51.802 40.158 51.84 ;
    END
  END q[402]
  PIN q[403]
    DIRECTION OUTPUT ;
    USE SIGNAL ;
    PORT
      LAYER M5 ;
        RECT  40.224 51.756 40.248 51.84 ;
    END
  END q[403]
  PIN q[404]
    DIRECTION OUTPUT ;
    USE SIGNAL ;
    PORT
      LAYER M3 ;
        RECT  40.32 51.802 40.338 51.84 ;
    END
  END q[404]
  PIN q[405]
    DIRECTION OUTPUT ;
    USE SIGNAL ;
    PORT
      LAYER M5 ;
        RECT  40.416 51.756 40.44 51.84 ;
    END
  END q[405]
  PIN q[406]
    DIRECTION OUTPUT ;
    USE SIGNAL ;
    PORT
      LAYER M3 ;
        RECT  40.536 51.802 40.554 51.84 ;
    END
  END q[406]
  PIN q[407]
    DIRECTION OUTPUT ;
    USE SIGNAL ;
    PORT
      LAYER M5 ;
        RECT  40.608 51.756 40.632 51.84 ;
    END
  END q[407]
  PIN q[408]
    DIRECTION OUTPUT ;
    USE SIGNAL ;
    PORT
      LAYER M3 ;
        RECT  40.716 51.802 40.734 51.84 ;
    END
  END q[408]
  PIN q[409]
    DIRECTION OUTPUT ;
    USE SIGNAL ;
    PORT
      LAYER M5 ;
        RECT  40.8 51.756 40.824 51.84 ;
    END
  END q[409]
  PIN q[40]
    DIRECTION OUTPUT ;
    USE SIGNAL ;
    PORT
      LAYER M3 ;
        RECT  4.5 51.802 4.518 51.84 ;
    END
  END q[40]
  PIN q[410]
    DIRECTION OUTPUT ;
    USE SIGNAL ;
    PORT
      LAYER M3 ;
        RECT  40.896 51.802 40.914 51.84 ;
    END
  END q[410]
  PIN q[411]
    DIRECTION OUTPUT ;
    USE SIGNAL ;
    PORT
      LAYER M5 ;
        RECT  40.992 51.756 41.016 51.84 ;
    END
  END q[411]
  PIN q[412]
    DIRECTION OUTPUT ;
    USE SIGNAL ;
    PORT
      LAYER M3 ;
        RECT  41.112 51.802 41.13 51.84 ;
    END
  END q[412]
  PIN q[413]
    DIRECTION OUTPUT ;
    USE SIGNAL ;
    PORT
      LAYER M5 ;
        RECT  41.184 51.756 41.208 51.84 ;
    END
  END q[413]
  PIN q[414]
    DIRECTION OUTPUT ;
    USE SIGNAL ;
    PORT
      LAYER M3 ;
        RECT  41.292 51.802 41.31 51.84 ;
    END
  END q[414]
  PIN q[415]
    DIRECTION OUTPUT ;
    USE SIGNAL ;
    PORT
      LAYER M5 ;
        RECT  41.424 51.756 41.448 51.84 ;
    END
  END q[415]
  PIN q[416]
    DIRECTION OUTPUT ;
    USE SIGNAL ;
    PORT
      LAYER M3 ;
        RECT  41.508 51.802 41.526 51.84 ;
    END
  END q[416]
  PIN q[417]
    DIRECTION OUTPUT ;
    USE SIGNAL ;
    PORT
      LAYER M5 ;
        RECT  41.616 51.756 41.64 51.84 ;
    END
  END q[417]
  PIN q[418]
    DIRECTION OUTPUT ;
    USE SIGNAL ;
    PORT
      LAYER M3 ;
        RECT  41.688 51.802 41.706 51.84 ;
    END
  END q[418]
  PIN q[419]
    DIRECTION OUTPUT ;
    USE SIGNAL ;
    PORT
      LAYER M5 ;
        RECT  41.808 51.756 41.832 51.84 ;
    END
  END q[419]
  PIN q[41]
    DIRECTION OUTPUT ;
    USE SIGNAL ;
    PORT
      LAYER M5 ;
        RECT  4.608 51.756 4.632 51.84 ;
    END
  END q[41]
  PIN q[420]
    DIRECTION OUTPUT ;
    USE SIGNAL ;
    PORT
      LAYER M3 ;
        RECT  41.904 51.802 41.922 51.84 ;
    END
  END q[420]
  PIN q[421]
    DIRECTION OUTPUT ;
    USE SIGNAL ;
    PORT
      LAYER M5 ;
        RECT  42 51.756 42.024 51.84 ;
    END
  END q[421]
  PIN q[422]
    DIRECTION OUTPUT ;
    USE SIGNAL ;
    PORT
      LAYER M3 ;
        RECT  42.084 51.802 42.102 51.84 ;
    END
  END q[422]
  PIN q[423]
    DIRECTION OUTPUT ;
    USE SIGNAL ;
    PORT
      LAYER M5 ;
        RECT  42.192 51.756 42.216 51.84 ;
    END
  END q[423]
  PIN q[424]
    DIRECTION OUTPUT ;
    USE SIGNAL ;
    PORT
      LAYER M3 ;
        RECT  42.3 51.802 42.318 51.84 ;
    END
  END q[424]
  PIN q[425]
    DIRECTION OUTPUT ;
    USE SIGNAL ;
    PORT
      LAYER M5 ;
        RECT  42.384 51.756 42.408 51.84 ;
    END
  END q[425]
  PIN q[426]
    DIRECTION OUTPUT ;
    USE SIGNAL ;
    PORT
      LAYER M3 ;
        RECT  42.48 51.802 42.498 51.84 ;
    END
  END q[426]
  PIN q[427]
    DIRECTION OUTPUT ;
    USE SIGNAL ;
    PORT
      LAYER M5 ;
        RECT  42.576 51.756 42.6 51.84 ;
    END
  END q[427]
  PIN q[428]
    DIRECTION OUTPUT ;
    USE SIGNAL ;
    PORT
      LAYER M3 ;
        RECT  42.696 51.802 42.714 51.84 ;
    END
  END q[428]
  PIN q[429]
    DIRECTION OUTPUT ;
    USE SIGNAL ;
    PORT
      LAYER M5 ;
        RECT  42.768 51.756 42.792 51.84 ;
    END
  END q[429]
  PIN q[42]
    DIRECTION OUTPUT ;
    USE SIGNAL ;
    PORT
      LAYER M3 ;
        RECT  4.716 51.802 4.734 51.84 ;
    END
  END q[42]
  PIN q[430]
    DIRECTION OUTPUT ;
    USE SIGNAL ;
    PORT
      LAYER M3 ;
        RECT  42.876 51.802 42.894 51.84 ;
    END
  END q[430]
  PIN q[431]
    DIRECTION OUTPUT ;
    USE SIGNAL ;
    PORT
      LAYER M5 ;
        RECT  42.96 51.756 42.984 51.84 ;
    END
  END q[431]
  PIN q[432]
    DIRECTION OUTPUT ;
    USE SIGNAL ;
    PORT
      LAYER M3 ;
        RECT  43.092 51.802 43.11 51.84 ;
    END
  END q[432]
  PIN q[433]
    DIRECTION OUTPUT ;
    USE SIGNAL ;
    PORT
      LAYER M5 ;
        RECT  43.152 51.756 43.176 51.84 ;
    END
  END q[433]
  PIN q[434]
    DIRECTION OUTPUT ;
    USE SIGNAL ;
    PORT
      LAYER M3 ;
        RECT  43.272 51.802 43.29 51.84 ;
    END
  END q[434]
  PIN q[435]
    DIRECTION OUTPUT ;
    USE SIGNAL ;
    PORT
      LAYER M5 ;
        RECT  43.392 51.756 43.416 51.84 ;
    END
  END q[435]
  PIN q[436]
    DIRECTION OUTPUT ;
    USE SIGNAL ;
    PORT
      LAYER M3 ;
        RECT  43.488 51.802 43.506 51.84 ;
    END
  END q[436]
  PIN q[437]
    DIRECTION OUTPUT ;
    USE SIGNAL ;
    PORT
      LAYER M5 ;
        RECT  43.584 51.756 43.608 51.84 ;
    END
  END q[437]
  PIN q[438]
    DIRECTION OUTPUT ;
    USE SIGNAL ;
    PORT
      LAYER M3 ;
        RECT  43.668 51.802 43.686 51.84 ;
    END
  END q[438]
  PIN q[439]
    DIRECTION OUTPUT ;
    USE SIGNAL ;
    PORT
      LAYER M5 ;
        RECT  43.776 51.756 43.8 51.84 ;
    END
  END q[439]
  PIN q[43]
    DIRECTION OUTPUT ;
    USE SIGNAL ;
    PORT
      LAYER M5 ;
        RECT  4.8 51.756 4.824 51.84 ;
    END
  END q[43]
  PIN q[440]
    DIRECTION OUTPUT ;
    USE SIGNAL ;
    PORT
      LAYER M3 ;
        RECT  43.848 51.802 43.866 51.84 ;
    END
  END q[440]
  PIN q[441]
    DIRECTION OUTPUT ;
    USE SIGNAL ;
    PORT
      LAYER M5 ;
        RECT  43.968 51.756 43.992 51.84 ;
    END
  END q[441]
  PIN q[442]
    DIRECTION OUTPUT ;
    USE SIGNAL ;
    PORT
      LAYER M3 ;
        RECT  44.064 51.802 44.082 51.84 ;
    END
  END q[442]
  PIN q[443]
    DIRECTION OUTPUT ;
    USE SIGNAL ;
    PORT
      LAYER M5 ;
        RECT  44.16 51.756 44.184 51.84 ;
    END
  END q[443]
  PIN q[444]
    DIRECTION OUTPUT ;
    USE SIGNAL ;
    PORT
      LAYER M3 ;
        RECT  44.244 51.802 44.262 51.84 ;
    END
  END q[444]
  PIN q[445]
    DIRECTION OUTPUT ;
    USE SIGNAL ;
    PORT
      LAYER M5 ;
        RECT  44.352 51.756 44.376 51.84 ;
    END
  END q[445]
  PIN q[446]
    DIRECTION OUTPUT ;
    USE SIGNAL ;
    PORT
      LAYER M3 ;
        RECT  44.46 51.802 44.478 51.84 ;
    END
  END q[446]
  PIN q[447]
    DIRECTION OUTPUT ;
    USE SIGNAL ;
    PORT
      LAYER M5 ;
        RECT  44.544 51.756 44.568 51.84 ;
    END
  END q[447]
  PIN q[448]
    DIRECTION OUTPUT ;
    USE SIGNAL ;
    PORT
      LAYER M3 ;
        RECT  44.64 51.802 44.658 51.84 ;
    END
  END q[448]
  PIN q[449]
    DIRECTION OUTPUT ;
    USE SIGNAL ;
    PORT
      LAYER M5 ;
        RECT  44.736 51.756 44.76 51.84 ;
    END
  END q[449]
  PIN q[44]
    DIRECTION OUTPUT ;
    USE SIGNAL ;
    PORT
      LAYER M3 ;
        RECT  4.896 51.802 4.914 51.84 ;
    END
  END q[44]
  PIN q[450]
    DIRECTION OUTPUT ;
    USE SIGNAL ;
    PORT
      LAYER M3 ;
        RECT  44.856 51.802 44.874 51.84 ;
    END
  END q[450]
  PIN q[451]
    DIRECTION OUTPUT ;
    USE SIGNAL ;
    PORT
      LAYER M5 ;
        RECT  44.928 51.756 44.952 51.84 ;
    END
  END q[451]
  PIN q[452]
    DIRECTION OUTPUT ;
    USE SIGNAL ;
    PORT
      LAYER M3 ;
        RECT  45.036 51.802 45.054 51.84 ;
    END
  END q[452]
  PIN q[453]
    DIRECTION OUTPUT ;
    USE SIGNAL ;
    PORT
      LAYER M5 ;
        RECT  45.12 51.756 45.144 51.84 ;
    END
  END q[453]
  PIN q[454]
    DIRECTION OUTPUT ;
    USE SIGNAL ;
    PORT
      LAYER M3 ;
        RECT  45.252 51.802 45.27 51.84 ;
    END
  END q[454]
  PIN q[455]
    DIRECTION OUTPUT ;
    USE SIGNAL ;
    PORT
      LAYER M5 ;
        RECT  45.36 51.756 45.384 51.84 ;
    END
  END q[455]
  PIN q[456]
    DIRECTION OUTPUT ;
    USE SIGNAL ;
    PORT
      LAYER M3 ;
        RECT  45.432 51.802 45.45 51.84 ;
    END
  END q[456]
  PIN q[457]
    DIRECTION OUTPUT ;
    USE SIGNAL ;
    PORT
      LAYER M5 ;
        RECT  45.552 51.756 45.576 51.84 ;
    END
  END q[457]
  PIN q[458]
    DIRECTION OUTPUT ;
    USE SIGNAL ;
    PORT
      LAYER M3 ;
        RECT  45.648 51.802 45.666 51.84 ;
    END
  END q[458]
  PIN q[459]
    DIRECTION OUTPUT ;
    USE SIGNAL ;
    PORT
      LAYER M5 ;
        RECT  45.744 51.756 45.768 51.84 ;
    END
  END q[459]
  PIN q[45]
    DIRECTION OUTPUT ;
    USE SIGNAL ;
    PORT
      LAYER M5 ;
        RECT  4.992 51.756 5.016 51.84 ;
    END
  END q[45]
  PIN q[460]
    DIRECTION OUTPUT ;
    USE SIGNAL ;
    PORT
      LAYER M3 ;
        RECT  45.828 51.802 45.846 51.84 ;
    END
  END q[460]
  PIN q[461]
    DIRECTION OUTPUT ;
    USE SIGNAL ;
    PORT
      LAYER M5 ;
        RECT  45.936 51.756 45.96 51.84 ;
    END
  END q[461]
  PIN q[462]
    DIRECTION OUTPUT ;
    USE SIGNAL ;
    PORT
      LAYER M3 ;
        RECT  46.044 51.802 46.062 51.84 ;
    END
  END q[462]
  PIN q[463]
    DIRECTION OUTPUT ;
    USE SIGNAL ;
    PORT
      LAYER M5 ;
        RECT  46.128 51.756 46.152 51.84 ;
    END
  END q[463]
  PIN q[464]
    DIRECTION OUTPUT ;
    USE SIGNAL ;
    PORT
      LAYER M3 ;
        RECT  46.224 51.802 46.242 51.84 ;
    END
  END q[464]
  PIN q[465]
    DIRECTION OUTPUT ;
    USE SIGNAL ;
    PORT
      LAYER M5 ;
        RECT  46.32 51.756 46.344 51.84 ;
    END
  END q[465]
  PIN q[466]
    DIRECTION OUTPUT ;
    USE SIGNAL ;
    PORT
      LAYER M3 ;
        RECT  46.44 51.802 46.458 51.84 ;
    END
  END q[466]
  PIN q[467]
    DIRECTION OUTPUT ;
    USE SIGNAL ;
    PORT
      LAYER M5 ;
        RECT  46.512 51.756 46.536 51.84 ;
    END
  END q[467]
  PIN q[468]
    DIRECTION OUTPUT ;
    USE SIGNAL ;
    PORT
      LAYER M3 ;
        RECT  46.62 51.802 46.638 51.84 ;
    END
  END q[468]
  PIN q[469]
    DIRECTION OUTPUT ;
    USE SIGNAL ;
    PORT
      LAYER M5 ;
        RECT  46.704 51.756 46.728 51.84 ;
    END
  END q[469]
  PIN q[46]
    DIRECTION OUTPUT ;
    USE SIGNAL ;
    PORT
      LAYER M3 ;
        RECT  5.112 51.802 5.13 51.84 ;
    END
  END q[46]
  PIN q[470]
    DIRECTION OUTPUT ;
    USE SIGNAL ;
    PORT
      LAYER M3 ;
        RECT  46.8 51.802 46.818 51.84 ;
    END
  END q[470]
  PIN q[471]
    DIRECTION OUTPUT ;
    USE SIGNAL ;
    PORT
      LAYER M5 ;
        RECT  46.896 51.756 46.92 51.84 ;
    END
  END q[471]
  PIN q[472]
    DIRECTION OUTPUT ;
    USE SIGNAL ;
    PORT
      LAYER M3 ;
        RECT  47.016 51.802 47.034 51.84 ;
    END
  END q[472]
  PIN q[473]
    DIRECTION OUTPUT ;
    USE SIGNAL ;
    PORT
      LAYER M5 ;
        RECT  47.088 51.756 47.112 51.84 ;
    END
  END q[473]
  PIN q[474]
    DIRECTION OUTPUT ;
    USE SIGNAL ;
    PORT
      LAYER M3 ;
        RECT  47.196 51.802 47.214 51.84 ;
    END
  END q[474]
  PIN q[475]
    DIRECTION OUTPUT ;
    USE SIGNAL ;
    PORT
      LAYER M5 ;
        RECT  47.328 51.756 47.352 51.84 ;
    END
  END q[475]
  PIN q[476]
    DIRECTION OUTPUT ;
    USE SIGNAL ;
    PORT
      LAYER M3 ;
        RECT  47.412 51.802 47.43 51.84 ;
    END
  END q[476]
  PIN q[477]
    DIRECTION OUTPUT ;
    USE SIGNAL ;
    PORT
      LAYER M5 ;
        RECT  47.52 51.756 47.544 51.84 ;
    END
  END q[477]
  PIN q[478]
    DIRECTION OUTPUT ;
    USE SIGNAL ;
    PORT
      LAYER M3 ;
        RECT  47.592 51.802 47.61 51.84 ;
    END
  END q[478]
  PIN q[479]
    DIRECTION OUTPUT ;
    USE SIGNAL ;
    PORT
      LAYER M5 ;
        RECT  47.712 51.756 47.736 51.84 ;
    END
  END q[479]
  PIN q[47]
    DIRECTION OUTPUT ;
    USE SIGNAL ;
    PORT
      LAYER M5 ;
        RECT  5.184 51.756 5.208 51.84 ;
    END
  END q[47]
  PIN q[480]
    DIRECTION OUTPUT ;
    USE SIGNAL ;
    PORT
      LAYER M3 ;
        RECT  47.808 51.802 47.826 51.84 ;
    END
  END q[480]
  PIN q[481]
    DIRECTION OUTPUT ;
    USE SIGNAL ;
    PORT
      LAYER M5 ;
        RECT  47.904 51.756 47.928 51.84 ;
    END
  END q[481]
  PIN q[482]
    DIRECTION OUTPUT ;
    USE SIGNAL ;
    PORT
      LAYER M3 ;
        RECT  47.988 51.802 48.006 51.84 ;
    END
  END q[482]
  PIN q[483]
    DIRECTION OUTPUT ;
    USE SIGNAL ;
    PORT
      LAYER M5 ;
        RECT  48.096 51.756 48.12 51.84 ;
    END
  END q[483]
  PIN q[484]
    DIRECTION OUTPUT ;
    USE SIGNAL ;
    PORT
      LAYER M3 ;
        RECT  48.204 51.802 48.222 51.84 ;
    END
  END q[484]
  PIN q[485]
    DIRECTION OUTPUT ;
    USE SIGNAL ;
    PORT
      LAYER M5 ;
        RECT  48.288 51.756 48.312 51.84 ;
    END
  END q[485]
  PIN q[486]
    DIRECTION OUTPUT ;
    USE SIGNAL ;
    PORT
      LAYER M3 ;
        RECT  48.384 51.802 48.402 51.84 ;
    END
  END q[486]
  PIN q[487]
    DIRECTION OUTPUT ;
    USE SIGNAL ;
    PORT
      LAYER M5 ;
        RECT  48.48 51.756 48.504 51.84 ;
    END
  END q[487]
  PIN q[488]
    DIRECTION OUTPUT ;
    USE SIGNAL ;
    PORT
      LAYER M3 ;
        RECT  48.6 51.802 48.618 51.84 ;
    END
  END q[488]
  PIN q[489]
    DIRECTION OUTPUT ;
    USE SIGNAL ;
    PORT
      LAYER M5 ;
        RECT  48.672 51.756 48.696 51.84 ;
    END
  END q[489]
  PIN q[48]
    DIRECTION OUTPUT ;
    USE SIGNAL ;
    PORT
      LAYER M3 ;
        RECT  5.292 51.802 5.31 51.84 ;
    END
  END q[48]
  PIN q[490]
    DIRECTION OUTPUT ;
    USE SIGNAL ;
    PORT
      LAYER M3 ;
        RECT  48.78 51.802 48.798 51.84 ;
    END
  END q[490]
  PIN q[491]
    DIRECTION OUTPUT ;
    USE SIGNAL ;
    PORT
      LAYER M5 ;
        RECT  48.864 51.756 48.888 51.84 ;
    END
  END q[491]
  PIN q[492]
    DIRECTION OUTPUT ;
    USE SIGNAL ;
    PORT
      LAYER M3 ;
        RECT  48.996 51.802 49.014 51.84 ;
    END
  END q[492]
  PIN q[493]
    DIRECTION OUTPUT ;
    USE SIGNAL ;
    PORT
      LAYER M5 ;
        RECT  49.056 51.756 49.08 51.84 ;
    END
  END q[493]
  PIN q[494]
    DIRECTION OUTPUT ;
    USE SIGNAL ;
    PORT
      LAYER M3 ;
        RECT  49.176 51.802 49.194 51.84 ;
    END
  END q[494]
  PIN q[495]
    DIRECTION OUTPUT ;
    USE SIGNAL ;
    PORT
      LAYER M5 ;
        RECT  49.248 51.756 49.272 51.84 ;
    END
  END q[495]
  PIN q[496]
    DIRECTION OUTPUT ;
    USE SIGNAL ;
    PORT
      LAYER M3 ;
        RECT  49.356 51.802 49.374 51.84 ;
    END
  END q[496]
  PIN q[497]
    DIRECTION OUTPUT ;
    USE SIGNAL ;
    PORT
      LAYER M5 ;
        RECT  49.488 51.756 49.512 51.84 ;
    END
  END q[497]
  PIN q[498]
    DIRECTION OUTPUT ;
    USE SIGNAL ;
    PORT
      LAYER M3 ;
        RECT  49.572 51.802 49.59 51.84 ;
    END
  END q[498]
  PIN q[499]
    DIRECTION OUTPUT ;
    USE SIGNAL ;
    PORT
      LAYER M5 ;
        RECT  49.68 51.756 49.704 51.84 ;
    END
  END q[499]
  PIN q[49]
    DIRECTION OUTPUT ;
    USE SIGNAL ;
    PORT
      LAYER M5 ;
        RECT  5.376 51.756 5.4 51.84 ;
    END
  END q[49]
  PIN q[4]
    DIRECTION OUTPUT ;
    USE SIGNAL ;
    PORT
      LAYER M3 ;
        RECT  0.972 51.802 0.99 51.84 ;
    END
  END q[4]
  PIN q[500]
    DIRECTION OUTPUT ;
    USE SIGNAL ;
    PORT
      LAYER M3 ;
        RECT  49.752 51.802 49.77 51.84 ;
    END
  END q[500]
  PIN q[501]
    DIRECTION OUTPUT ;
    USE SIGNAL ;
    PORT
      LAYER M5 ;
        RECT  49.872 51.756 49.896 51.84 ;
    END
  END q[501]
  PIN q[502]
    DIRECTION OUTPUT ;
    USE SIGNAL ;
    PORT
      LAYER M3 ;
        RECT  49.968 51.802 49.986 51.84 ;
    END
  END q[502]
  PIN q[503]
    DIRECTION OUTPUT ;
    USE SIGNAL ;
    PORT
      LAYER M5 ;
        RECT  50.064 51.756 50.088 51.84 ;
    END
  END q[503]
  PIN q[504]
    DIRECTION OUTPUT ;
    USE SIGNAL ;
    PORT
      LAYER M3 ;
        RECT  50.148 51.802 50.166 51.84 ;
    END
  END q[504]
  PIN q[505]
    DIRECTION OUTPUT ;
    USE SIGNAL ;
    PORT
      LAYER M5 ;
        RECT  50.256 51.756 50.28 51.84 ;
    END
  END q[505]
  PIN q[506]
    DIRECTION OUTPUT ;
    USE SIGNAL ;
    PORT
      LAYER M3 ;
        RECT  50.364 51.802 50.382 51.84 ;
    END
  END q[506]
  PIN q[507]
    DIRECTION OUTPUT ;
    USE SIGNAL ;
    PORT
      LAYER M5 ;
        RECT  50.448 51.756 50.472 51.84 ;
    END
  END q[507]
  PIN q[508]
    DIRECTION OUTPUT ;
    USE SIGNAL ;
    PORT
      LAYER M3 ;
        RECT  50.544 51.802 50.562 51.84 ;
    END
  END q[508]
  PIN q[509]
    DIRECTION OUTPUT ;
    USE SIGNAL ;
    PORT
      LAYER M5 ;
        RECT  50.64 51.756 50.664 51.84 ;
    END
  END q[509]
  PIN q[50]
    DIRECTION OUTPUT ;
    USE SIGNAL ;
    PORT
      LAYER M3 ;
        RECT  5.508 51.802 5.526 51.84 ;
    END
  END q[50]
  PIN q[510]
    DIRECTION OUTPUT ;
    USE SIGNAL ;
    PORT
      LAYER M3 ;
        RECT  50.76 51.802 50.778 51.84 ;
    END
  END q[510]
  PIN q[511]
    DIRECTION OUTPUT ;
    USE SIGNAL ;
    PORT
      LAYER M5 ;
        RECT  50.832 51.756 50.856 51.84 ;
    END
  END q[511]
  PIN q[512]
    DIRECTION OUTPUT ;
    USE SIGNAL ;
    PORT
      LAYER M3 ;
        RECT  50.94 51.802 50.958 51.84 ;
    END
  END q[512]
  PIN q[513]
    DIRECTION OUTPUT ;
    USE SIGNAL ;
    PORT
      LAYER M5 ;
        RECT  51.024 51.756 51.048 51.84 ;
    END
  END q[513]
  PIN q[514]
    DIRECTION OUTPUT ;
    USE SIGNAL ;
    PORT
      LAYER M3 ;
        RECT  51.156 51.802 51.174 51.84 ;
    END
  END q[514]
  PIN q[515]
    DIRECTION OUTPUT ;
    USE SIGNAL ;
    PORT
      LAYER M5 ;
        RECT  51.216 51.756 51.24 51.84 ;
    END
  END q[515]
  PIN q[51]
    DIRECTION OUTPUT ;
    USE SIGNAL ;
    PORT
      LAYER M5 ;
        RECT  5.616 51.756 5.64 51.84 ;
    END
  END q[51]
  PIN q[52]
    DIRECTION OUTPUT ;
    USE SIGNAL ;
    PORT
      LAYER M3 ;
        RECT  5.688 51.802 5.706 51.84 ;
    END
  END q[52]
  PIN q[53]
    DIRECTION OUTPUT ;
    USE SIGNAL ;
    PORT
      LAYER M5 ;
        RECT  5.808 51.756 5.832 51.84 ;
    END
  END q[53]
  PIN q[54]
    DIRECTION OUTPUT ;
    USE SIGNAL ;
    PORT
      LAYER M3 ;
        RECT  5.904 51.802 5.922 51.84 ;
    END
  END q[54]
  PIN q[55]
    DIRECTION OUTPUT ;
    USE SIGNAL ;
    PORT
      LAYER M5 ;
        RECT  6 51.756 6.024 51.84 ;
    END
  END q[55]
  PIN q[56]
    DIRECTION OUTPUT ;
    USE SIGNAL ;
    PORT
      LAYER M3 ;
        RECT  6.084 51.802 6.102 51.84 ;
    END
  END q[56]
  PIN q[57]
    DIRECTION OUTPUT ;
    USE SIGNAL ;
    PORT
      LAYER M5 ;
        RECT  6.192 51.756 6.216 51.84 ;
    END
  END q[57]
  PIN q[58]
    DIRECTION OUTPUT ;
    USE SIGNAL ;
    PORT
      LAYER M3 ;
        RECT  6.3 51.802 6.318 51.84 ;
    END
  END q[58]
  PIN q[59]
    DIRECTION OUTPUT ;
    USE SIGNAL ;
    PORT
      LAYER M5 ;
        RECT  6.384 51.756 6.408 51.84 ;
    END
  END q[59]
  PIN q[5]
    DIRECTION OUTPUT ;
    USE SIGNAL ;
    PORT
      LAYER M5 ;
        RECT  1.056 51.756 1.08 51.84 ;
    END
  END q[5]
  PIN q[60]
    DIRECTION OUTPUT ;
    USE SIGNAL ;
    PORT
      LAYER M3 ;
        RECT  6.48 51.802 6.498 51.84 ;
    END
  END q[60]
  PIN q[61]
    DIRECTION OUTPUT ;
    USE SIGNAL ;
    PORT
      LAYER M5 ;
        RECT  6.576 51.756 6.6 51.84 ;
    END
  END q[61]
  PIN q[62]
    DIRECTION OUTPUT ;
    USE SIGNAL ;
    PORT
      LAYER M3 ;
        RECT  6.696 51.802 6.714 51.84 ;
    END
  END q[62]
  PIN q[63]
    DIRECTION OUTPUT ;
    USE SIGNAL ;
    PORT
      LAYER M5 ;
        RECT  6.768 51.756 6.792 51.84 ;
    END
  END q[63]
  PIN q[64]
    DIRECTION OUTPUT ;
    USE SIGNAL ;
    PORT
      LAYER M3 ;
        RECT  6.876 51.802 6.894 51.84 ;
    END
  END q[64]
  PIN q[65]
    DIRECTION OUTPUT ;
    USE SIGNAL ;
    PORT
      LAYER M5 ;
        RECT  6.96 51.756 6.984 51.84 ;
    END
  END q[65]
  PIN q[66]
    DIRECTION OUTPUT ;
    USE SIGNAL ;
    PORT
      LAYER M3 ;
        RECT  7.056 51.802 7.074 51.84 ;
    END
  END q[66]
  PIN q[67]
    DIRECTION OUTPUT ;
    USE SIGNAL ;
    PORT
      LAYER M5 ;
        RECT  7.152 51.756 7.176 51.84 ;
    END
  END q[67]
  PIN q[68]
    DIRECTION OUTPUT ;
    USE SIGNAL ;
    PORT
      LAYER M3 ;
        RECT  7.272 51.802 7.29 51.84 ;
    END
  END q[68]
  PIN q[69]
    DIRECTION OUTPUT ;
    USE SIGNAL ;
    PORT
      LAYER M5 ;
        RECT  7.344 51.756 7.368 51.84 ;
    END
  END q[69]
  PIN q[6]
    DIRECTION OUTPUT ;
    USE SIGNAL ;
    PORT
      LAYER M3 ;
        RECT  1.188 51.802 1.206 51.84 ;
    END
  END q[6]
  PIN q[70]
    DIRECTION OUTPUT ;
    USE SIGNAL ;
    PORT
      LAYER M3 ;
        RECT  7.452 51.802 7.47 51.84 ;
    END
  END q[70]
  PIN q[71]
    DIRECTION OUTPUT ;
    USE SIGNAL ;
    PORT
      LAYER M5 ;
        RECT  7.584 51.756 7.608 51.84 ;
    END
  END q[71]
  PIN q[72]
    DIRECTION OUTPUT ;
    USE SIGNAL ;
    PORT
      LAYER M3 ;
        RECT  7.668 51.802 7.686 51.84 ;
    END
  END q[72]
  PIN q[73]
    DIRECTION OUTPUT ;
    USE SIGNAL ;
    PORT
      LAYER M5 ;
        RECT  7.776 51.756 7.8 51.84 ;
    END
  END q[73]
  PIN q[74]
    DIRECTION OUTPUT ;
    USE SIGNAL ;
    PORT
      LAYER M3 ;
        RECT  7.848 51.802 7.866 51.84 ;
    END
  END q[74]
  PIN q[75]
    DIRECTION OUTPUT ;
    USE SIGNAL ;
    PORT
      LAYER M5 ;
        RECT  7.968 51.756 7.992 51.84 ;
    END
  END q[75]
  PIN q[76]
    DIRECTION OUTPUT ;
    USE SIGNAL ;
    PORT
      LAYER M3 ;
        RECT  8.064 51.802 8.082 51.84 ;
    END
  END q[76]
  PIN q[77]
    DIRECTION OUTPUT ;
    USE SIGNAL ;
    PORT
      LAYER M5 ;
        RECT  8.16 51.756 8.184 51.84 ;
    END
  END q[77]
  PIN q[78]
    DIRECTION OUTPUT ;
    USE SIGNAL ;
    PORT
      LAYER M3 ;
        RECT  8.244 51.802 8.262 51.84 ;
    END
  END q[78]
  PIN q[79]
    DIRECTION OUTPUT ;
    USE SIGNAL ;
    PORT
      LAYER M5 ;
        RECT  8.352 51.756 8.376 51.84 ;
    END
  END q[79]
  PIN q[7]
    DIRECTION OUTPUT ;
    USE SIGNAL ;
    PORT
      LAYER M5 ;
        RECT  1.248 51.756 1.272 51.84 ;
    END
  END q[7]
  PIN q[80]
    DIRECTION OUTPUT ;
    USE SIGNAL ;
    PORT
      LAYER M3 ;
        RECT  8.46 51.802 8.478 51.84 ;
    END
  END q[80]
  PIN q[81]
    DIRECTION OUTPUT ;
    USE SIGNAL ;
    PORT
      LAYER M5 ;
        RECT  8.544 51.756 8.568 51.84 ;
    END
  END q[81]
  PIN q[82]
    DIRECTION OUTPUT ;
    USE SIGNAL ;
    PORT
      LAYER M3 ;
        RECT  8.64 51.802 8.658 51.84 ;
    END
  END q[82]
  PIN q[83]
    DIRECTION OUTPUT ;
    USE SIGNAL ;
    PORT
      LAYER M5 ;
        RECT  8.736 51.756 8.76 51.84 ;
    END
  END q[83]
  PIN q[84]
    DIRECTION OUTPUT ;
    USE SIGNAL ;
    PORT
      LAYER M3 ;
        RECT  8.856 51.802 8.874 51.84 ;
    END
  END q[84]
  PIN q[85]
    DIRECTION OUTPUT ;
    USE SIGNAL ;
    PORT
      LAYER M5 ;
        RECT  8.928 51.756 8.952 51.84 ;
    END
  END q[85]
  PIN q[86]
    DIRECTION OUTPUT ;
    USE SIGNAL ;
    PORT
      LAYER M3 ;
        RECT  9.036 51.802 9.054 51.84 ;
    END
  END q[86]
  PIN q[87]
    DIRECTION OUTPUT ;
    USE SIGNAL ;
    PORT
      LAYER M5 ;
        RECT  9.12 51.756 9.144 51.84 ;
    END
  END q[87]
  PIN q[88]
    DIRECTION OUTPUT ;
    USE SIGNAL ;
    PORT
      LAYER M3 ;
        RECT  9.252 51.802 9.27 51.84 ;
    END
  END q[88]
  PIN q[89]
    DIRECTION OUTPUT ;
    USE SIGNAL ;
    PORT
      LAYER M5 ;
        RECT  9.312 51.756 9.336 51.84 ;
    END
  END q[89]
  PIN q[8]
    DIRECTION OUTPUT ;
    USE SIGNAL ;
    PORT
      LAYER M3 ;
        RECT  1.368 51.802 1.386 51.84 ;
    END
  END q[8]
  PIN q[90]
    DIRECTION OUTPUT ;
    USE SIGNAL ;
    PORT
      LAYER M3 ;
        RECT  9.432 51.802 9.45 51.84 ;
    END
  END q[90]
  PIN q[91]
    DIRECTION OUTPUT ;
    USE SIGNAL ;
    PORT
      LAYER M5 ;
        RECT  9.552 51.756 9.576 51.84 ;
    END
  END q[91]
  PIN q[92]
    DIRECTION OUTPUT ;
    USE SIGNAL ;
    PORT
      LAYER M3 ;
        RECT  9.648 51.802 9.666 51.84 ;
    END
  END q[92]
  PIN q[93]
    DIRECTION OUTPUT ;
    USE SIGNAL ;
    PORT
      LAYER M5 ;
        RECT  9.744 51.756 9.768 51.84 ;
    END
  END q[93]
  PIN q[94]
    DIRECTION OUTPUT ;
    USE SIGNAL ;
    PORT
      LAYER M3 ;
        RECT  9.828 51.802 9.846 51.84 ;
    END
  END q[94]
  PIN q[95]
    DIRECTION OUTPUT ;
    USE SIGNAL ;
    PORT
      LAYER M5 ;
        RECT  9.936 51.756 9.96 51.84 ;
    END
  END q[95]
  PIN q[96]
    DIRECTION OUTPUT ;
    USE SIGNAL ;
    PORT
      LAYER M3 ;
        RECT  10.008 51.802 10.026 51.84 ;
    END
  END q[96]
  PIN q[97]
    DIRECTION OUTPUT ;
    USE SIGNAL ;
    PORT
      LAYER M5 ;
        RECT  10.128 51.756 10.152 51.84 ;
    END
  END q[97]
  PIN q[98]
    DIRECTION OUTPUT ;
    USE SIGNAL ;
    PORT
      LAYER M3 ;
        RECT  10.224 51.802 10.242 51.84 ;
    END
  END q[98]
  PIN q[99]
    DIRECTION OUTPUT ;
    USE SIGNAL ;
    PORT
      LAYER M5 ;
        RECT  10.32 51.756 10.344 51.84 ;
    END
  END q[99]
  PIN q[9]
    DIRECTION OUTPUT ;
    USE SIGNAL ;
    PORT
      LAYER M5 ;
        RECT  1.44 51.756 1.464 51.84 ;
    END
  END q[9]
  PIN VDD
    DIRECTION INOUT ;
    USE POWER ;
    PORT
      LAYER M5 ;
        RECT  45.792 2.151 45.912 49.689 ;
        RECT  40.392 2.151 40.512 49.689 ;
        RECT  34.992 2.151 35.112 49.689 ;
        RECT  29.592 2.151 29.712 49.689 ;
        RECT  24.192 2.151 24.312 49.689 ;
        RECT  18.792 2.151 18.912 49.689 ;
        RECT  13.392 2.151 13.512 49.689 ;
        RECT  7.992 2.151 8.112 49.689 ;
        RECT  2.592 2.151 2.712 49.689 ;
    END
  END VDD
  PIN VSS
    DIRECTION INOUT ;
    USE GROUND ;
    PORT
      LAYER M5 ;
        RECT  45.6 2.137 45.72 49.703 ;
        RECT  40.2 2.137 40.32 49.703 ;
        RECT  34.8 2.137 34.92 49.703 ;
        RECT  29.4 2.137 29.52 49.703 ;
        RECT  24 2.137 24.12 49.703 ;
        RECT  18.6 2.137 18.72 49.703 ;
        RECT  13.2 2.137 13.32 49.703 ;
        RECT  7.8 2.137 7.92 49.703 ;
        RECT  2.4 2.137 2.52 49.703 ;
    END
  END VSS
  # OT_OBS_CLOSED layer=M5 d_um=1.536 added=79
  OBS
    LAYER RVTN ;
     RECT  2.16 2.16 49.68 2.295 ;
     RECT  2.16 2.565 49.68 2.835 ;
     RECT  2.16 3.105 49.68 3.375 ;
     RECT  2.16 3.645 49.68 3.915 ;
     RECT  2.16 4.185 49.68 4.455 ;
     RECT  2.16 4.725 49.68 4.995 ;
     RECT  2.16 5.265 49.68 5.535 ;
     RECT  2.16 5.805 49.68 6.075 ;
     RECT  2.16 6.345 49.68 6.615 ;
     RECT  2.16 6.885 49.68 7.155 ;
     RECT  2.16 7.425 49.68 7.695 ;
     RECT  2.16 7.965 49.68 8.235 ;
     RECT  2.16 8.505 49.68 8.775 ;
     RECT  2.16 9.045 49.68 9.315 ;
     RECT  2.16 9.585 49.68 9.855 ;
     RECT  2.16 10.125 49.68 10.395 ;
     RECT  2.16 10.665 49.68 10.935 ;
     RECT  2.16 11.205 49.68 11.475 ;
     RECT  2.16 11.745 49.68 12.015 ;
     RECT  2.16 12.285 49.68 12.555 ;
     RECT  2.16 12.825 49.68 13.095 ;
     RECT  2.16 13.365 49.68 13.635 ;
     RECT  2.16 13.905 49.68 14.175 ;
     RECT  2.16 14.445 49.68 14.715 ;
     RECT  2.16 14.985 49.68 15.255 ;
     RECT  2.16 15.525 49.68 15.795 ;
     RECT  2.16 16.065 49.68 16.335 ;
     RECT  2.16 16.605 49.68 16.875 ;
     RECT  2.16 17.145 49.68 17.415 ;
     RECT  2.16 17.685 49.68 17.955 ;
     RECT  2.16 18.225 49.68 18.495 ;
     RECT  2.16 18.765 49.68 19.035 ;
     RECT  2.16 19.305 49.68 19.575 ;
     RECT  2.16 19.845 49.68 20.115 ;
     RECT  2.16 20.385 49.68 20.655 ;
     RECT  2.16 20.925 49.68 21.195 ;
     RECT  2.16 21.465 49.68 21.735 ;
     RECT  2.16 22.005 49.68 22.275 ;
     RECT  2.16 22.545 49.68 22.815 ;
     RECT  2.16 23.085 49.68 23.355 ;
     RECT  2.16 23.625 49.68 23.895 ;
     RECT  2.16 24.165 49.68 24.435 ;
     RECT  2.16 24.705 49.68 24.975 ;
     RECT  2.16 25.245 49.68 25.515 ;
     RECT  2.16 25.785 49.68 26.055 ;
     RECT  2.16 26.325 49.68 26.595 ;
     RECT  2.16 26.865 49.68 27.135 ;
     RECT  2.16 27.405 49.68 27.675 ;
     RECT  2.16 27.945 49.68 28.215 ;
     RECT  2.16 28.485 49.68 28.755 ;
     RECT  2.16 29.025 49.68 29.295 ;
     RECT  2.16 29.565 49.68 29.835 ;
     RECT  2.16 30.105 49.68 30.375 ;
     RECT  2.16 30.645 49.68 30.915 ;
     RECT  2.16 31.185 49.68 31.455 ;
     RECT  2.16 31.725 49.68 31.995 ;
     RECT  2.16 32.265 49.68 32.535 ;
     RECT  2.16 32.805 49.68 33.075 ;
     RECT  2.16 33.345 49.68 33.615 ;
     RECT  2.16 33.885 49.68 34.155 ;
     RECT  2.16 34.425 49.68 34.695 ;
     RECT  2.16 34.965 49.68 35.235 ;
     RECT  2.16 35.505 49.68 35.775 ;
     RECT  2.16 36.045 49.68 36.315 ;
     RECT  2.16 36.585 49.68 36.855 ;
     RECT  2.16 37.125 49.68 37.395 ;
     RECT  2.16 37.665 49.68 37.935 ;
     RECT  2.16 38.205 49.68 38.475 ;
     RECT  2.16 38.745 49.68 39.015 ;
     RECT  2.16 39.285 49.68 39.555 ;
     RECT  2.16 39.825 49.68 40.095 ;
     RECT  2.16 40.365 49.68 40.635 ;
     RECT  2.16 40.905 49.68 41.175 ;
     RECT  2.16 41.445 49.68 41.715 ;
     RECT  2.16 41.985 49.68 42.255 ;
     RECT  2.16 42.525 49.68 42.795 ;
     RECT  2.16 43.065 49.68 43.335 ;
     RECT  2.16 43.605 49.68 43.875 ;
     RECT  2.16 44.145 49.68 44.415 ;
     RECT  2.16 44.685 49.68 44.955 ;
     RECT  2.16 45.225 49.68 45.495 ;
     RECT  2.16 45.765 49.68 46.035 ;
     RECT  2.16 46.305 49.68 46.575 ;
     RECT  2.16 46.845 49.68 47.115 ;
     RECT  2.16 47.385 49.68 47.655 ;
     RECT  2.16 47.925 49.68 48.195 ;
     RECT  2.16 48.465 49.68 48.735 ;
     RECT  2.16 49.005 49.68 49.275 ;
     RECT  2.16 49.545 49.68 49.68 ;
    LAYER RVTP ;
     RECT  2.16 2.295 49.68 2.565 ;
     RECT  2.16 2.835 49.68 3.105 ;
     RECT  2.16 3.375 49.68 3.645 ;
     RECT  2.16 3.915 49.68 4.185 ;
     RECT  2.16 4.455 49.68 4.725 ;
     RECT  2.16 4.995 49.68 5.265 ;
     RECT  2.16 5.535 49.68 5.805 ;
     RECT  2.16 6.075 49.68 6.345 ;
     RECT  2.16 6.615 49.68 6.885 ;
     RECT  2.16 7.155 49.68 7.425 ;
     RECT  2.16 7.695 49.68 7.965 ;
     RECT  2.16 8.235 49.68 8.505 ;
     RECT  2.16 8.775 49.68 9.045 ;
     RECT  2.16 9.315 49.68 9.585 ;
     RECT  2.16 9.855 49.68 10.125 ;
     RECT  2.16 10.395 49.68 10.665 ;
     RECT  2.16 10.935 49.68 11.205 ;
     RECT  2.16 11.475 49.68 11.745 ;
     RECT  2.16 12.015 49.68 12.285 ;
     RECT  2.16 12.555 49.68 12.825 ;
     RECT  2.16 13.095 49.68 13.365 ;
     RECT  2.16 13.635 49.68 13.905 ;
     RECT  2.16 14.175 49.68 14.445 ;
     RECT  2.16 14.715 49.68 14.985 ;
     RECT  2.16 15.255 49.68 15.525 ;
     RECT  2.16 15.795 49.68 16.065 ;
     RECT  2.16 16.335 49.68 16.605 ;
     RECT  2.16 16.875 49.68 17.145 ;
     RECT  2.16 17.415 49.68 17.685 ;
     RECT  2.16 17.955 49.68 18.225 ;
     RECT  2.16 18.495 49.68 18.765 ;
     RECT  2.16 19.035 49.68 19.305 ;
     RECT  2.16 19.575 49.68 19.845 ;
     RECT  2.16 20.115 49.68 20.385 ;
     RECT  2.16 20.655 49.68 20.925 ;
     RECT  2.16 21.195 49.68 21.465 ;
     RECT  2.16 21.735 49.68 22.005 ;
     RECT  2.16 22.275 49.68 22.545 ;
     RECT  2.16 22.815 49.68 23.085 ;
     RECT  2.16 23.355 49.68 23.625 ;
     RECT  2.16 23.895 49.68 24.165 ;
     RECT  2.16 24.435 49.68 24.705 ;
     RECT  2.16 24.975 49.68 25.245 ;
     RECT  2.16 25.515 49.68 25.785 ;
     RECT  2.16 26.055 49.68 26.325 ;
     RECT  2.16 26.595 49.68 26.865 ;
     RECT  2.16 27.135 49.68 27.405 ;
     RECT  2.16 27.675 49.68 27.945 ;
     RECT  2.16 28.215 49.68 28.485 ;
     RECT  2.16 28.755 49.68 29.025 ;
     RECT  2.16 29.295 49.68 29.565 ;
     RECT  2.16 29.835 49.68 30.105 ;
     RECT  2.16 30.375 49.68 30.645 ;
     RECT  2.16 30.915 49.68 31.185 ;
     RECT  2.16 31.455 49.68 31.725 ;
     RECT  2.16 31.995 49.68 32.265 ;
     RECT  2.16 32.535 49.68 32.805 ;
     RECT  2.16 33.075 49.68 33.345 ;
     RECT  2.16 33.615 49.68 33.885 ;
     RECT  2.16 34.155 49.68 34.425 ;
     RECT  2.16 34.695 49.68 34.965 ;
     RECT  2.16 35.235 49.68 35.505 ;
     RECT  2.16 35.775 49.68 36.045 ;
     RECT  2.16 36.315 49.68 36.585 ;
     RECT  2.16 36.855 49.68 37.125 ;
     RECT  2.16 37.395 49.68 37.665 ;
     RECT  2.16 37.935 49.68 38.205 ;
     RECT  2.16 38.475 49.68 38.745 ;
     RECT  2.16 39.015 49.68 39.285 ;
     RECT  2.16 39.555 49.68 39.825 ;
     RECT  2.16 40.095 49.68 40.365 ;
     RECT  2.16 40.635 49.68 40.905 ;
     RECT  2.16 41.175 49.68 41.445 ;
     RECT  2.16 41.715 49.68 41.985 ;
     RECT  2.16 42.255 49.68 42.525 ;
     RECT  2.16 42.795 49.68 43.065 ;
     RECT  2.16 43.335 49.68 43.605 ;
     RECT  2.16 43.875 49.68 44.145 ;
     RECT  2.16 44.415 49.68 44.685 ;
     RECT  2.16 44.955 49.68 45.225 ;
     RECT  2.16 45.495 49.68 45.765 ;
     RECT  2.16 46.035 49.68 46.305 ;
     RECT  2.16 46.575 49.68 46.845 ;
     RECT  2.16 47.115 49.68 47.385 ;
     RECT  2.16 47.655 49.68 47.925 ;
     RECT  2.16 48.195 49.68 48.465 ;
     RECT  2.16 48.735 49.68 49.005 ;
     RECT  2.16 49.275 49.68 49.545 ;
    LAYER M1 ;
     RECT  2.16 2.151 49.68 49.689 ;
    LAYER M2 ;
     RECT  0.571 18.774 0.751 18.792 ;
     RECT  0.571 48.816 0.787 48.834 ;
     RECT  0.751 18.774 0.967 19.53 ;
     RECT  0.787 48.276 0.967 48.834 ;
     RECT  0.967 48.276 1.111 49.374 ;
     RECT  0.967 18.162 1.543 19.53 ;
     RECT  1.147 20.664 1.543 20.682 ;
     RECT  1.111 48.096 1.759 49.572 ;
     RECT  1.543 18.162 1.867 20.682 ;
     RECT  1.831 43.272 1.975 43.29 ;
     RECT  1.867 18.162 2.011 21.42 ;
     RECT  1.903 41.886 2.011 41.904 ;
     RECT  2.011 18.126 2.047 21.42 ;
     RECT  1.939 22.824 2.047 22.842 ;
     RECT  1.759 47.664 2.155 49.572 ;
     RECT  2.047 18.126 2.16 21.834 ;
     RECT  2.047 22.824 2.16 22.914 ;
     RECT  2.047 26.838 2.16 26.856 ;
     RECT  2.047 30.69 2.16 30.708 ;
     RECT  2.011 41.616 2.16 41.904 ;
     RECT  1.975 43.272 2.16 43.794 ;
     RECT  2.083 44.586 2.16 44.604 ;
     RECT  2.119 45.396 2.16 45.414 ;
     RECT  2.047 46.206 2.16 46.224 ;
     RECT  2.155 47.286 2.16 49.572 ;
     RECT  2.16 2.151 2.443 49.689 ;
     RECT  2.443 1.998 2.695 49.689 ;
     RECT  2.695 1.728 2.867 49.689 ;
     RECT  2.947 50.706 3.191 50.724 ;
     RECT  1.867 0.036 3.667 0.054 ;
     RECT  3.667 0.036 3.803 0.126 ;
     RECT  4.495 50.706 4.711 50.724 ;
     RECT  4.711 50.634 4.919 50.724 ;
     RECT  3.803 0.036 5.243 0.054 ;
     RECT  5.359 0.108 6.115 0.126 ;
     RECT  6.115 0.036 6.367 0.126 ;
     RECT  6.367 0.036 6.791 0.198 ;
     RECT  4.919 50.706 7.735 50.724 ;
     RECT  7.735 50.634 7.871 50.769 ;
     RECT  7.871 50.634 7.979 50.724 ;
     RECT  6.791 0.036 8.267 0.054 ;
     RECT  2.867 2.151 8.455 49.689 ;
     RECT  8.455 1.692 8.591 49.689 ;
     RECT  7.979 50.706 9.023 50.724 ;
     RECT  9.031 0.108 9.167 0.126 ;
     RECT  8.591 2.151 9.247 49.689 ;
     RECT  9.247 2.151 9.383 50.229 ;
     RECT  9.383 2.151 9.887 50.184 ;
     RECT  9.247 0.036 10.139 0.054 ;
     RECT  10.795 50.436 10.931 50.454 ;
     RECT  10.939 0.036 11.039 0.054 ;
     RECT  11.011 50.706 11.147 50.814 ;
     RECT  11.147 50.706 11.327 50.724 ;
     RECT  11.911 0.036 12.443 0.054 ;
     RECT  9.887 2.151 13.099 49.689 ;
     RECT  13.099 2.151 13.315 50.229 ;
     RECT  13.315 2.07 13.667 50.229 ;
     RECT  13.711 0.036 14.711 0.054 ;
     RECT  13.667 2.151 14.755 49.689 ;
     RECT  13.747 50.706 14.755 50.724 ;
     RECT  14.755 2.151 14.927 50.724 ;
     RECT  14.927 50.706 17.095 50.724 ;
     RECT  15.439 0.036 17.627 0.054 ;
     RECT  18.427 0.036 18.563 0.054 ;
     RECT  14.927 2.151 18.571 49.689 ;
     RECT  18.571 2.151 18.707 49.77 ;
     RECT  17.095 50.634 19.859 50.724 ;
     RECT  19.507 0.036 20.507 0.054 ;
     RECT  19.859 50.706 20.507 50.724 ;
     RECT  21.343 50.796 21.415 50.814 ;
     RECT  21.415 50.706 21.659 50.814 ;
     RECT  21.659 50.706 21.811 50.724 ;
     RECT  21.451 0.036 22.235 0.054 ;
     RECT  18.707 2.151 22.603 49.689 ;
     RECT  21.811 50.634 22.603 50.724 ;
     RECT  22.603 2.151 22.703 50.724 ;
     RECT  22.963 0.036 23.531 0.054 ;
     RECT  22.703 50.706 24.187 50.724 ;
     RECT  24.187 50.634 24.647 50.724 ;
     RECT  24.647 50.634 24.979 50.688 ;
     RECT  24.979 50.481 25.187 50.688 ;
     RECT  25.187 50.562 25.223 50.688 ;
     RECT  25.231 0.036 25.331 0.054 ;
     RECT  25.223 50.634 25.375 50.688 ;
     RECT  25.447 51.786 25.583 51.804 ;
     RECT  26.419 0.036 26.599 0.054 ;
     RECT  25.375 50.634 26.663 50.724 ;
     RECT  26.599 0.036 26.879 0.126 ;
     RECT  26.879 0.036 28.039 0.054 ;
     RECT  26.663 50.706 28.111 50.724 ;
     RECT  22.703 2.151 28.255 49.689 ;
     RECT  28.111 50.634 28.255 50.724 ;
     RECT  28.255 2.151 28.391 50.724 ;
     RECT  28.039 0.036 28.427 0.126 ;
     RECT  28.391 50.634 28.931 50.724 ;
     RECT  28.391 2.151 29.011 49.689 ;
     RECT  29.011 1.728 29.579 49.689 ;
     RECT  28.931 50.706 29.695 50.724 ;
     RECT  29.695 50.634 29.903 50.724 ;
     RECT  28.427 0.036 30.011 0.054 ;
     RECT  30.883 51.786 31.019 51.804 ;
     RECT  29.903 50.706 31.271 50.724 ;
     RECT  31.207 0.036 31.343 0.054 ;
     RECT  31.279 50.634 31.343 50.652 ;
     RECT  31.639 0.531 31.775 0.549 ;
     RECT  32.071 50.706 32.251 50.724 ;
     RECT  32.215 0.036 32.279 0.054 ;
     RECT  32.251 50.67 32.431 50.724 ;
     RECT  32.431 50.634 32.603 50.724 ;
     RECT  34.015 0.036 34.195 0.054 ;
     RECT  32.603 50.706 34.231 50.724 ;
     RECT  34.195 0.036 34.303 0.126 ;
     RECT  34.303 0.036 34.619 0.198 ;
     RECT  34.951 1.116 35.087 1.134 ;
     RECT  34.619 0.036 35.563 0.054 ;
     RECT  35.563 0.036 35.627 0.126 ;
     RECT  34.231 50.634 35.779 50.724 ;
     RECT  35.779 50.634 35.915 50.814 ;
     RECT  35.915 50.634 36.203 50.724 ;
     RECT  35.627 0.036 36.347 0.054 ;
     RECT  36.203 50.706 36.491 50.724 ;
     RECT  37.183 50.634 37.363 50.652 ;
     RECT  37.363 50.634 37.391 50.724 ;
     RECT  38.083 0.036 38.147 0.054 ;
     RECT  39.019 0.036 39.559 0.054 ;
     RECT  39.559 0.036 39.631 0.126 ;
     RECT  29.579 2.151 39.955 49.689 ;
     RECT  39.631 0.036 40.019 0.594 ;
     RECT  39.955 2.151 40.343 49.77 ;
     RECT  40.019 0.036 40.883 0.126 ;
     RECT  37.391 50.706 40.883 50.724 ;
     RECT  40.891 50.634 40.991 50.652 ;
     RECT  40.883 0.036 41.683 0.054 ;
     RECT  41.683 0.036 41.963 0.126 ;
     RECT  43.195 51.786 43.295 51.804 ;
     RECT  41.963 0.036 44.203 0.054 ;
     RECT  44.203 0.036 44.339 0.126 ;
     RECT  44.339 0.036 44.663 0.054 ;
     RECT  40.343 2.151 45.247 49.689 ;
     RECT  45.283 51.786 45.455 51.804 ;
     RECT  45.247 1.728 45.535 49.689 ;
     RECT  45.535 1.728 45.671 50.184 ;
     RECT  45.671 1.728 45.815 49.689 ;
     RECT  45.607 0.036 45.959 0.054 ;
     RECT  47.587 51.786 47.687 51.804 ;
     RECT  46.759 0.036 48.911 0.054 ;
     RECT  45.815 2.151 48.991 49.689 ;
     RECT  48.991 2.151 49.135 50.148 ;
     RECT  49.135 2.151 49.415 50.724 ;
     RECT  49.415 2.151 49.68 50.148 ;
     RECT  49.68 18 49.703 18.756 ;
     RECT  49.68 27.216 49.703 27.234 ;
     RECT  49.68 21.276 49.739 21.294 ;
     RECT  49.68 47.826 49.739 50.148 ;
     RECT  49.68 46.926 49.775 46.944 ;
     RECT  49.68 19.62 49.883 19.638 ;
     RECT  49.703 18 50.063 18.216 ;
     RECT  49.739 47.826 50.171 49.464 ;
     RECT  50.063 18.198 50.279 18.216 ;
     RECT  49.68 16.884 50.387 16.902 ;
     RECT  50.171 47.826 50.387 48.69 ;
     RECT  50.171 49.446 50.567 49.464 ;
     RECT  50.387 47.826 50.819 48.528 ;
     RECT  50.819 47.862 50.855 48.528 ;
     RECT  50.855 47.862 50.891 48.294 ;
     RECT  50.891 47.862 50.963 48.024 ;
     RECT  50.963 47.862 51.179 47.88 ;
    LAYER M3 ;
     RECT  0.594 0.012 0.756 0.038 ;
     RECT  0.774 0.012 0.972 0.038 ;
     RECT  0.99 0.012 1.152 0.038 ;
     RECT  1.17 0.012 1.368 0.038 ;
     RECT  1.386 0.012 1.548 0.038 ;
     RECT  1.566 0.012 1.728 0.038 ;
     RECT  1.746 0.012 1.944 0.038 ;
     RECT  1.962 0.012 2.124 0.038 ;
     RECT  2.142 0.012 2.304 0.038 ;
     RECT  2.322 0.012 2.52 0.038 ;
     RECT  2.538 0.012 2.7 0.038 ;
     RECT  2.718 0.012 2.916 0.038 ;
     RECT  2.934 0.012 3.096 0.038 ;
     RECT  3.114 0.012 3.276 0.038 ;
     RECT  3.294 0.012 3.492 0.038 ;
     RECT  3.51 0.012 3.672 0.038 ;
     RECT  3.69 0.012 3.852 0.038 ;
     RECT  3.87 0.012 4.068 0.038 ;
     RECT  4.086 0.012 4.248 0.038 ;
     RECT  4.266 0.012 4.428 0.038 ;
     RECT  4.446 0.012 4.644 0.038 ;
     RECT  4.662 0.012 4.824 0.038 ;
     RECT  4.842 0.012 5.04 0.038 ;
     RECT  5.058 0.012 5.22 0.038 ;
     RECT  5.238 0.012 5.4 0.038 ;
     RECT  5.418 0.012 5.616 0.038 ;
     RECT  5.634 0.012 5.796 0.038 ;
     RECT  5.814 0.012 5.976 0.038 ;
     RECT  5.994 0.012 6.192 0.038 ;
     RECT  6.21 0.012 6.372 0.038 ;
     RECT  6.39 0.012 6.588 0.038 ;
     RECT  6.606 0.012 6.768 0.038 ;
     RECT  6.786 0.012 6.948 0.038 ;
     RECT  6.966 0.012 7.164 0.038 ;
     RECT  7.182 0.012 7.344 0.038 ;
     RECT  7.362 0.012 7.524 0.038 ;
     RECT  7.542 0.012 7.74 0.038 ;
     RECT  7.758 0.012 7.92 0.038 ;
     RECT  7.938 0.012 8.1 0.038 ;
     RECT  8.118 0.012 8.316 0.038 ;
     RECT  8.334 0.012 8.496 0.038 ;
     RECT  8.514 0.012 8.712 0.038 ;
     RECT  8.73 0.012 8.892 0.038 ;
     RECT  8.91 0.012 9.072 0.038 ;
     RECT  9.09 0.012 9.288 0.038 ;
     RECT  9.306 0.012 9.468 0.038 ;
     RECT  9.486 0.012 9.648 0.038 ;
     RECT  9.666 0.012 9.864 0.038 ;
     RECT  9.882 0.012 10.044 0.038 ;
     RECT  10.062 0.012 10.26 0.038 ;
     RECT  10.278 0.012 10.44 0.038 ;
     RECT  10.458 0.012 10.62 0.038 ;
     RECT  10.638 0.012 10.836 0.038 ;
     RECT  10.854 0.012 11.016 0.038 ;
     RECT  11.034 0.012 11.196 0.038 ;
     RECT  11.214 0.012 11.412 0.038 ;
     RECT  11.43 0.012 11.592 0.038 ;
     RECT  11.61 0.012 11.772 0.038 ;
     RECT  11.79 0.012 11.988 0.038 ;
     RECT  12.006 0.012 12.168 0.038 ;
     RECT  12.186 0.012 12.384 0.038 ;
     RECT  12.402 0.012 12.564 0.038 ;
     RECT  12.582 0.012 12.744 0.038 ;
     RECT  12.762 0.012 12.96 0.038 ;
     RECT  12.978 0.012 13.14 0.038 ;
     RECT  13.158 0.012 13.32 0.038 ;
     RECT  13.338 0.012 13.536 0.038 ;
     RECT  13.554 0.012 13.716 0.038 ;
     RECT  13.734 0.012 13.932 0.038 ;
     RECT  13.95 0.012 14.112 0.038 ;
     RECT  14.13 0.012 14.292 0.038 ;
     RECT  14.31 0.012 14.508 0.038 ;
     RECT  14.526 0.012 14.688 0.038 ;
     RECT  14.706 0.012 14.868 0.038 ;
     RECT  14.886 0.012 15.084 0.038 ;
     RECT  15.102 0.012 15.264 0.038 ;
     RECT  15.282 0.012 15.444 0.038 ;
     RECT  15.462 0.012 15.66 0.038 ;
     RECT  15.678 0.012 15.84 0.038 ;
     RECT  15.858 0.012 16.056 0.038 ;
     RECT  16.074 0.012 16.236 0.038 ;
     RECT  16.254 0.012 16.416 0.038 ;
     RECT  16.434 0.012 16.632 0.038 ;
     RECT  16.65 0.012 16.812 0.038 ;
     RECT  16.83 0.012 16.992 0.038 ;
     RECT  17.01 0.012 17.208 0.038 ;
     RECT  17.226 0.012 17.388 0.038 ;
     RECT  17.406 0.012 17.604 0.038 ;
     RECT  17.622 0.012 17.784 0.038 ;
     RECT  17.802 0.012 17.964 0.038 ;
     RECT  17.982 0.012 18.18 0.038 ;
     RECT  18.198 0.012 18.36 0.038 ;
     RECT  18.378 0.012 18.54 0.038 ;
     RECT  18.558 0.012 18.756 0.038 ;
     RECT  18.774 0.012 18.936 0.038 ;
     RECT  18.954 0.012 19.116 0.038 ;
     RECT  19.134 0.012 19.332 0.038 ;
     RECT  19.35 0.012 19.512 0.038 ;
     RECT  19.53 0.012 19.728 0.038 ;
     RECT  19.746 0.012 19.908 0.038 ;
     RECT  19.926 0.012 20.088 0.038 ;
     RECT  20.106 0.012 20.304 0.038 ;
     RECT  20.322 0.012 20.484 0.038 ;
     RECT  20.502 0.012 20.664 0.038 ;
     RECT  20.682 0.012 20.88 0.038 ;
     RECT  20.898 0.012 21.06 0.038 ;
     RECT  21.078 0.012 21.276 0.038 ;
     RECT  21.294 0.012 21.456 0.038 ;
     RECT  21.474 0.012 21.636 0.038 ;
     RECT  21.654 0.012 21.852 0.038 ;
     RECT  21.87 0.012 22.032 0.038 ;
     RECT  22.05 0.012 22.212 0.038 ;
     RECT  22.23 0.012 22.428 0.038 ;
     RECT  22.446 0.012 22.608 0.038 ;
     RECT  22.626 0.012 22.788 0.038 ;
     RECT  22.806 0.012 23.004 0.038 ;
     RECT  23.022 0.012 23.184 0.038 ;
     RECT  23.202 0.012 23.4 0.038 ;
     RECT  23.418 0.012 23.58 0.038 ;
     RECT  23.598 0.012 23.76 0.038 ;
     RECT  23.778 0.012 23.976 0.038 ;
     RECT  23.994 0.012 24.156 0.038 ;
     RECT  24.174 0.012 24.336 0.038 ;
     RECT  24.354 0.012 24.552 0.038 ;
     RECT  24.57 0.012 24.732 0.038 ;
     RECT  24.75 0.012 24.948 0.038 ;
     RECT  24.966 0.012 25.128 0.038 ;
     RECT  25.146 0.012 25.308 0.038 ;
     RECT  25.326 0.012 25.524 0.038 ;
     RECT  25.542 0.012 25.704 0.038 ;
     RECT  25.722 0.012 25.884 0.038 ;
     RECT  25.902 0.012 26.1 0.038 ;
     RECT  26.118 0.012 26.28 0.038 ;
     RECT  26.298 0.012 26.46 0.038 ;
     RECT  26.478 0.012 26.676 0.038 ;
     RECT  26.694 0.012 26.856 0.038 ;
     RECT  26.874 0.012 27.072 0.038 ;
     RECT  27.09 0.012 27.252 0.038 ;
     RECT  27.27 0.012 27.432 0.038 ;
     RECT  27.45 0.012 27.648 0.038 ;
     RECT  27.666 0.012 27.828 0.038 ;
     RECT  27.846 0.012 28.008 0.038 ;
     RECT  28.026 0.012 28.224 0.038 ;
     RECT  28.242 0.012 28.404 0.038 ;
     RECT  28.422 0.012 28.584 0.038 ;
     RECT  28.602 0.012 28.8 0.038 ;
     RECT  28.818 0.012 28.98 0.038 ;
     RECT  28.998 0.012 29.196 0.038 ;
     RECT  29.214 0.012 29.376 0.038 ;
     RECT  29.394 0.012 29.556 0.038 ;
     RECT  29.574 0.012 29.772 0.038 ;
     RECT  29.79 0.012 29.952 0.038 ;
     RECT  29.97 0.012 30.132 0.038 ;
     RECT  30.15 0.012 30.348 0.038 ;
     RECT  30.366 0.012 30.528 0.038 ;
     RECT  30.546 0.012 30.744 0.038 ;
     RECT  30.762 0.012 30.924 0.038 ;
     RECT  30.942 0.012 31.104 0.038 ;
     RECT  31.122 0.012 31.32 0.038 ;
     RECT  31.338 0.012 31.5 0.038 ;
     RECT  31.518 0.012 31.68 0.038 ;
     RECT  31.698 0.012 31.896 0.038 ;
     RECT  31.914 0.012 32.076 0.038 ;
     RECT  32.094 0.012 32.256 0.038 ;
     RECT  32.274 0.012 32.472 0.038 ;
     RECT  32.49 0.012 32.652 0.038 ;
     RECT  32.67 0.012 32.868 0.038 ;
     RECT  32.886 0.012 33.048 0.038 ;
     RECT  33.066 0.012 33.228 0.038 ;
     RECT  33.246 0.012 33.444 0.038 ;
     RECT  33.462 0.012 33.624 0.038 ;
     RECT  33.642 0.012 33.804 0.038 ;
     RECT  33.822 0.012 34.02 0.038 ;
     RECT  34.038 0.012 34.2 0.038 ;
     RECT  34.218 0.012 34.416 0.038 ;
     RECT  34.434 0.012 34.596 0.038 ;
     RECT  34.614 0.012 34.776 0.038 ;
     RECT  34.794 0.012 34.992 0.038 ;
     RECT  35.01 0.012 35.172 0.038 ;
     RECT  35.19 0.012 35.352 0.038 ;
     RECT  35.37 0.012 35.568 0.038 ;
     RECT  35.586 0.012 35.748 0.038 ;
     RECT  35.766 0.012 35.928 0.038 ;
     RECT  35.946 0.012 36.144 0.038 ;
     RECT  36.162 0.012 36.324 0.038 ;
     RECT  36.342 0.012 36.54 0.038 ;
     RECT  36.558 0.012 36.72 0.038 ;
     RECT  36.738 0.012 36.9 0.038 ;
     RECT  36.918 0.012 37.116 0.038 ;
     RECT  37.134 0.012 37.296 0.038 ;
     RECT  37.314 0.012 37.476 0.038 ;
     RECT  37.494 0.012 37.692 0.038 ;
     RECT  37.71 0.012 37.872 0.038 ;
     RECT  37.89 0.012 38.088 0.038 ;
     RECT  38.106 0.012 38.268 0.038 ;
     RECT  38.286 0.012 38.448 0.038 ;
     RECT  38.466 0.012 38.664 0.038 ;
     RECT  38.682 0.012 38.844 0.038 ;
     RECT  38.862 0.012 39.024 0.038 ;
     RECT  39.042 0.012 39.24 0.038 ;
     RECT  39.258 0.012 39.42 0.038 ;
     RECT  39.438 0.012 39.6 0.038 ;
     RECT  39.618 0.012 39.816 0.038 ;
     RECT  39.834 0.012 39.996 0.038 ;
     RECT  40.014 0.012 40.212 0.038 ;
     RECT  40.23 0.012 40.392 0.038 ;
     RECT  40.41 0.012 40.572 0.038 ;
     RECT  40.59 0.012 40.788 0.038 ;
     RECT  40.806 0.012 40.968 0.038 ;
     RECT  40.986 0.012 41.148 0.038 ;
     RECT  41.166 0.012 41.364 0.038 ;
     RECT  41.382 0.012 41.544 0.038 ;
     RECT  41.562 0.012 41.76 0.038 ;
     RECT  41.778 0.012 41.94 0.038 ;
     RECT  41.958 0.012 42.12 0.038 ;
     RECT  42.138 0.012 42.336 0.038 ;
     RECT  42.354 0.012 42.516 0.038 ;
     RECT  42.534 0.012 42.696 0.038 ;
     RECT  42.714 0.012 42.912 0.038 ;
     RECT  42.93 0.012 43.092 0.038 ;
     RECT  43.11 0.012 43.272 0.038 ;
     RECT  43.29 0.012 43.488 0.038 ;
     RECT  43.506 0.012 43.668 0.038 ;
     RECT  43.686 0.012 43.884 0.038 ;
     RECT  43.902 0.012 44.064 0.038 ;
     RECT  44.082 0.012 44.244 0.038 ;
     RECT  44.262 0.012 44.46 0.038 ;
     RECT  44.478 0.012 44.64 0.038 ;
     RECT  44.658 0.012 44.82 0.038 ;
     RECT  44.838 0.012 45.036 0.038 ;
     RECT  45.054 0.012 45.216 0.038 ;
     RECT  45.234 0.012 45.432 0.038 ;
     RECT  45.45 0.012 45.612 0.038 ;
     RECT  45.63 0.012 45.792 0.038 ;
     RECT  45.81 0.012 46.008 0.038 ;
     RECT  46.026 0.012 46.188 0.038 ;
     RECT  46.206 0.012 46.368 0.038 ;
     RECT  46.386 0.012 46.584 0.038 ;
     RECT  46.602 0.012 46.764 0.038 ;
     RECT  46.782 0.012 46.944 0.038 ;
     RECT  46.962 0.012 47.16 0.038 ;
     RECT  47.178 0.012 47.34 0.038 ;
     RECT  47.358 0.012 47.556 0.038 ;
     RECT  47.574 0.012 47.736 0.038 ;
     RECT  47.754 0.012 47.916 0.038 ;
     RECT  47.934 0.012 48.132 0.038 ;
     RECT  48.15 0.012 48.312 0.038 ;
     RECT  48.33 0.012 48.492 0.038 ;
     RECT  48.51 0.012 48.708 0.038 ;
     RECT  48.726 0.012 48.888 0.038 ;
     RECT  48.906 0.012 49.104 0.038 ;
     RECT  49.122 0.012 49.284 0.038 ;
     RECT  49.302 0.012 49.464 0.038 ;
     RECT  49.482 0.012 49.68 0.038 ;
     RECT  49.698 0.012 49.86 0.038 ;
     RECT  49.878 0.012 50.04 0.038 ;
     RECT  50.058 0.012 50.256 0.038 ;
     RECT  0.576 0.038 50.274 0.235 ;
     RECT  0.576 0.235 50.382 16.907 ;
     RECT  0.576 16.907 50.274 18.221 ;
     RECT  0.576 18.221 49.878 18.797 ;
     RECT  0.756 18.797 49.878 19.535 ;
     RECT  1.152 19.535 49.878 19.643 ;
     RECT  1.152 19.643 49.554 20.687 ;
     RECT  1.836 20.687 49.554 21.271 ;
     RECT  1.836 21.271 49.734 43.295 ;
     RECT  1.98 43.295 49.734 43.799 ;
     RECT  2.052 43.799 49.734 46.229 ;
     RECT  2.16 46.229 49.734 46.921 ;
     RECT  2.16 46.921 49.77 47.659 ;
     RECT  50.796 47.821 50.814 47.857 ;
     RECT  1.764 47.659 49.77 48.085 ;
     RECT  1.116 48.085 49.77 48.271 ;
     RECT  50.796 47.857 51.174 48.397 ;
     RECT  0.792 48.271 49.77 48.413 ;
     RECT  1.764 48.413 49.77 48.667 ;
     RECT  50.724 48.397 51.174 48.667 ;
     RECT  0.792 48.413 0.81 48.811 ;
     RECT  1.764 48.667 51.174 49.171 ;
     RECT  0.576 48.811 0.81 49.351 ;
     RECT  1.548 49.171 51.174 49.351 ;
     RECT  0.576 49.351 51.174 51.802 ;
     RECT  0.594 51.802 0.792 51.821 ;
     RECT  0.81 51.802 0.972 51.821 ;
     RECT  0.99 51.802 1.188 51.821 ;
     RECT  1.206 51.802 1.368 51.821 ;
     RECT  1.386 51.802 1.548 51.821 ;
     RECT  1.566 51.802 1.764 51.821 ;
     RECT  1.782 51.802 1.944 51.821 ;
     RECT  1.962 51.802 2.16 51.821 ;
     RECT  2.178 51.802 2.34 51.821 ;
     RECT  2.358 51.802 2.556 51.821 ;
     RECT  2.574 51.802 2.736 51.821 ;
     RECT  2.754 51.802 2.952 51.821 ;
     RECT  2.97 51.802 3.132 51.821 ;
     RECT  3.15 51.802 3.348 51.821 ;
     RECT  3.366 51.802 3.528 51.821 ;
     RECT  3.546 51.802 3.744 51.821 ;
     RECT  3.762 51.802 3.924 51.821 ;
     RECT  3.942 51.802 4.14 51.821 ;
     RECT  4.158 51.802 4.32 51.821 ;
     RECT  4.338 51.802 4.5 51.821 ;
     RECT  4.518 51.802 4.716 51.821 ;
     RECT  4.734 51.802 4.896 51.821 ;
     RECT  4.914 51.802 5.112 51.821 ;
     RECT  5.13 51.802 5.292 51.821 ;
     RECT  5.31 51.802 5.508 51.821 ;
     RECT  5.526 51.802 5.688 51.821 ;
     RECT  5.706 51.802 5.904 51.821 ;
     RECT  5.922 51.802 6.084 51.821 ;
     RECT  6.102 51.802 6.3 51.821 ;
     RECT  6.318 51.802 6.48 51.821 ;
     RECT  6.498 51.802 6.696 51.821 ;
     RECT  6.714 51.802 6.876 51.821 ;
     RECT  6.894 51.802 7.056 51.821 ;
     RECT  7.074 51.802 7.272 51.821 ;
     RECT  7.29 51.802 7.452 51.821 ;
     RECT  7.47 51.802 7.668 51.821 ;
     RECT  7.686 51.802 7.848 51.821 ;
     RECT  7.866 51.802 8.064 51.821 ;
     RECT  8.082 51.802 8.244 51.821 ;
     RECT  8.262 51.802 8.46 51.821 ;
     RECT  8.478 51.802 8.64 51.821 ;
     RECT  8.658 51.802 8.856 51.821 ;
     RECT  8.874 51.802 9.036 51.821 ;
     RECT  9.054 51.802 9.252 51.821 ;
     RECT  9.27 51.802 9.432 51.821 ;
     RECT  9.45 51.802 9.648 51.821 ;
     RECT  9.666 51.802 9.828 51.821 ;
     RECT  9.846 51.802 10.008 51.821 ;
     RECT  10.026 51.802 10.224 51.821 ;
     RECT  10.242 51.802 10.404 51.821 ;
     RECT  10.422 51.802 10.62 51.821 ;
     RECT  10.638 51.802 10.8 51.821 ;
     RECT  10.818 51.802 11.016 51.821 ;
     RECT  11.034 51.802 11.196 51.821 ;
     RECT  11.214 51.802 11.412 51.821 ;
     RECT  11.43 51.802 11.592 51.821 ;
     RECT  11.61 51.802 11.808 51.821 ;
     RECT  11.826 51.802 11.988 51.821 ;
     RECT  12.006 51.802 12.204 51.821 ;
     RECT  12.222 51.802 12.384 51.821 ;
     RECT  12.402 51.802 12.6 51.821 ;
     RECT  12.618 51.802 12.78 51.821 ;
     RECT  12.798 51.802 12.96 51.821 ;
     RECT  12.978 51.802 13.176 51.821 ;
     RECT  13.194 51.802 13.356 51.821 ;
     RECT  13.374 51.802 13.572 51.821 ;
     RECT  13.59 51.802 13.752 51.821 ;
     RECT  13.77 51.802 13.968 51.821 ;
     RECT  13.986 51.802 14.148 51.821 ;
     RECT  14.166 51.802 14.364 51.821 ;
     RECT  14.382 51.802 14.544 51.821 ;
     RECT  14.562 51.802 14.76 51.821 ;
     RECT  14.778 51.802 14.94 51.821 ;
     RECT  14.958 51.802 15.156 51.821 ;
     RECT  15.174 51.802 15.336 51.821 ;
     RECT  15.354 51.802 15.516 51.821 ;
     RECT  15.534 51.802 15.732 51.821 ;
     RECT  15.75 51.802 15.912 51.821 ;
     RECT  15.93 51.802 16.128 51.821 ;
     RECT  16.146 51.802 16.308 51.821 ;
     RECT  16.326 51.802 16.524 51.821 ;
     RECT  16.542 51.802 16.704 51.821 ;
     RECT  16.722 51.802 16.92 51.821 ;
     RECT  16.938 51.802 17.1 51.821 ;
     RECT  17.118 51.802 17.316 51.821 ;
     RECT  17.334 51.802 17.496 51.821 ;
     RECT  17.514 51.802 17.712 51.821 ;
     RECT  17.73 51.802 17.892 51.821 ;
     RECT  17.91 51.802 18.108 51.821 ;
     RECT  18.126 51.802 18.288 51.821 ;
     RECT  18.306 51.802 18.468 51.821 ;
     RECT  18.486 51.802 18.684 51.821 ;
     RECT  18.702 51.802 18.864 51.821 ;
     RECT  18.882 51.802 19.08 51.821 ;
     RECT  19.098 51.802 19.26 51.821 ;
     RECT  19.278 51.802 19.476 51.821 ;
     RECT  19.494 51.802 19.656 51.821 ;
     RECT  19.674 51.802 19.872 51.821 ;
     RECT  19.89 51.802 20.052 51.821 ;
     RECT  20.07 51.802 20.268 51.821 ;
     RECT  20.286 51.802 20.448 51.821 ;
     RECT  20.466 51.802 20.664 51.821 ;
     RECT  20.682 51.802 20.844 51.821 ;
     RECT  20.862 51.802 21.06 51.821 ;
     RECT  21.078 51.802 21.24 51.821 ;
     RECT  21.258 51.802 21.42 51.821 ;
     RECT  21.438 51.802 21.636 51.821 ;
     RECT  21.654 51.802 21.816 51.821 ;
     RECT  21.834 51.802 22.032 51.821 ;
     RECT  22.05 51.802 22.212 51.821 ;
     RECT  22.23 51.802 22.428 51.821 ;
     RECT  22.446 51.802 22.608 51.821 ;
     RECT  22.626 51.802 22.824 51.821 ;
     RECT  22.842 51.802 23.004 51.821 ;
     RECT  23.022 51.802 23.22 51.821 ;
     RECT  23.238 51.802 23.4 51.821 ;
     RECT  23.418 51.802 23.616 51.821 ;
     RECT  23.634 51.802 23.796 51.821 ;
     RECT  23.814 51.802 23.976 51.821 ;
     RECT  23.994 51.802 24.192 51.821 ;
     RECT  24.21 51.802 24.372 51.821 ;
     RECT  24.39 51.802 24.588 51.821 ;
     RECT  24.606 51.802 24.768 51.821 ;
     RECT  24.786 51.802 24.984 51.821 ;
     RECT  25.002 51.802 25.164 51.821 ;
     RECT  25.182 51.802 25.38 51.821 ;
     RECT  25.398 51.802 25.56 51.821 ;
     RECT  25.578 51.802 25.776 51.821 ;
     RECT  25.794 51.802 25.956 51.821 ;
     RECT  25.974 51.802 26.172 51.821 ;
     RECT  26.19 51.802 26.352 51.821 ;
     RECT  26.37 51.802 26.568 51.821 ;
     RECT  26.586 51.802 26.748 51.821 ;
     RECT  26.766 51.802 26.928 51.821 ;
     RECT  26.946 51.802 27.144 51.821 ;
     RECT  27.162 51.802 27.324 51.821 ;
     RECT  27.342 51.802 27.54 51.821 ;
     RECT  27.558 51.802 27.72 51.821 ;
     RECT  27.738 51.802 27.936 51.821 ;
     RECT  27.954 51.802 28.116 51.821 ;
     RECT  28.134 51.802 28.332 51.821 ;
     RECT  28.35 51.802 28.512 51.821 ;
     RECT  28.53 51.802 28.728 51.821 ;
     RECT  28.746 51.802 28.908 51.821 ;
     RECT  28.926 51.802 29.124 51.821 ;
     RECT  29.142 51.802 29.304 51.821 ;
     RECT  29.322 51.802 29.52 51.821 ;
     RECT  29.538 51.802 29.7 51.821 ;
     RECT  29.718 51.802 29.88 51.821 ;
     RECT  29.898 51.802 30.096 51.821 ;
     RECT  30.114 51.802 30.276 51.821 ;
     RECT  30.294 51.802 30.492 51.821 ;
     RECT  30.51 51.802 30.672 51.821 ;
     RECT  30.69 51.802 30.888 51.821 ;
     RECT  30.906 51.802 31.068 51.821 ;
     RECT  31.086 51.802 31.284 51.821 ;
     RECT  31.302 51.802 31.464 51.821 ;
     RECT  31.482 51.802 31.68 51.821 ;
     RECT  31.698 51.802 31.86 51.821 ;
     RECT  31.878 51.802 32.076 51.821 ;
     RECT  32.094 51.802 32.256 51.821 ;
     RECT  32.274 51.802 32.436 51.821 ;
     RECT  32.454 51.802 32.652 51.821 ;
     RECT  32.67 51.802 32.832 51.821 ;
     RECT  32.85 51.802 33.048 51.821 ;
     RECT  33.066 51.802 33.228 51.821 ;
     RECT  33.246 51.802 33.444 51.821 ;
     RECT  33.462 51.802 33.624 51.821 ;
     RECT  33.642 51.802 33.84 51.821 ;
     RECT  33.858 51.802 34.02 51.821 ;
     RECT  34.038 51.802 34.236 51.821 ;
     RECT  34.254 51.802 34.416 51.821 ;
     RECT  34.434 51.802 34.632 51.821 ;
     RECT  34.65 51.802 34.812 51.821 ;
     RECT  34.83 51.802 35.028 51.821 ;
     RECT  35.046 51.802 35.208 51.821 ;
     RECT  35.226 51.802 35.388 51.821 ;
     RECT  35.406 51.802 35.604 51.821 ;
     RECT  35.622 51.802 35.784 51.821 ;
     RECT  35.802 51.802 36 51.821 ;
     RECT  36.018 51.802 36.18 51.821 ;
     RECT  36.198 51.802 36.396 51.821 ;
     RECT  36.414 51.802 36.576 51.821 ;
     RECT  36.594 51.802 36.792 51.821 ;
     RECT  36.81 51.802 36.972 51.821 ;
     RECT  36.99 51.802 37.188 51.821 ;
     RECT  37.206 51.802 37.368 51.821 ;
     RECT  37.386 51.802 37.584 51.821 ;
     RECT  37.602 51.802 37.764 51.821 ;
     RECT  37.782 51.802 37.98 51.821 ;
     RECT  37.998 51.802 38.16 51.821 ;
     RECT  38.178 51.802 38.34 51.821 ;
     RECT  38.358 51.802 38.556 51.821 ;
     RECT  38.574 51.802 38.736 51.821 ;
     RECT  38.754 51.802 38.952 51.821 ;
     RECT  38.97 51.802 39.132 51.821 ;
     RECT  39.15 51.802 39.348 51.821 ;
     RECT  39.366 51.802 39.528 51.821 ;
     RECT  39.546 51.802 39.744 51.821 ;
     RECT  39.762 51.802 39.924 51.821 ;
     RECT  39.942 51.802 40.14 51.821 ;
     RECT  40.158 51.802 40.32 51.821 ;
     RECT  40.338 51.802 40.536 51.821 ;
     RECT  40.554 51.802 40.716 51.821 ;
     RECT  40.734 51.802 40.896 51.821 ;
     RECT  40.914 51.802 41.112 51.821 ;
     RECT  41.13 51.802 41.292 51.821 ;
     RECT  41.31 51.802 41.508 51.821 ;
     RECT  41.526 51.802 41.688 51.821 ;
     RECT  41.706 51.802 41.904 51.821 ;
     RECT  41.922 51.802 42.084 51.821 ;
     RECT  42.102 51.802 42.3 51.821 ;
     RECT  42.318 51.802 42.48 51.821 ;
     RECT  42.498 51.802 42.696 51.821 ;
     RECT  42.714 51.802 42.876 51.821 ;
     RECT  42.894 51.802 43.092 51.821 ;
     RECT  43.11 51.802 43.272 51.821 ;
     RECT  43.29 51.802 43.488 51.821 ;
     RECT  43.506 51.802 43.668 51.821 ;
     RECT  43.686 51.802 43.848 51.821 ;
     RECT  43.866 51.802 44.064 51.821 ;
     RECT  44.082 51.802 44.244 51.821 ;
     RECT  44.262 51.802 44.46 51.821 ;
     RECT  44.478 51.802 44.64 51.821 ;
     RECT  44.658 51.802 44.856 51.821 ;
     RECT  44.874 51.802 45.036 51.821 ;
     RECT  45.054 51.802 45.252 51.821 ;
     RECT  45.27 51.802 45.432 51.821 ;
     RECT  45.45 51.802 45.648 51.821 ;
     RECT  45.666 51.802 45.828 51.821 ;
     RECT  45.846 51.802 46.044 51.821 ;
     RECT  46.062 51.802 46.224 51.821 ;
     RECT  46.242 51.802 46.44 51.821 ;
     RECT  46.458 51.802 46.62 51.821 ;
     RECT  46.638 51.802 46.8 51.821 ;
     RECT  46.818 51.802 47.016 51.821 ;
     RECT  47.034 51.802 47.196 51.821 ;
     RECT  47.214 51.802 47.412 51.821 ;
     RECT  47.43 51.802 47.592 51.821 ;
     RECT  47.61 51.802 47.808 51.821 ;
     RECT  47.826 51.802 47.988 51.821 ;
     RECT  48.006 51.802 48.204 51.821 ;
     RECT  48.222 51.802 48.384 51.821 ;
     RECT  48.402 51.802 48.6 51.821 ;
     RECT  48.618 51.802 48.78 51.821 ;
     RECT  48.798 51.802 48.996 51.821 ;
     RECT  49.014 51.802 49.176 51.821 ;
     RECT  49.194 51.802 49.356 51.821 ;
     RECT  49.374 51.802 49.572 51.821 ;
     RECT  49.59 51.802 49.752 51.821 ;
     RECT  49.77 51.802 49.968 51.821 ;
     RECT  49.986 51.802 50.148 51.821 ;
     RECT  50.166 51.802 50.364 51.821 ;
     RECT  50.382 51.802 50.544 51.821 ;
     RECT  50.562 51.802 50.76 51.821 ;
     RECT  50.778 51.802 50.94 51.821 ;
     RECT  50.958 51.802 51.156 51.821 ;
    LAYER M4 ;
     RECT  0.661 17.664 0.853 17.688 ;
     RECT  0.853 17.664 1.045 17.736 ;
     RECT  0.853 48.096 1.045 48.12 ;
     RECT  1.045 48.096 1.145 48.408 ;
     RECT  0.661 49.536 1.237 49.56 ;
     RECT  1.237 18.816 1.429 18.84 ;
     RECT  1.237 49.536 1.669 50.184 ;
     RECT  1.045 17.664 1.813 17.784 ;
     RECT  1.429 18.816 1.813 19.464 ;
     RECT  1.145 48.144 1.82 48.408 ;
     RECT  1.669 49.536 1.82 50.712 ;
     RECT  2.197 20.544 2.285 20.568 ;
     RECT  2.252 37.2 2.293 37.224 ;
     RECT  1.82 48.144 2.293 50.712 ;
     RECT  1.825 2.304 2.408 2.328 ;
     RECT  1.813 17.664 2.408 19.464 ;
     RECT  2.285 20.544 2.408 21.144 ;
     RECT  1.997 25.68 2.408 25.704 ;
     RECT  1.933 30.768 2.408 30.792 ;
     RECT  2.293 37.104 2.408 37.224 ;
     RECT  2.365 44.352 2.408 44.376 ;
     RECT  2.293 46.08 2.408 46.104 ;
     RECT  2.293 48.144 2.408 51.672 ;
     RECT  2.293 0.096 2.435 0.12 ;
     RECT  2.408 2.148 2.437 51.672 ;
     RECT  2.437 1.968 2.549 51.672 ;
     RECT  2.549 2.016 2.627 51.672 ;
     RECT  2.627 2.418 2.675 51.672 ;
     RECT  2.675 2.418 2.704 50.712 ;
     RECT  2.704 22.8 2.819 23.592 ;
     RECT  2.704 25.104 2.909 25.752 ;
     RECT  2.704 42.192 3.011 42.216 ;
     RECT  2.909 25.68 3.203 25.752 ;
     RECT  2.704 45.6 3.299 50.712 ;
     RECT  2.704 40.416 3.341 41.064 ;
     RECT  2.704 19.92 3.385 19.944 ;
     RECT  3.203 25.728 3.395 25.752 ;
     RECT  2.704 29.04 3.449 29.064 ;
     RECT  3.299 46.08 3.449 50.712 ;
     RECT  3.449 49.536 3.521 50.712 ;
     RECT  3.341 41.04 3.587 41.064 ;
     RECT  2.819 23.568 3.593 23.592 ;
     RECT  3.449 46.08 3.593 48.36 ;
     RECT  2.704 21.696 3.733 21.72 ;
     RECT  3.593 46.704 3.737 48.36 ;
     RECT  3.697 43.296 3.781 43.32 ;
     RECT  3.733 21.648 3.817 21.72 ;
     RECT  3.817 21.696 3.971 21.72 ;
     RECT  3.521 50.16 4.093 50.712 ;
     RECT  3.829 24.24 4.165 24.312 ;
     RECT  3.985 1.104 4.211 1.128 ;
     RECT  4.093 50.16 4.3 50.76 ;
     RECT  4.129 19.968 4.403 19.992 ;
     RECT  4.3 50.736 4.451 50.76 ;
     RECT  4.561 22.752 4.669 22.776 ;
     RECT  4.549 1.152 4.745 1.176 ;
     RECT  3.737 46.704 4.777 47.304 ;
     RECT  3.737 48.336 4.777 48.36 ;
     RECT  4.777 46.704 4.817 48.36 ;
     RECT  4.789 42.72 5.033 42.744 ;
     RECT  4.165 24.24 5.125 24.936 ;
     RECT  2.704 44.352 5.137 44.472 ;
     RECT  5.132 49.152 5.173 49.176 ;
     RECT  4.669 22.224 5.18 22.776 ;
     RECT  5.125 23.952 5.18 24.936 ;
     RECT  5.173 49.152 5.219 49.608 ;
     RECT  5.18 22.224 5.221 24.936 ;
     RECT  4.981 29.04 5.249 29.064 ;
     RECT  5.221 22.176 5.267 24.936 ;
     RECT  5.137 44.352 5.276 45.048 ;
     RECT  4.817 46.704 5.276 47.928 ;
     RECT  5.276 44.352 5.363 47.928 ;
     RECT  5.363 46.176 5.429 47.928 ;
     RECT  5.219 49.488 5.537 49.608 ;
     RECT  5.429 46.176 5.555 47.352 ;
     RECT  5.125 0.096 5.641 0.12 ;
     RECT  5.267 23.952 5.825 24.936 ;
     RECT  5.641 0.096 5.897 0.552 ;
     RECT  5.555 46.176 6.131 47.304 ;
     RECT  5.597 50.016 6.185 50.136 ;
     RECT  5.897 0.528 6.217 0.552 ;
     RECT  6.181 49.008 6.268 49.032 ;
     RECT  5.825 24.48 6.469 24.936 ;
     RECT  5.267 22.176 6.505 22.2 ;
     RECT  6.217 0.528 6.515 1.128 ;
     RECT  5.363 44.352 6.565 44.376 ;
     RECT  6.185 50.112 6.581 50.136 ;
     RECT  6.565 44.352 6.653 44.472 ;
     RECT  2.704 26.736 6.661 26.76 ;
     RECT  6.397 3.936 6.685 3.96 ;
     RECT  6.505 21.648 6.707 22.2 ;
     RECT  6.613 28.08 6.757 28.104 ;
     RECT  6.469 24.48 6.793 25.08 ;
     RECT  6.793 24.48 7.045 25.704 ;
     RECT  7.141 29.664 7.333 29.688 ;
     RECT  6.505 30.768 7.333 30.792 ;
     RECT  6.131 47.04 7.513 47.304 ;
     RECT  6.515 0.528 7.621 0.552 ;
     RECT  7.045 23.904 7.669 25.704 ;
     RECT  6.707 22.176 7.801 22.2 ;
     RECT  6.236 2.832 7.808 2.856 ;
     RECT  6.685 3.936 7.808 4.536 ;
     RECT  7.801 22.032 7.808 22.2 ;
     RECT  7.669 23.328 7.808 25.704 ;
     RECT  6.757 28.08 7.808 28.488 ;
     RECT  7.333 29.664 7.808 30.792 ;
     RECT  6.653 44.352 7.808 44.376 ;
     RECT  7.573 45.552 7.808 45.576 ;
     RECT  7.513 46.752 7.808 47.304 ;
     RECT  6.361 48.336 7.808 48.36 ;
     RECT  7.729 50.112 7.808 50.136 ;
     RECT  7.621 0.528 7.859 0.648 ;
     RECT  6.949 51.696 8.099 51.72 ;
     RECT  7.808 2.148 8.104 50.136 ;
     RECT  8.104 23.28 8.165 23.352 ;
     RECT  8.104 21.12 8.243 22.056 ;
     RECT  8.104 49.536 8.3 50.136 ;
     RECT  8.3 49.536 8.387 50.76 ;
     RECT  8.197 1.68 8.597 1.704 ;
     RECT  8.104 24.48 8.675 24.936 ;
     RECT  8.104 26.496 8.675 26.52 ;
     RECT  8.104 47.04 8.741 48.456 ;
     RECT  8.387 49.536 8.885 50.136 ;
     RECT  8.005 0.096 9.173 0.168 ;
     RECT  8.243 22.032 9.205 22.056 ;
     RECT  8.165 23.28 9.205 23.304 ;
     RECT  9.205 22.032 9.241 23.304 ;
     RECT  8.675 24.48 9.241 24.504 ;
     RECT  9.241 22.032 9.281 24.504 ;
     RECT  8.885 50.064 9.281 50.136 ;
     RECT  8.104 28.416 9.317 29.112 ;
     RECT  9.281 50.064 9.353 50.088 ;
     RECT  9.173 0.144 9.389 0.168 ;
     RECT  8.104 44.352 9.497 44.376 ;
     RECT  9.281 22.752 9.605 24.504 ;
     RECT  9.541 26.736 9.709 26.76 ;
     RECT  9.673 42.768 9.779 42.792 ;
     RECT  9.317 28.416 9.785 28.536 ;
     RECT  9.709 26.208 9.788 26.76 ;
     RECT  9.788 25.344 9.821 26.76 ;
     RECT  9.785 28.416 9.821 28.44 ;
     RECT  8.741 47.04 9.821 48.12 ;
     RECT  9.821 25.344 9.875 26.232 ;
     RECT  9.745 18.816 9.97 18.84 ;
     RECT  9.925 49.008 10.145 49.032 ;
     RECT  9.97 18.816 10.163 18.888 ;
     RECT  9.925 41.616 10.163 41.64 ;
     RECT  10.277 0.096 10.645 0.12 ;
     RECT  10.141 27.888 10.693 27.912 ;
     RECT  9.875 26.208 10.829 26.232 ;
     RECT  10.645 0.096 10.931 0.552 ;
     RECT  10.309 50.688 11.044 50.712 ;
     RECT  11.044 50.64 11.045 50.712 ;
     RECT  10.931 0.096 11.153 0.12 ;
     RECT  10.693 27.36 11.221 27.912 ;
     RECT  11.045 50.64 11.225 50.664 ;
     RECT  9.605 22.752 11.315 23.976 ;
     RECT  11.269 49.536 11.369 49.56 ;
     RECT  11.221 27.36 11.411 28.536 ;
     RECT  11.42 4.512 11.507 4.536 ;
     RECT  10.357 21.552 11.549 21.576 ;
     RECT  11.437 45.6 11.555 45.624 ;
     RECT  11.315 22.752 11.653 23.4 ;
     RECT  10.163 18.816 11.689 18.84 ;
     RECT  11.411 27.36 11.689 27.912 ;
     RECT  11.689 27.312 11.729 27.912 ;
     RECT  11.689 18.816 11.765 18.936 ;
     RECT  11.765 18.912 11.939 18.936 ;
     RECT  11.701 31.008 11.981 31.032 ;
     RECT  11.893 33.024 11.981 33.048 ;
     RECT  12.013 5.088 12.131 5.112 ;
     RECT  9.821 47.04 12.277 47.928 ;
     RECT  12.085 51.696 12.341 51.72 ;
     RECT  11.653 21.648 12.697 23.4 ;
     RECT  11.905 29.088 12.697 29.4 ;
     RECT  12.337 0.528 12.707 0.552 ;
     RECT  12.661 50.112 12.812 50.136 ;
     RECT  12.812 50.112 12.899 50.76 ;
     RECT  12.733 30.768 13.052 30.792 ;
     RECT  13.052 6.816 13.208 6.84 ;
     RECT  12.697 21.648 13.208 24.024 ;
     RECT  11.689 25.632 13.208 25.656 ;
     RECT  11.729 27.312 13.208 27.336 ;
     RECT  12.697 28.512 13.208 29.4 ;
     RECT  13.052 30.768 13.208 30.84 ;
     RECT  12.469 32.448 13.208 32.472 ;
     RECT  12.277 47.04 13.208 48.456 ;
     RECT  12.899 50.112 13.208 50.136 ;
     RECT  13.208 2.148 13.312 50.136 ;
     RECT  13.312 2.418 13.504 50.136 ;
     RECT  13.093 0.144 13.619 0.168 ;
     RECT  13.504 27.936 13.673 28.824 ;
     RECT  13.504 24.48 13.817 24.504 ;
     RECT  13.504 3.936 13.859 3.96 ;
     RECT  13.504 18.816 14.051 18.84 ;
     RECT  13.504 45.552 14.099 45.624 ;
     RECT  13.504 5.088 14.243 5.112 ;
     RECT  14.099 45.552 14.249 45.576 ;
     RECT  13.504 6.24 14.435 6.264 ;
     RECT  13.504 47.04 14.485 47.88 ;
     RECT  13.504 21.264 14.497 21.288 ;
     RECT  13.504 23.28 14.497 23.352 ;
     RECT  14.485 47.04 14.531 48.504 ;
     RECT  13.504 49.536 14.573 50.136 ;
     RECT  14.497 21.264 14.605 22.248 ;
     RECT  14.497 23.28 14.605 23.832 ;
     RECT  14.605 21.264 14.627 23.832 ;
     RECT  14.531 47.856 14.681 48.504 ;
     RECT  14.485 31.584 14.713 31.608 ;
     RECT  13.504 25.92 14.753 26.808 ;
     RECT  14.713 31.584 14.773 31.944 ;
     RECT  14.681 48.432 14.789 48.504 ;
     RECT  14.773 31.008 14.819 31.944 ;
     RECT  14.573 49.584 14.821 50.136 ;
     RECT  14.627 22.656 14.861 23.832 ;
     RECT  14.821 3.936 15.011 3.96 ;
     RECT  14.821 49.584 15.013 50.184 ;
     RECT  14.819 31.008 15.073 31.608 ;
     RECT  14.857 46.752 15.203 46.776 ;
     RECT  14.861 22.848 15.349 23.832 ;
     RECT  15.308 0.096 15.395 0.12 ;
     RECT  15.205 33.648 15.473 33.672 ;
     RECT  15.013 49.584 15.545 50.712 ;
     RECT  15.397 18.816 15.587 18.84 ;
     RECT  15.685 47.328 15.779 47.352 ;
     RECT  15.545 50.112 15.797 50.712 ;
     RECT  13.673 27.936 15.829 27.96 ;
     RECT  14.627 21.264 15.901 21.288 ;
     RECT  15.901 21.264 15.941 21.672 ;
     RECT  14.753 26.208 15.973 26.808 ;
     RECT  15.829 27.936 15.973 28.488 ;
     RECT  15.973 26.208 16.019 28.488 ;
     RECT  16.019 28.464 16.085 28.488 ;
     RECT  15.797 50.688 16.093 50.712 ;
     RECT  15.349 22.848 16.117 24.36 ;
     RECT  16.019 26.208 16.193 27.384 ;
     RECT  15.901 29.616 16.225 29.64 ;
     RECT  16.213 46.704 16.337 46.728 ;
     RECT  16.225 29.616 16.405 29.688 ;
     RECT  16.193 26.736 16.481 27.384 ;
     RECT  15.941 21.648 16.517 21.672 ;
     RECT  16.405 28.848 16.517 29.688 ;
     RECT  14.789 48.432 16.549 48.456 ;
     RECT  15.073 30.816 16.585 31.608 ;
     RECT  16.549 48.432 16.643 48.504 ;
     RECT  16.117 22.848 16.657 24.504 ;
     RECT  16.517 29.664 16.721 29.688 ;
     RECT  16.585 30.768 16.721 31.608 ;
     RECT  16.721 29.664 16.741 31.608 ;
     RECT  16.481 26.736 16.769 26.76 ;
     RECT  16.789 51.696 16.877 51.72 ;
     RECT  16.657 22.848 16.883 25.224 ;
     RECT  16.883 22.848 17.053 24.12 ;
     RECT  16.357 0.144 17.077 0.168 ;
     RECT  17.036 1.152 17.077 1.176 ;
     RECT  15.973 5.088 17.077 5.112 ;
     RECT  16.643 48.432 17.084 48.456 ;
     RECT  16.741 29.664 17.093 31.896 ;
     RECT  17.077 0.096 17.123 1.176 ;
     RECT  17.077 5.088 17.123 5.736 ;
     RECT  17.084 47.856 17.171 48.456 ;
     RECT  17.123 5.712 17.201 5.736 ;
     RECT  17.093 29.664 17.201 31.8 ;
     RECT  17.123 0.096 17.219 1.08 ;
     RECT  17.132 50.16 17.219 50.184 ;
     RECT  17.201 30.24 17.315 31.8 ;
     RECT  17.365 46.128 17.489 46.152 ;
     RECT  17.413 18.816 17.507 18.84 ;
     RECT  17.665 50.736 17.843 50.808 ;
     RECT  17.269 27.888 18.181 27.912 ;
     RECT  17.621 6.288 18.197 6.312 ;
     RECT  17.053 22.752 18.277 24.12 ;
     RECT  17.171 48.144 18.325 48.168 ;
     RECT  17.593 49.536 18.325 49.56 ;
     RECT  17.843 50.784 18.325 50.808 ;
     RECT  18.325 50.784 18.469 51.672 ;
     RECT  18.181 27.888 18.493 28.488 ;
     RECT  18.061 2.256 18.608 2.28 ;
     RECT  18.197 6.288 18.608 6.888 ;
     RECT  18.277 22.752 18.608 24.168 ;
     RECT  16.883 25.2 18.608 25.224 ;
     RECT  18.493 27.408 18.608 28.488 ;
     RECT  18.469 29.76 18.608 29.784 ;
     RECT  17.315 30.96 18.608 31.8 ;
     RECT  18.341 45.552 18.608 45.576 ;
     RECT  18.325 48.144 18.608 49.56 ;
     RECT  18.469 50.784 18.611 51.72 ;
     RECT  18.608 2.148 18.712 49.692 ;
     RECT  18.611 50.784 18.803 51.672 ;
     RECT  18.712 2.418 18.904 49.422 ;
     RECT  18.904 29.04 19.001 29.784 ;
     RECT  18.469 0.144 19.043 0.168 ;
     RECT  18.904 21.648 19.091 22.488 ;
     RECT  18.904 24.096 19.289 26.136 ;
     RECT  18.949 50.688 19.619 50.76 ;
     RECT  18.904 3.408 19.649 3.432 ;
     RECT  19.001 29.04 19.801 29.112 ;
     RECT  19.289 26.112 19.859 26.136 ;
     RECT  18.904 30.96 19.859 32.472 ;
     RECT  18.904 47.28 19.937 48.168 ;
     RECT  19.289 24.096 19.973 25.128 ;
     RECT  19.091 21.648 20.045 21.672 ;
     RECT  19.969 7.392 20.243 7.416 ;
     RECT  19.619 50.688 20.261 50.712 ;
     RECT  19.937 48.144 20.369 48.168 ;
     RECT  18.904 34.8 20.477 34.824 ;
     RECT  20.341 28.848 20.513 28.872 ;
     RECT  18.904 27.312 20.533 27.624 ;
     RECT  20.533 26.736 20.579 28.2 ;
     RECT  18.904 5.088 20.627 5.112 ;
     RECT  20.579 26.736 20.801 26.76 ;
     RECT  20.581 30.096 20.819 30.12 ;
     RECT  20.401 22.224 21.011 22.632 ;
     RECT  20.725 48.96 21.053 49.032 ;
     RECT  19.973 24.096 21.109 24.12 ;
     RECT  21.011 22.608 21.193 22.632 ;
     RECT  21.109 23.712 21.193 24.12 ;
     RECT  21.193 22.608 21.233 24.12 ;
     RECT  19.973 25.104 21.233 25.128 ;
     RECT  20.579 27.936 21.233 28.2 ;
     RECT  21.233 22.8 21.299 24.12 ;
     RECT  21.233 27.936 21.313 27.96 ;
     RECT  21.299 22.8 21.395 23.88 ;
     RECT  20.533 50.112 21.541 50.136 ;
     RECT  18.904 18.816 21.587 18.84 ;
     RECT  19.957 51.696 21.593 51.72 ;
     RECT  21.541 50.112 21.665 50.712 ;
     RECT  21.481 29.616 21.779 29.64 ;
     RECT  21.665 50.112 21.841 50.136 ;
     RECT  21.395 23.328 22.097 23.88 ;
     RECT  21.841 49.584 22.117 50.136 ;
     RECT  21.733 47.328 22.177 47.352 ;
     RECT  22.117 49.392 22.241 50.136 ;
     RECT  22.097 23.712 22.309 23.88 ;
     RECT  21.085 0.528 22.355 0.552 ;
     RECT  21.625 25.68 22.421 25.704 ;
     RECT  19.859 31.872 22.705 31.896 ;
     RECT  22.705 31.296 22.741 31.896 ;
     RECT  22.241 49.584 22.781 50.136 ;
     RECT  22.813 5.664 22.931 5.688 ;
     RECT  22.921 30.24 23.027 30.264 ;
     RECT  22.561 28.272 23.029 28.296 ;
     RECT  23.029 28.272 23.077 29.112 ;
     RECT  22.981 26.784 23.101 26.808 ;
     RECT  23.077 27.792 23.101 29.112 ;
     RECT  23.101 26.784 23.209 29.112 ;
     RECT  22.453 21.264 23.389 21.288 ;
     RECT  23.389 21.264 23.641 22.104 ;
     RECT  22.781 50.112 23.701 50.136 ;
     RECT  23.701 50.112 23.717 50.712 ;
     RECT  23.641 21.264 23.821 22.488 ;
     RECT  23.929 15.84 24.008 15.864 ;
     RECT  23.605 18.816 24.008 18.84 ;
     RECT  23.821 21.216 24.008 22.488 ;
     RECT  22.309 23.712 24.008 24.504 ;
     RECT  23.461 25.632 24.008 25.656 ;
     RECT  23.209 26.784 24.008 29.64 ;
     RECT  22.741 31.296 24.008 32.472 ;
     RECT  23.893 34.176 24.008 34.2 ;
     RECT  23.077 46.128 24.008 46.152 ;
     RECT  24.008 2.148 24.112 49.692 ;
     RECT  24.037 0.144 24.229 0.168 ;
     RECT  24.112 2.418 24.304 49.56 ;
     RECT  24.304 45.696 24.419 45.72 ;
     RECT  24.304 23.376 24.473 23.976 ;
     RECT  24.304 15.84 24.515 15.864 ;
     RECT  24.304 29.088 24.545 29.64 ;
     RECT  24.304 21.216 24.617 21.24 ;
     RECT  24.304 33.648 24.617 34.248 ;
     RECT  24.545 29.088 24.659 29.112 ;
     RECT  24.473 23.376 24.851 23.4 ;
     RECT  24.229 0.144 24.901 0.216 ;
     RECT  23.717 50.688 24.901 50.712 ;
     RECT  24.277 51.696 24.901 51.72 ;
     RECT  24.901 0.096 24.997 0.216 ;
     RECT  24.304 27.168 25.013 27.384 ;
     RECT  24.617 34.224 25.057 34.248 ;
     RECT  24.304 31.776 25.085 32.472 ;
     RECT  24.901 50.688 25.091 51.72 ;
     RECT  25.013 27.36 25.235 27.384 ;
     RECT  24.304 22.224 25.427 22.248 ;
     RECT  25.085 31.776 25.589 32.328 ;
     RECT  25.091 51.696 25.589 51.72 ;
     RECT  24.304 49.536 25.669 49.56 ;
     RECT  25.585 23.664 25.82 23.688 ;
     RECT  24.997 0.096 25.841 0.36 ;
     RECT  25.82 23.328 25.907 23.688 ;
     RECT  25.669 49.008 25.913 49.56 ;
     RECT  25.913 49.536 25.985 49.56 ;
     RECT  25.589 31.776 26.089 31.896 ;
     RECT  26.089 31.536 26.101 31.896 ;
     RECT  25.957 27.936 26.129 27.96 ;
     RECT  26.101 30.864 26.129 31.896 ;
     RECT  26.129 30.864 26.147 31.8 ;
     RECT  26.089 34.224 26.173 34.248 ;
     RECT  25.091 50.688 26.236 50.712 ;
     RECT  26.236 50.64 26.305 50.712 ;
     RECT  26.252 27.312 26.339 27.336 ;
     RECT  25.907 23.664 26.348 23.688 ;
     RECT  26.348 23.664 26.435 24.504 ;
     RECT  26.147 30.864 26.437 31.56 ;
     RECT  26.305 50.64 26.453 50.76 ;
     RECT  26.453 50.736 26.675 50.76 ;
     RECT  26.125 20.496 26.773 20.52 ;
     RECT  25.837 21.648 26.773 21.672 ;
     RECT  25.841 0.144 26.813 0.36 ;
     RECT  26.437 30.192 26.849 31.56 ;
     RECT  26.773 20.496 26.857 22.488 ;
     RECT  26.857 21.648 26.957 22.488 ;
     RECT  26.821 47.856 26.957 47.88 ;
     RECT  26.773 15.408 26.993 15.432 ;
     RECT  26.809 3.408 27.011 3.432 ;
     RECT  24.304 18.816 27.203 18.84 ;
     RECT  26.849 30.336 27.205 31.56 ;
     RECT  26.435 23.664 27.353 23.928 ;
     RECT  27.353 23.904 27.541 23.928 ;
     RECT  27.445 46.704 27.641 46.728 ;
     RECT  26.857 20.496 27.677 20.52 ;
     RECT  27.349 3.984 27.785 4.008 ;
     RECT  27.097 26.976 27.829 27 ;
     RECT  26.293 28.32 27.829 28.344 ;
     RECT  27.541 23.904 27.853 23.976 ;
     RECT  27.853 23.904 27.893 24.504 ;
     RECT  27.829 26.976 27.893 28.344 ;
     RECT  27.893 26.976 27.965 27.96 ;
     RECT  27.884 4.512 27.971 4.536 ;
     RECT  27.205 30.336 28.037 31.896 ;
     RECT  28.021 47.28 28.217 47.304 ;
     RECT  28.213 50.112 28.249 50.136 ;
     RECT  28.249 50.112 28.361 50.184 ;
     RECT  28.361 50.112 28.433 50.136 ;
     RECT  28.037 30.336 28.573 30.984 ;
     RECT  26.813 0.144 28.897 0.168 ;
     RECT  27.965 26.976 28.981 27.384 ;
     RECT  28.825 22.896 29.029 22.92 ;
     RECT  27.893 23.952 29.029 24.504 ;
     RECT  26.957 21.648 29.077 21.672 ;
     RECT  29.029 22.896 29.113 24.504 ;
     RECT  28.897 0.144 29.123 1.128 ;
     RECT  28.573 29.664 29.269 30.984 ;
     RECT  26.981 51.696 29.269 51.72 ;
     RECT  28.537 48.48 29.293 48.504 ;
     RECT  29.269 51.648 29.365 51.72 ;
     RECT  28.46 3.408 29.408 3.432 ;
     RECT  28.645 18.816 29.408 18.84 ;
     RECT  29.036 20.448 29.408 20.472 ;
     RECT  29.077 21.504 29.408 21.672 ;
     RECT  29.113 22.8 29.408 24.504 ;
     RECT  27.313 25.728 29.408 25.752 ;
     RECT  28.981 26.976 29.408 27.96 ;
     RECT  29.269 29.616 29.408 30.984 ;
     RECT  28.717 45.6 29.408 45.624 ;
     RECT  29.293 48.24 29.408 48.504 ;
     RECT  29.365 50.736 29.459 51.72 ;
     RECT  29.408 2.148 29.512 49.692 ;
     RECT  29.459 51.648 29.651 51.72 ;
     RECT  29.512 2.418 29.704 49.422 ;
     RECT  29.704 30.144 29.837 30.984 ;
     RECT  29.123 0.144 29.843 0.264 ;
     RECT  29.704 20.496 29.843 22.824 ;
     RECT  29.704 6.096 29.891 6.12 ;
     RECT  29.843 21.072 29.909 22.824 ;
     RECT  29.704 23.952 30.097 24.648 ;
     RECT  29.909 22.176 30.233 22.824 ;
     RECT  29.704 7.392 30.275 7.416 ;
     RECT  30.097 24.096 30.275 24.648 ;
     RECT  29.704 28.464 30.341 28.488 ;
     RECT  29.704 33.648 30.377 33.672 ;
     RECT  29.837 30.336 30.557 30.984 ;
     RECT  29.909 21.072 30.565 21.096 ;
     RECT  29.704 47.28 30.629 48.264 ;
     RECT  29.704 18.816 30.659 18.984 ;
     RECT  29.704 25.728 30.805 27.096 ;
     RECT  30.557 30.768 30.809 30.984 ;
     RECT  30.629 47.328 30.809 48.264 ;
     RECT  30.805 25.728 30.889 27.384 ;
     RECT  29.651 51.696 30.916 51.72 ;
     RECT  30.809 47.328 31.043 48.12 ;
     RECT  29.843 0.144 31.381 0.168 ;
     RECT  30.233 22.176 31.385 22.2 ;
     RECT  31.381 0.144 31.417 0.264 ;
     RECT  31.381 49.536 31.564 49.56 ;
     RECT  31.564 49.536 31.565 49.608 ;
     RECT  31.417 0.144 31.781 0.552 ;
     RECT  31.565 49.584 31.781 49.608 ;
     RECT  30.275 24.096 31.849 24.552 ;
     RECT  30.889 25.728 31.889 26.76 ;
     RECT  31.021 28.944 31.957 28.968 ;
     RECT  31.765 22.128 31.961 22.152 ;
     RECT  31.916 4.512 32.003 4.536 ;
     RECT  31.916 27.792 32.003 27.816 ;
     RECT  30.916 51.648 32.029 51.72 ;
     RECT  32.029 50.736 32.177 51.72 ;
     RECT  31.849 24.096 32.209 24.6 ;
     RECT  30.809 30.864 32.209 30.984 ;
     RECT  32.209 30.864 32.317 31.128 ;
     RECT  32.149 46.128 32.321 46.152 ;
     RECT  31.957 28.944 32.353 29.784 ;
     RECT  32.353 27.936 32.393 29.784 ;
     RECT  32.317 30.768 32.429 31.128 ;
     RECT  32.209 23.952 32.437 24.6 ;
     RECT  32.149 3.408 32.465 3.432 ;
     RECT  32.437 23.568 32.483 24.6 ;
     RECT  32.483 23.568 32.497 23.592 ;
     RECT  31.889 25.728 32.501 25.752 ;
     RECT  32.533 46.704 32.681 46.728 ;
     RECT  31.043 48.096 32.725 48.12 ;
     RECT  32.725 47.856 32.897 48.12 ;
     RECT  32.497 22.224 32.963 23.592 ;
     RECT  31.889 26.736 32.965 26.76 ;
     RECT  32.965 26.208 33.005 26.76 ;
     RECT  33.068 2.832 33.155 2.856 ;
     RECT  32.483 24.576 33.581 24.6 ;
     RECT  32.393 27.936 33.613 28.488 ;
     RECT  32.429 31.104 33.797 31.128 ;
     RECT  31.781 0.144 34.081 0.168 ;
     RECT  32.963 22.224 34.117 22.488 ;
     RECT  32.963 23.568 34.117 23.592 ;
     RECT  32.897 48.096 34.309 48.12 ;
     RECT  33.109 49.536 34.309 49.56 ;
     RECT  32.177 50.736 34.547 50.76 ;
     RECT  33.005 26.208 34.585 26.232 ;
     RECT  33.613 27.36 34.585 28.488 ;
     RECT  34.081 0.144 34.657 0.264 ;
     RECT  34.117 22.224 34.693 23.592 ;
     RECT  32.393 29.76 34.693 29.784 ;
     RECT  34.477 2.256 34.808 2.28 ;
     RECT  34.225 7.392 34.808 7.416 ;
     RECT  30.659 18.816 34.808 18.84 ;
     RECT  31.309 20.592 34.808 20.616 ;
     RECT  34.693 22.224 34.808 24.12 ;
     RECT  34.585 26.208 34.808 28.488 ;
     RECT  34.693 29.76 34.808 30.168 ;
     RECT  34.309 48.096 34.808 49.56 ;
     RECT  34.808 2.148 34.912 49.692 ;
     RECT  34.657 0.144 35.093 1.128 ;
     RECT  34.912 2.256 35.104 49.422 ;
     RECT  35.093 0.144 35.219 0.264 ;
     RECT  35.104 20.592 35.219 24.504 ;
     RECT  35.104 27.888 35.237 28.488 ;
     RECT  35.219 20.592 35.273 22.488 ;
     RECT  35.273 21.12 35.309 22.488 ;
     RECT  35.104 2.256 35.315 2.28 ;
     RECT  35.237 27.888 35.381 28.44 ;
     RECT  35.104 29.76 35.381 30.216 ;
     RECT  35.104 18.816 35.507 18.888 ;
     RECT  35.507 18.864 35.699 18.888 ;
     RECT  34.885 51.648 35.701 51.72 ;
     RECT  35.381 29.76 35.813 30.168 ;
     RECT  35.104 26.544 35.921 26.568 ;
     RECT  35.381 27.888 36.097 28.2 ;
     RECT  35.701 50.688 36.131 51.72 ;
     RECT  36.097 27.36 36.275 28.2 ;
     RECT  35.813 29.76 36.313 29.784 ;
     RECT  35.219 0.144 36.421 0.168 ;
     RECT  36.313 29.664 36.467 29.784 ;
     RECT  35.309 21.12 36.469 21.672 ;
     RECT  35.104 48.096 36.469 48.12 ;
     RECT  36.469 21.12 36.515 22.44 ;
     RECT  36.515 21.648 36.556 22.44 ;
     RECT  36.467 29.76 36.605 29.784 ;
     RECT  36.275 27.744 36.613 28.2 ;
     RECT  36.421 0.144 36.659 0.552 ;
     RECT  36.469 48.096 36.812 48.456 ;
     RECT  35.219 23.568 36.817 24.504 ;
     RECT  36.817 23.568 36.853 24.552 ;
     RECT  36.812 48.096 36.899 48.504 ;
     RECT  36.853 23.376 37.043 24.552 ;
     RECT  37.249 30.96 37.285 30.984 ;
     RECT  37.285 30.24 37.427 30.984 ;
     RECT  37.043 23.568 37.433 24.552 ;
     RECT  36.131 50.688 37.469 50.712 ;
     RECT  37.532 20.208 37.619 20.232 ;
     RECT  36.781 18.816 37.621 18.84 ;
     RECT  36.613 27.744 37.645 28.488 ;
     RECT  37.645 27.36 37.649 28.488 ;
     RECT  37.669 45.552 37.757 45.576 ;
     RECT  37.649 27.36 37.811 28.44 ;
     RECT  37.933 15.408 38.017 15.432 ;
     RECT  37.861 50.112 38.081 50.136 ;
     RECT  37.433 23.568 38.195 24.504 ;
     RECT  38.053 33.648 38.225 33.672 ;
     RECT  38.195 23.568 38.257 24.024 ;
     RECT  36.131 51.696 38.333 51.72 ;
     RECT  36.899 48.096 38.429 48.12 ;
     RECT  38.257 23.376 38.473 24.024 ;
     RECT  38.429 48.096 38.513 49.032 ;
     RECT  37.427 30.96 38.545 30.984 ;
     RECT  37.811 27.936 38.577 28.44 ;
     RECT  38.473 22.8 38.579 24.024 ;
     RECT  38.545 30.96 38.629 31.896 ;
     RECT  38.629 46.704 38.729 46.728 ;
     RECT  38.629 30.816 38.771 31.896 ;
     RECT  38.513 48.096 38.821 48.216 ;
     RECT  36.659 0.144 38.876 0.168 ;
     RECT  38.876 0.144 38.963 0.552 ;
     RECT  36.556 21.648 38.981 21.672 ;
     RECT  38.821 47.28 38.981 48.216 ;
     RECT  38.577 28.416 39.017 28.44 ;
     RECT  38.972 49.584 39.059 49.608 ;
     RECT  39.013 18.816 39.121 18.84 ;
     RECT  38.771 30.864 39.161 31.896 ;
     RECT  38.579 23.568 39.205 24.024 ;
     RECT  38.981 48.192 39.617 48.216 ;
     RECT  38.545 29.76 39.733 29.784 ;
     RECT  39.205 23.568 39.829 24.84 ;
     RECT  38.963 0.144 40.021 0.264 ;
     RECT  39.589 50.16 40.067 50.184 ;
     RECT  40.021 0.144 40.069 0.696 ;
     RECT  38.041 26.256 40.093 26.28 ;
     RECT  40.069 51.648 40.165 51.672 ;
     RECT  39.481 15.408 40.208 15.432 ;
     RECT  39.121 18.816 40.208 18.888 ;
     RECT  39.337 21.504 40.208 21.528 ;
     RECT  39.829 23.328 40.208 24.84 ;
     RECT  40.093 26.256 40.208 26.664 ;
     RECT  39.733 29.52 40.208 29.784 ;
     RECT  39.161 30.864 40.208 30.888 ;
     RECT  39.161 31.872 40.208 31.896 ;
     RECT  39.949 34.752 40.208 34.776 ;
     RECT  40.069 39.312 40.208 39.336 ;
     RECT  39.404 46.176 40.208 46.2 ;
     RECT  39.617 48.192 40.208 49.032 ;
     RECT  40.165 50.736 40.259 51.672 ;
     RECT  40.069 0.144 40.307 0.792 ;
     RECT  40.208 2.148 40.312 49.692 ;
     RECT  40.259 51.648 40.451 51.672 ;
     RECT  40.312 2.418 40.504 49.422 ;
     RECT  40.504 18.816 40.691 18.888 ;
     RECT  40.504 21.504 40.817 23.592 ;
     RECT  40.691 18.864 40.883 18.888 ;
     RECT  40.504 25.056 40.961 26.808 ;
     RECT  40.504 48.192 40.961 48.456 ;
     RECT  40.307 0.144 41.075 0.552 ;
     RECT  40.817 22.464 41.141 23.592 ;
     RECT  40.504 29.088 41.141 30.888 ;
     RECT  41.141 30.192 41.219 30.888 ;
     RECT  40.961 25.056 41.356 26.76 ;
     RECT  40.504 15.408 41.507 15.432 ;
     RECT  41.356 26.256 41.537 26.76 ;
     RECT  41.468 32.976 41.555 33 ;
     RECT  40.589 51.696 41.572 51.72 ;
     RECT  41.537 26.256 41.573 26.664 ;
     RECT  41.141 22.752 41.605 23.592 ;
     RECT  41.605 22.752 41.612 23.736 ;
     RECT  41.141 29.088 41.645 29.112 ;
     RECT  41.572 51.648 41.681 51.72 ;
     RECT  41.681 51.696 41.861 51.72 ;
     RECT  41.612 22.752 41.929 23.928 ;
     RECT  40.961 48.192 42.001 48.216 ;
     RECT  41.929 22.752 42.083 23.976 ;
     RECT  41.356 25.056 42.113 25.08 ;
     RECT  42.001 48.192 42.149 49.08 ;
     RECT  41.989 33.072 42.257 33.096 ;
     RECT  42.181 3.408 42.275 3.432 ;
     RECT  42.289 18.816 42.361 18.84 ;
     RECT  42.361 45.024 42.373 45.048 ;
     RECT  42.181 41.568 42.437 41.592 ;
     RECT  42.361 18.816 42.467 18.888 ;
     RECT  42.373 45.024 42.611 45.576 ;
     RECT  42.611 45.552 42.617 45.576 ;
     RECT  42.467 18.864 42.659 18.888 ;
     RECT  42.649 21.072 42.685 21.096 ;
     RECT  41.219 30.864 42.721 30.888 ;
     RECT  42.083 22.752 42.833 23.832 ;
     RECT  42.685 20.592 42.851 21.096 ;
     RECT  42.851 20.592 42.937 20.616 ;
     RECT  42.86 31.872 42.947 31.896 ;
     RECT  42.721 30.768 42.949 30.888 ;
     RECT  42.949 30.768 42.995 31.32 ;
     RECT  42.757 42.72 43.085 42.744 ;
     RECT  42.572 25.632 43.117 25.656 ;
     RECT  42.613 28.656 43.117 28.68 ;
     RECT  43.117 28.656 43.235 29.112 ;
     RECT  41.573 26.64 43.297 26.664 ;
     RECT  42.149 48.192 43.297 48.216 ;
     RECT  43.297 47.952 43.333 48.216 ;
     RECT  42.833 23.568 43.373 23.832 ;
     RECT  43.297 26.64 43.409 27.336 ;
     RECT  43.333 47.328 43.427 48.216 ;
     RECT  43.117 25.296 43.549 25.656 ;
     RECT  43.141 51.696 43.553 51.72 ;
     RECT  43.549 25.296 43.633 26.232 ;
     RECT  43.427 47.856 43.765 48.216 ;
     RECT  43.757 16.56 43.841 16.584 ;
     RECT  42.937 19.968 43.873 20.616 ;
     RECT  43.873 19.824 43.916 20.616 ;
     RECT  43.633 25.296 43.985 25.752 ;
     RECT  43.916 19.824 44.003 21.384 ;
     RECT  43.937 49.536 44.021 49.56 ;
     RECT  43.235 28.656 44.053 29.064 ;
     RECT  44.053 28.512 44.093 29.064 ;
     RECT  43.409 27.312 44.129 27.336 ;
     RECT  44.093 28.512 44.129 28.68 ;
     RECT  43.573 50.688 44.149 50.712 ;
     RECT  44.017 18.816 44.195 18.84 ;
     RECT  42.995 31.296 44.197 31.32 ;
     RECT  43.765 47.856 44.273 48.456 ;
     RECT  44.149 50.112 44.309 50.712 ;
     RECT  44.197 30.768 44.381 31.32 ;
     RECT  44.003 19.92 44.389 21.384 ;
     RECT  44.273 47.856 44.417 47.976 ;
     RECT  44.389 19.92 44.453 20.52 ;
     RECT  44.381 30.864 44.489 31.32 ;
     RECT  44.449 21.6 44.579 22.2 ;
     RECT  44.533 51.696 44.593 51.72 ;
     RECT  44.129 28.512 44.633 28.536 ;
     RECT  41.075 0.144 45.068 0.168 ;
     RECT  45.068 0.144 45.155 0.552 ;
     RECT  44.593 50.736 45.155 51.72 ;
     RECT  43.985 25.632 45.26 25.752 ;
     RECT  44.453 20.496 45.385 20.52 ;
     RECT  44.579 21.6 45.385 22.056 ;
     RECT  43.373 23.568 45.457 23.592 ;
     RECT  44.953 27.6 45.493 27.624 ;
     RECT  45.493 27.36 45.601 27.624 ;
     RECT  44.773 15.408 45.608 15.432 ;
     RECT  45.397 18.816 45.608 18.84 ;
     RECT  45.385 20.496 45.608 22.056 ;
     RECT  45.457 23.28 45.608 23.592 ;
     RECT  45.26 24.768 45.608 25.752 ;
     RECT  45.601 27.072 45.608 27.624 ;
     RECT  45.205 29.664 45.608 29.688 ;
     RECT  44.489 30.864 45.608 30.888 ;
     RECT  42.901 46.224 45.608 46.248 ;
     RECT  44.417 47.952 45.608 47.976 ;
     RECT  45.457 50.16 45.608 50.184 ;
     RECT  45.608 2.148 45.712 50.184 ;
     RECT  45.712 2.418 45.904 50.184 ;
     RECT  45.904 50.16 45.971 50.184 ;
     RECT  45.904 20.592 46.067 20.664 ;
     RECT  46.067 20.592 46.109 20.616 ;
     RECT  45.904 31.296 46.189 31.32 ;
     RECT  45.904 25.728 46.211 27.384 ;
     RECT  45.155 0.144 46.213 0.36 ;
     RECT  45.904 29.088 46.217 30.168 ;
     RECT  46.213 0.144 46.307 1.128 ;
     RECT  45.904 49.008 46.547 49.08 ;
     RECT  45.155 51.696 46.645 51.72 ;
     RECT  45.904 18.816 46.693 19.416 ;
     RECT  45.904 22.176 46.721 23.592 ;
     RECT  46.211 25.728 46.721 26.232 ;
     RECT  46.645 50.736 46.739 51.72 ;
     RECT  46.721 22.176 46.883 22.824 ;
     RECT  46.547 49.008 46.931 49.032 ;
     RECT  46.211 27.36 46.933 27.384 ;
     RECT  46.933 27.36 47.075 27.96 ;
     RECT  46.883 22.176 47.113 22.2 ;
     RECT  47.113 21.648 47.153 22.2 ;
     RECT  47.149 18.192 47.267 18.216 ;
     RECT  45.904 47.952 47.285 47.976 ;
     RECT  46.217 29.088 47.297 29.544 ;
     RECT  47.285 47.28 47.369 47.976 ;
     RECT  47.297 29.088 47.459 29.112 ;
     RECT  47.153 21.648 47.545 21.672 ;
     RECT  46.739 50.784 47.621 51.72 ;
     RECT  46.721 26.208 47.653 26.232 ;
     RECT  47.075 27.36 47.653 27.384 ;
     RECT  47.545 21.6 47.689 21.672 ;
     RECT  47.653 26.208 47.693 27.384 ;
     RECT  47.369 47.856 47.801 47.976 ;
     RECT  47.801 47.856 47.837 47.88 ;
     RECT  47.689 21.12 47.893 21.672 ;
     RECT  47.893 21.072 47.939 21.672 ;
     RECT  47.852 23.856 47.939 23.88 ;
     RECT  47.852 45.024 47.939 45.048 ;
     RECT  45.904 46.224 48.017 46.248 ;
     RECT  47.905 22.8 48.035 22.824 ;
     RECT  46.693 19.392 48.053 19.416 ;
     RECT  47.939 21.072 48.053 21.096 ;
     RECT  48.044 50.736 48.131 50.76 ;
     RECT  47.977 28.992 48.197 29.016 ;
     RECT  48.121 19.968 48.227 19.992 ;
     RECT  47.693 26.208 48.233 26.76 ;
     RECT  47.113 24.912 48.301 24.936 ;
     RECT  48.301 24.912 48.305 25.848 ;
     RECT  48.337 23.376 48.421 23.448 ;
     RECT  48.421 23.424 48.659 23.448 ;
     RECT  46.307 0.144 48.769 0.168 ;
     RECT  48.661 46.704 48.805 46.728 ;
     RECT  48.805 46.704 48.809 47.352 ;
     RECT  48.589 42.768 48.845 42.792 ;
     RECT  48.445 1.68 48.851 1.704 ;
     RECT  48.809 47.328 48.899 47.352 ;
     RECT  48.236 49.584 48.913 49.608 ;
     RECT  48.305 25.824 49.043 25.848 ;
     RECT  48.913 49.44 49.165 49.608 ;
     RECT  49.148 51.648 49.201 51.672 ;
     RECT  49.021 2.256 49.235 2.28 ;
     RECT  49.201 50.736 49.235 51.672 ;
     RECT  49.157 46.128 49.241 46.152 ;
     RECT  49.309 17.088 49.427 17.112 ;
     RECT  49.165 49.44 49.489 49.656 ;
     RECT  49.235 50.736 49.489 50.856 ;
     RECT  49.093 47.808 49.493 47.832 ;
     RECT  48.769 0.144 49.597 0.552 ;
     RECT  48.877 14.832 49.619 14.856 ;
     RECT  49.489 49.44 49.715 50.856 ;
     RECT  49.597 0.144 49.811 1.128 ;
     RECT  49.811 0.144 50.003 0.552 ;
     RECT  49.129 3.408 50.195 3.432 ;
     RECT  50.003 0.144 50.393 0.264 ;
     RECT  49.715 50.16 50.675 50.856 ;
     RECT  50.675 50.16 50.78 50.232 ;
     RECT  50.78 49.584 50.867 50.232 ;
     RECT  50.867 50.16 51.059 50.232 ;
     RECT  50.393 0.144 51.113 0.168 ;
     RECT  51.059 50.208 51.251 50.232 ;
    LAYER M5 ;
     RECT  0.696 0.016 0.864 0.084 ;
     RECT  0.888 0.016 1.056 0.084 ;
     RECT  1.08 0.016 1.248 0.084 ;
     RECT  1.272 0.016 1.44 0.084 ;
     RECT  1.464 0.016 1.632 0.084 ;
     RECT  1.656 0.016 1.824 0.084 ;
     RECT  1.848 0.016 2.016 0.084 ;
     RECT  2.04 0.016 2.208 0.084 ;
     RECT  2.232 0.016 2.4 0.084 ;
     RECT  2.424 0.016 2.592 0.084 ;
     RECT  2.616 0.016 2.784 0.084 ;
     RECT  2.808 0.016 2.976 0.084 ;
     RECT  3 0.016 3.168 0.084 ;
     RECT  3.192 0.016 3.36 0.084 ;
     RECT  3.384 0.016 3.552 0.084 ;
     RECT  3.576 0.016 3.744 0.084 ;
     RECT  3.768 0.016 3.936 0.084 ;
     RECT  3.96 0.016 4.176 0.084 ;
     RECT  4.2 0.016 4.368 0.084 ;
     RECT  4.392 0.016 4.56 0.084 ;
     RECT  4.584 0.016 4.752 0.084 ;
     RECT  4.776 0.016 4.944 0.084 ;
     RECT  4.968 0.016 5.136 0.084 ;
     RECT  5.16 0.016 5.328 0.084 ;
     RECT  5.352 0.016 5.52 0.084 ;
     RECT  5.544 0.016 5.712 0.084 ;
     RECT  5.736 0.016 5.904 0.084 ;
     RECT  5.928 0.016 6.096 0.084 ;
     RECT  6.12 0.016 6.288 0.084 ;
     RECT  6.312 0.016 6.48 0.084 ;
     RECT  6.504 0.016 6.672 0.084 ;
     RECT  6.696 0.016 6.864 0.084 ;
     RECT  6.888 0.016 7.056 0.084 ;
     RECT  7.08 0.016 7.248 0.084 ;
     RECT  7.272 0.016 7.44 0.084 ;
     RECT  7.464 0.016 7.632 0.084 ;
     RECT  7.656 0.016 7.824 0.084 ;
     RECT  7.848 0.016 8.016 0.084 ;
     RECT  8.04 0.016 8.208 0.084 ;
     RECT  8.232 0.016 8.4 0.084 ;
     RECT  8.424 0.016 8.592 0.084 ;
     RECT  8.616 0.016 8.784 0.084 ;
     RECT  8.808 0.016 8.976 0.084 ;
     RECT  9 0.016 9.168 0.084 ;
     RECT  9.192 0.016 9.36 0.084 ;
     RECT  9.384 0.016 9.552 0.084 ;
     RECT  9.576 0.016 9.744 0.084 ;
     RECT  9.768 0.016 9.936 0.084 ;
     RECT  9.96 0.016 10.128 0.084 ;
     RECT  10.152 0.016 10.32 0.084 ;
     RECT  10.344 0.016 10.512 0.084 ;
     RECT  10.536 0.016 10.704 0.084 ;
     RECT  10.728 0.016 10.896 0.084 ;
     RECT  10.92 0.016 11.088 0.084 ;
     RECT  11.112 0.016 11.28 0.084 ;
     RECT  11.304 0.016 11.472 0.084 ;
     RECT  11.496 0.016 11.712 0.084 ;
     RECT  11.736 0.016 11.904 0.084 ;
     RECT  11.928 0.016 12.096 0.084 ;
     RECT  12.12 0.016 12.288 0.084 ;
     RECT  12.312 0.016 12.48 0.084 ;
     RECT  12.504 0.016 12.672 0.084 ;
     RECT  12.696 0.016 12.864 0.084 ;
     RECT  12.888 0.016 13.056 0.084 ;
     RECT  13.08 0.016 13.248 0.084 ;
     RECT  13.272 0.016 13.44 0.084 ;
     RECT  13.464 0.016 13.632 0.084 ;
     RECT  13.656 0.016 13.824 0.084 ;
     RECT  13.848 0.016 14.016 0.084 ;
     RECT  14.04 0.016 14.208 0.084 ;
     RECT  14.232 0.016 14.4 0.084 ;
     RECT  14.424 0.016 14.592 0.084 ;
     RECT  14.616 0.016 14.784 0.084 ;
     RECT  14.808 0.016 14.976 0.084 ;
     RECT  15 0.016 15.168 0.084 ;
     RECT  15.192 0.016 15.36 0.084 ;
     RECT  15.384 0.016 15.552 0.084 ;
     RECT  15.576 0.016 15.744 0.084 ;
     RECT  15.768 0.016 15.936 0.084 ;
     RECT  15.96 0.016 16.128 0.084 ;
     RECT  16.152 0.016 16.32 0.084 ;
     RECT  16.344 0.016 16.512 0.084 ;
     RECT  16.536 0.016 16.704 0.084 ;
     RECT  16.728 0.016 16.896 0.084 ;
     RECT  16.92 0.016 17.088 0.084 ;
     RECT  17.112 0.016 17.28 0.084 ;
     RECT  17.304 0.016 17.472 0.084 ;
     RECT  17.496 0.016 17.664 0.084 ;
     RECT  17.688 0.016 17.856 0.084 ;
     RECT  17.88 0.016 18.048 0.084 ;
     RECT  18.072 0.016 18.24 0.084 ;
     RECT  18.264 0.016 18.432 0.084 ;
     RECT  18.456 0.016 18.624 0.084 ;
     RECT  18.648 0.016 18.816 0.084 ;
     RECT  18.84 0.016 19.056 0.084 ;
     RECT  19.08 0.016 19.248 0.084 ;
     RECT  19.272 0.016 19.44 0.084 ;
     RECT  19.464 0.016 19.632 0.084 ;
     RECT  19.656 0.016 19.824 0.084 ;
     RECT  19.848 0.016 20.016 0.084 ;
     RECT  20.04 0.016 20.208 0.084 ;
     RECT  20.232 0.016 20.4 0.084 ;
     RECT  20.424 0.016 20.592 0.084 ;
     RECT  20.616 0.016 20.784 0.084 ;
     RECT  20.808 0.016 20.976 0.084 ;
     RECT  21 0.016 21.168 0.084 ;
     RECT  21.192 0.016 21.36 0.084 ;
     RECT  21.384 0.016 21.552 0.084 ;
     RECT  21.576 0.016 21.744 0.084 ;
     RECT  21.768 0.016 21.936 0.084 ;
     RECT  21.96 0.016 22.128 0.084 ;
     RECT  22.152 0.016 22.32 0.084 ;
     RECT  22.344 0.016 22.512 0.084 ;
     RECT  22.536 0.016 22.704 0.084 ;
     RECT  22.728 0.016 22.896 0.084 ;
     RECT  22.92 0.016 23.088 0.084 ;
     RECT  23.112 0.016 23.28 0.084 ;
     RECT  23.304 0.016 23.472 0.084 ;
     RECT  23.496 0.016 23.664 0.084 ;
     RECT  23.688 0.016 23.856 0.084 ;
     RECT  23.88 0.016 24.048 0.084 ;
     RECT  24.072 0.016 24.24 0.084 ;
     RECT  24.264 0.016 24.432 0.084 ;
     RECT  24.456 0.016 24.624 0.084 ;
     RECT  24.648 0.016 24.816 0.084 ;
     RECT  24.84 0.016 25.008 0.084 ;
     RECT  25.032 0.016 25.2 0.084 ;
     RECT  25.224 0.016 25.392 0.084 ;
     RECT  25.416 0.016 25.584 0.084 ;
     RECT  25.608 0.016 25.776 0.084 ;
     RECT  25.8 0.016 25.968 0.084 ;
     RECT  25.992 0.016 26.16 0.084 ;
     RECT  26.184 0.016 26.4 0.084 ;
     RECT  26.424 0.016 26.592 0.084 ;
     RECT  26.616 0.016 26.784 0.084 ;
     RECT  26.808 0.016 26.976 0.084 ;
     RECT  27 0.016 27.168 0.084 ;
     RECT  27.192 0.016 27.36 0.084 ;
     RECT  27.384 0.016 27.552 0.084 ;
     RECT  27.576 0.016 27.744 0.084 ;
     RECT  27.768 0.016 27.936 0.084 ;
     RECT  27.96 0.016 28.128 0.084 ;
     RECT  28.152 0.016 28.32 0.084 ;
     RECT  28.344 0.016 28.512 0.084 ;
     RECT  28.536 0.016 28.704 0.084 ;
     RECT  28.728 0.016 28.896 0.084 ;
     RECT  28.92 0.016 29.088 0.084 ;
     RECT  29.112 0.016 29.28 0.084 ;
     RECT  29.304 0.016 29.472 0.084 ;
     RECT  29.496 0.016 29.664 0.084 ;
     RECT  29.688 0.016 29.856 0.084 ;
     RECT  29.88 0.016 30.048 0.084 ;
     RECT  30.072 0.016 30.24 0.084 ;
     RECT  30.264 0.016 30.432 0.084 ;
     RECT  30.456 0.016 30.624 0.084 ;
     RECT  30.648 0.016 30.816 0.084 ;
     RECT  30.84 0.016 31.008 0.084 ;
     RECT  31.032 0.016 31.2 0.084 ;
     RECT  31.224 0.016 31.392 0.084 ;
     RECT  31.416 0.016 31.584 0.084 ;
     RECT  31.608 0.016 31.776 0.084 ;
     RECT  31.8 0.016 31.968 0.084 ;
     RECT  31.992 0.016 32.16 0.084 ;
     RECT  32.184 0.016 32.352 0.084 ;
     RECT  32.376 0.016 32.544 0.084 ;
     RECT  32.568 0.016 32.736 0.084 ;
     RECT  32.76 0.016 32.928 0.084 ;
     RECT  32.952 0.016 33.12 0.084 ;
     RECT  33.144 0.016 33.312 0.084 ;
     RECT  33.336 0.016 33.504 0.084 ;
     RECT  33.528 0.016 33.744 0.084 ;
     RECT  33.768 0.016 33.936 0.084 ;
     RECT  33.96 0.016 34.128 0.084 ;
     RECT  34.152 0.016 34.32 0.084 ;
     RECT  34.344 0.016 34.512 0.084 ;
     RECT  34.536 0.016 34.704 0.084 ;
     RECT  34.728 0.016 34.896 0.084 ;
     RECT  34.92 0.016 35.088 0.084 ;
     RECT  35.112 0.016 35.28 0.084 ;
     RECT  35.304 0.016 35.472 0.084 ;
     RECT  35.496 0.016 35.664 0.084 ;
     RECT  35.688 0.016 35.856 0.084 ;
     RECT  35.88 0.016 36.048 0.084 ;
     RECT  36.072 0.016 36.24 0.084 ;
     RECT  36.264 0.016 36.432 0.084 ;
     RECT  36.456 0.016 36.624 0.084 ;
     RECT  36.648 0.016 36.816 0.084 ;
     RECT  36.84 0.016 37.008 0.084 ;
     RECT  37.032 0.016 37.2 0.084 ;
     RECT  37.224 0.016 37.392 0.084 ;
     RECT  37.416 0.016 37.584 0.084 ;
     RECT  37.608 0.016 37.776 0.084 ;
     RECT  37.8 0.016 37.968 0.084 ;
     RECT  37.992 0.016 38.16 0.084 ;
     RECT  38.184 0.016 38.352 0.084 ;
     RECT  38.376 0.016 38.544 0.084 ;
     RECT  38.568 0.016 38.736 0.084 ;
     RECT  38.76 0.016 38.928 0.084 ;
     RECT  38.952 0.016 39.12 0.084 ;
     RECT  39.144 0.016 39.312 0.084 ;
     RECT  39.336 0.016 39.504 0.084 ;
     RECT  39.528 0.016 39.696 0.084 ;
     RECT  39.72 0.016 39.888 0.084 ;
     RECT  39.912 0.016 40.08 0.084 ;
     RECT  40.104 0.016 40.272 0.084 ;
     RECT  40.296 0.016 40.464 0.084 ;
     RECT  40.488 0.016 40.656 0.084 ;
     RECT  40.68 0.016 40.848 0.084 ;
     RECT  40.872 0.016 41.04 0.084 ;
     RECT  41.064 0.016 41.28 0.084 ;
     RECT  41.304 0.016 41.472 0.084 ;
     RECT  41.496 0.016 41.664 0.084 ;
     RECT  41.688 0.016 41.856 0.084 ;
     RECT  41.88 0.016 42.048 0.084 ;
     RECT  42.072 0.016 42.24 0.084 ;
     RECT  42.264 0.016 42.432 0.084 ;
     RECT  42.456 0.016 42.624 0.084 ;
     RECT  42.648 0.016 42.816 0.084 ;
     RECT  42.84 0.016 43.008 0.084 ;
     RECT  43.032 0.016 43.2 0.084 ;
     RECT  43.224 0.016 43.392 0.084 ;
     RECT  43.416 0.016 43.584 0.084 ;
     RECT  43.608 0.016 43.776 0.084 ;
     RECT  43.8 0.016 43.968 0.084 ;
     RECT  43.992 0.016 44.16 0.084 ;
     RECT  44.184 0.016 44.352 0.084 ;
     RECT  44.376 0.016 44.544 0.084 ;
     RECT  44.568 0.016 44.736 0.084 ;
     RECT  44.76 0.016 44.928 0.084 ;
     RECT  44.952 0.016 45.12 0.084 ;
     RECT  45.144 0.016 45.312 0.084 ;
     RECT  45.336 0.016 45.504 0.084 ;
     RECT  45.528 0.016 45.696 0.084 ;
     RECT  45.72 0.016 45.888 0.084 ;
     RECT  45.912 0.016 46.08 0.084 ;
     RECT  46.104 0.016 46.272 0.084 ;
     RECT  46.296 0.016 46.464 0.084 ;
     RECT  46.488 0.016 46.656 0.084 ;
     RECT  46.68 0.016 46.848 0.084 ;
     RECT  46.872 0.016 47.04 0.084 ;
     RECT  47.064 0.016 47.232 0.084 ;
     RECT  47.256 0.016 47.424 0.084 ;
     RECT  47.448 0.016 47.616 0.084 ;
     RECT  47.64 0.016 47.808 0.084 ;
     RECT  47.832 0.016 48 0.084 ;
     RECT  48.024 0.016 48.192 0.084 ;
     RECT  48.216 0.016 48.384 0.084 ;
     RECT  48.408 0.016 48.624 0.084 ;
     RECT  48.648 0.016 48.816 0.084 ;
     RECT  48.84 0.016 49.008 0.084 ;
     RECT  49.032 0.016 49.2 0.084 ;
     RECT  49.224 0.016 49.392 0.084 ;
     RECT  49.416 0.016 49.584 0.084 ;
     RECT  49.608 0.016 49.776 0.084 ;
     RECT  49.8 0.016 49.968 0.084 ;
     RECT  49.992 0.016 50.16 0.084 ;
     RECT  50.184 0.016 50.352 0.084 ;
     RECT  0.672 0.084 50.376 0.275 ;
     RECT  0.672 0.275 50.184 3.443 ;
     RECT  0.672 3.443 49.608 14.867 ;
     RECT  0.672 14.867 49.416 17.123 ;
     RECT  0.672 17.123 49.032 17.699 ;
     RECT  0.864 17.699 49.032 17.747 ;
     RECT  1.056 17.747 49.032 17.795 ;
     RECT  1.248 17.795 49.032 18.851 ;
     RECT  32.352 18.851 49.032 18.899 ;
     RECT  1.44 18.851 13.608 18.947 ;
     RECT  1.44 18.947 11.304 19.475 ;
     RECT  14.592 18.851 26.424 21.061 ;
     RECT  27.552 18.851 31.032 21.061 ;
     RECT  40.032 18.899 49.032 21.107 ;
     RECT  2.016 19.475 11.304 21.683 ;
     RECT  2.016 21.683 6.12 21.731 ;
     RECT  14.592 21.061 31.032 22.117 ;
     RECT  32.352 18.899 38.76 22.117 ;
     RECT  43.2 21.107 49.032 22.211 ;
     RECT  14.592 22.117 38.76 22.259 ;
     RECT  14.64 22.259 38.76 22.499 ;
     RECT  7.632 21.683 11.304 22.741 ;
     RECT  12.288 18.947 13.608 22.741 ;
     RECT  4.752 21.731 6.12 22.787 ;
     RECT  40.032 21.107 42.072 23.317 ;
     RECT  7.632 22.741 13.608 23.363 ;
     RECT  7.632 23.363 13.512 23.411 ;
     RECT  44.736 22.211 49.032 23.459 ;
     RECT  39.84 23.317 42.072 23.557 ;
     RECT  43.2 22.211 43.608 23.557 ;
     RECT  5.232 22.787 6.12 23.941 ;
     RECT  7.632 23.411 11.304 23.987 ;
     RECT  14.64 22.499 26.424 23.987 ;
     RECT  27.552 22.499 38.76 23.987 ;
     RECT  5.136 23.941 6.12 24.275 ;
     RECT  2.016 21.731 3.576 24.277 ;
     RECT  5.328 24.275 6.12 24.469 ;
     RECT  12.288 23.411 13.512 24.469 ;
     RECT  18.6 23.987 26.424 24.515 ;
     RECT  27.744 23.987 38.76 24.515 ;
     RECT  27.744 24.515 35.112 24.659 ;
     RECT  36.24 24.515 38.76 24.805 ;
     RECT  39.84 23.557 43.608 24.805 ;
     RECT  44.736 23.459 47.928 24.947 ;
     RECT  5.328 24.469 6.504 25.091 ;
     RECT  36.24 24.805 43.608 25.091 ;
     RECT  7.632 23.987 9.768 25.333 ;
     RECT  44.736 24.947 47.448 25.667 ;
     RECT  2.016 24.277 3.864 25.715 ;
     RECT  49.008 23.459 49.032 25.859 ;
     RECT  12.288 24.469 13.656 25.955 ;
     RECT  7.632 25.333 9.864 26.243 ;
     RECT  42.624 25.091 43.608 26.243 ;
     RECT  36.24 25.091 41.4 26.387 ;
     RECT  27.744 24.659 29.712 26.533 ;
     RECT  30.816 24.659 35.112 26.533 ;
     RECT  5.328 25.091 6.12 26.725 ;
     RECT  27.744 26.533 35.112 27.107 ;
     RECT  18.6 24.515 25.992 27.301 ;
     RECT  7.632 26.243 9.768 27.349 ;
     RECT  30.816 27.107 35.112 27.395 ;
     RECT  36.24 26.387 41.304 27.395 ;
     RECT  7.632 27.349 10.728 27.877 ;
     RECT  12.288 25.955 13.512 27.877 ;
     RECT  31.008 27.395 35.112 27.877 ;
     RECT  36.24 27.395 37.416 27.877 ;
     RECT  18.6 27.301 26.328 27.971 ;
     RECT  31.008 27.877 37.416 28.211 ;
     RECT  26.304 27.971 26.328 28.355 ;
     RECT  38.496 27.395 41.304 28.451 ;
     RECT  5.328 26.725 6.648 28.453 ;
     RECT  7.632 27.877 13.512 28.453 ;
     RECT  14.64 23.987 17.304 28.453 ;
     RECT  18.6 27.971 25.032 28.453 ;
     RECT  27.744 27.107 29.712 28.453 ;
     RECT  5.328 28.453 13.512 28.547 ;
     RECT  42.624 26.243 43.416 28.691 ;
     RECT  5.328 28.547 10.728 29.029 ;
     RECT  12.288 28.547 13.512 29.123 ;
     RECT  38.736 28.451 41.304 29.123 ;
     RECT  45.216 25.667 47.448 29.123 ;
     RECT  14.64 28.453 25.032 29.651 ;
     RECT  27.744 28.453 29.832 29.699 ;
     RECT  36.432 28.211 37.416 29.699 ;
     RECT  45.216 29.123 45.912 29.699 ;
     RECT  14.64 29.651 20.808 30.131 ;
     RECT  38.736 29.123 41.016 30.181 ;
     RECT  14.64 30.131 20.376 30.275 ;
     RECT  21.936 29.651 23.016 30.275 ;
     RECT  37.392 29.699 37.416 30.275 ;
     RECT  28.992 29.699 29.832 30.757 ;
     RECT  31.008 28.211 35.304 30.757 ;
     RECT  38.736 30.181 41.208 30.805 ;
     RECT  26.448 30.181 26.472 30.853 ;
     RECT  38.64 30.805 41.208 30.853 ;
     RECT  28.992 30.757 35.304 30.995 ;
     RECT  21.936 30.275 22.152 31.285 ;
     RECT  24 29.651 25.032 31.285 ;
     RECT  45.6 29.699 45.912 31.285 ;
     RECT  38.64 30.853 41.544 31.379 ;
     RECT  14.64 30.275 17.016 31.573 ;
     RECT  26.112 30.853 26.472 31.861 ;
     RECT  27.744 29.699 27.864 31.861 ;
     RECT  38.736 31.379 41.544 31.907 ;
     RECT  11.712 30.997 11.736 32.437 ;
     RECT  13.056 29.123 13.512 32.437 ;
     RECT  21.936 31.285 25.032 32.483 ;
     RECT  39.216 31.907 41.544 33.011 ;
     RECT  42.912 28.691 43.416 33.061 ;
     RECT  28.992 30.995 29.832 33.637 ;
     RECT  31.008 30.995 31.8 33.637 ;
     RECT  23.28 32.483 25.032 34.259 ;
     RECT  26.112 31.861 27.864 34.259 ;
     RECT  18.192 30.275 20.376 34.835 ;
     RECT  2.4 25.715 3.864 37.093 ;
     RECT  2.304 37.093 3.864 37.235 ;
     RECT  2.4 37.235 3.864 42.709 ;
     RECT  4.992 29.029 10.728 42.709 ;
     RECT  11.712 32.437 13.512 45.541 ;
     RECT  14.496 31.573 17.016 45.541 ;
     RECT  38.064 33.637 38.088 45.541 ;
     RECT  2.4 42.709 10.728 45.589 ;
     RECT  11.712 45.541 17.016 45.589 ;
     RECT  26.448 34.259 27.864 45.589 ;
     RECT  28.992 33.637 31.8 45.589 ;
     RECT  2.4 45.589 17.016 46.069 ;
     RECT  2.304 46.069 17.016 46.117 ;
     RECT  18.192 34.835 19.176 46.117 ;
     RECT  21.936 32.483 22.152 46.117 ;
     RECT  23.28 34.259 24.936 46.117 ;
     RECT  26.448 45.589 31.8 46.117 ;
     RECT  32.928 30.995 35.304 46.117 ;
     RECT  2.304 46.117 19.176 46.211 ;
     RECT  37.68 45.541 38.088 46.693 ;
     RECT  39.216 33.011 41.016 46.693 ;
     RECT  47.904 45.013 47.928 46.693 ;
     RECT  49.2 46.117 49.224 46.693 ;
     RECT  6.576 46.211 19.176 47.269 ;
     RECT  20.352 34.835 20.376 47.269 ;
     RECT  47.904 46.693 49.224 47.269 ;
     RECT  2.304 46.211 5.544 47.363 ;
     RECT  21.936 46.117 24.936 47.363 ;
     RECT  26.448 46.117 35.304 47.363 ;
     RECT  42 33.061 43.416 47.363 ;
     RECT  0.864 48.085 0.888 48.133 ;
     RECT  2.304 47.363 5.208 48.133 ;
     RECT  42 47.363 42.984 48.421 ;
     RECT  44.352 47.845 44.376 48.421 ;
     RECT  36.48 48.421 36.504 48.469 ;
     RECT  37.68 46.693 41.016 48.469 ;
     RECT  6.576 47.269 20.376 48.949 ;
     RECT  6.576 48.949 20.952 48.997 ;
     RECT  23.088 47.363 24.936 48.997 ;
     RECT  26.448 47.363 30.6 48.997 ;
     RECT  45.6 31.285 46.152 48.997 ;
     RECT  47.328 47.269 49.224 48.997 ;
     RECT  23.088 48.997 30.6 49.381 ;
     RECT  45.6 48.997 49.224 49.429 ;
     RECT  0.864 48.133 5.208 49.477 ;
     RECT  6.192 48.997 20.952 49.477 ;
     RECT  0.864 49.477 20.952 49.525 ;
     RECT  22.128 49.381 30.6 49.525 ;
     RECT  31.776 47.363 35.304 49.525 ;
     RECT  22.128 49.525 35.304 49.573 ;
     RECT  45.6 49.429 49.704 49.703 ;
     RECT  0.672 49.525 20.952 50.101 ;
     RECT  21.936 49.573 35.304 50.101 ;
     RECT  45.744 49.703 49.704 50.149 ;
     RECT  50.832 49.573 50.856 50.149 ;
     RECT  45.744 50.149 51.048 50.197 ;
     RECT  0.672 50.101 35.304 50.677 ;
     RECT  36.48 48.469 41.016 50.677 ;
     RECT  42 48.421 44.376 50.725 ;
     RECT  45.744 50.197 51.24 50.725 ;
     RECT  0.672 50.677 41.016 51.637 ;
     RECT  42 50.725 51.24 51.637 ;
     RECT  0.672 51.637 51.24 51.756 ;
     RECT  0.696 51.756 0.864 51.792 ;
     RECT  0.888 51.756 1.056 51.792 ;
     RECT  1.08 51.756 1.248 51.792 ;
     RECT  1.272 51.756 1.44 51.792 ;
     RECT  1.464 51.756 1.68 51.792 ;
     RECT  1.704 51.756 1.872 51.792 ;
     RECT  1.896 51.756 2.064 51.792 ;
     RECT  2.088 51.756 2.256 51.792 ;
     RECT  2.28 51.756 2.448 51.792 ;
     RECT  2.472 51.756 2.64 51.792 ;
     RECT  2.664 51.756 2.832 51.792 ;
     RECT  2.856 51.756 3.024 51.792 ;
     RECT  3.048 51.756 3.216 51.792 ;
     RECT  3.24 51.756 3.408 51.792 ;
     RECT  3.432 51.756 3.648 51.792 ;
     RECT  3.672 51.756 3.84 51.792 ;
     RECT  3.864 51.756 4.032 51.792 ;
     RECT  4.056 51.756 4.224 51.792 ;
     RECT  4.248 51.756 4.416 51.792 ;
     RECT  4.44 51.756 4.608 51.792 ;
     RECT  4.632 51.756 4.8 51.792 ;
     RECT  4.824 51.756 4.992 51.792 ;
     RECT  5.016 51.756 5.184 51.792 ;
     RECT  5.208 51.756 5.376 51.792 ;
     RECT  5.4 51.756 5.616 51.792 ;
     RECT  5.64 51.756 5.808 51.792 ;
     RECT  5.832 51.756 6 51.792 ;
     RECT  6.024 51.756 6.192 51.792 ;
     RECT  6.216 51.756 6.384 51.792 ;
     RECT  6.408 51.756 6.576 51.792 ;
     RECT  6.6 51.756 6.768 51.792 ;
     RECT  6.792 51.756 6.96 51.792 ;
     RECT  6.984 51.756 7.152 51.792 ;
     RECT  7.176 51.756 7.344 51.792 ;
     RECT  7.368 51.756 7.584 51.792 ;
     RECT  7.608 51.756 7.776 51.792 ;
     RECT  7.8 51.756 7.968 51.792 ;
     RECT  7.992 51.756 8.16 51.792 ;
     RECT  8.184 51.756 8.352 51.792 ;
     RECT  8.376 51.756 8.544 51.792 ;
     RECT  8.568 51.756 8.736 51.792 ;
     RECT  8.76 51.756 8.928 51.792 ;
     RECT  8.952 51.756 9.12 51.792 ;
     RECT  9.144 51.756 9.312 51.792 ;
     RECT  9.336 51.756 9.552 51.792 ;
     RECT  9.576 51.756 9.744 51.792 ;
     RECT  9.768 51.756 9.936 51.792 ;
     RECT  9.96 51.756 10.128 51.792 ;
     RECT  10.152 51.756 10.32 51.792 ;
     RECT  10.344 51.756 10.512 51.792 ;
     RECT  10.536 51.756 10.704 51.792 ;
     RECT  10.728 51.756 10.896 51.792 ;
     RECT  10.92 51.756 11.088 51.792 ;
     RECT  11.112 51.756 11.28 51.792 ;
     RECT  11.304 51.756 11.52 51.792 ;
     RECT  11.544 51.756 11.712 51.792 ;
     RECT  11.736 51.756 11.904 51.792 ;
     RECT  11.928 51.756 12.096 51.792 ;
     RECT  12.12 51.756 12.288 51.792 ;
     RECT  12.312 51.756 12.48 51.792 ;
     RECT  12.504 51.756 12.672 51.792 ;
     RECT  12.696 51.756 12.864 51.792 ;
     RECT  12.888 51.756 13.056 51.792 ;
     RECT  13.08 51.756 13.248 51.792 ;
     RECT  13.272 51.756 13.488 51.792 ;
     RECT  13.512 51.756 13.68 51.792 ;
     RECT  13.704 51.756 13.872 51.792 ;
     RECT  13.896 51.756 14.064 51.792 ;
     RECT  14.088 51.756 14.256 51.792 ;
     RECT  14.28 51.756 14.448 51.792 ;
     RECT  14.472 51.756 14.64 51.792 ;
     RECT  14.664 51.756 14.832 51.792 ;
     RECT  14.856 51.756 15.024 51.792 ;
     RECT  15.048 51.756 15.216 51.792 ;
     RECT  15.24 51.756 15.408 51.792 ;
     RECT  15.432 51.756 15.648 51.792 ;
     RECT  15.672 51.756 15.84 51.792 ;
     RECT  15.864 51.756 16.032 51.792 ;
     RECT  16.056 51.756 16.224 51.792 ;
     RECT  16.248 51.756 16.416 51.792 ;
     RECT  16.44 51.756 16.608 51.792 ;
     RECT  16.632 51.756 16.8 51.792 ;
     RECT  16.824 51.756 16.992 51.792 ;
     RECT  17.016 51.756 17.184 51.792 ;
     RECT  17.208 51.756 17.376 51.792 ;
     RECT  17.4 51.756 17.616 51.792 ;
     RECT  17.64 51.756 17.808 51.792 ;
     RECT  17.832 51.756 18 51.792 ;
     RECT  18.024 51.756 18.192 51.792 ;
     RECT  18.216 51.756 18.384 51.792 ;
     RECT  18.408 51.756 18.576 51.792 ;
     RECT  18.6 51.756 18.768 51.792 ;
     RECT  18.792 51.756 18.96 51.792 ;
     RECT  18.984 51.756 19.152 51.792 ;
     RECT  19.176 51.756 19.344 51.792 ;
     RECT  19.368 51.756 19.584 51.792 ;
     RECT  19.608 51.756 19.776 51.792 ;
     RECT  19.8 51.756 19.968 51.792 ;
     RECT  19.992 51.756 20.16 51.792 ;
     RECT  20.184 51.756 20.352 51.792 ;
     RECT  20.376 51.756 20.544 51.792 ;
     RECT  20.568 51.756 20.736 51.792 ;
     RECT  20.76 51.756 20.928 51.792 ;
     RECT  20.952 51.756 21.12 51.792 ;
     RECT  21.144 51.756 21.312 51.792 ;
     RECT  21.336 51.756 21.552 51.792 ;
     RECT  21.576 51.756 21.744 51.792 ;
     RECT  21.768 51.756 21.936 51.792 ;
     RECT  21.96 51.756 22.128 51.792 ;
     RECT  22.152 51.756 22.32 51.792 ;
     RECT  22.344 51.756 22.512 51.792 ;
     RECT  22.536 51.756 22.704 51.792 ;
     RECT  22.728 51.756 22.896 51.792 ;
     RECT  22.92 51.756 23.088 51.792 ;
     RECT  23.112 51.756 23.28 51.792 ;
     RECT  23.304 51.756 23.52 51.792 ;
     RECT  23.544 51.756 23.712 51.792 ;
     RECT  23.736 51.756 23.904 51.792 ;
     RECT  23.928 51.756 24.096 51.792 ;
     RECT  24.12 51.756 24.288 51.792 ;
     RECT  24.312 51.756 24.48 51.792 ;
     RECT  24.504 51.756 24.672 51.792 ;
     RECT  24.696 51.756 24.864 51.792 ;
     RECT  24.888 51.756 25.056 51.792 ;
     RECT  25.08 51.756 25.248 51.792 ;
     RECT  25.272 51.756 25.488 51.792 ;
     RECT  25.512 51.756 25.68 51.792 ;
     RECT  25.704 51.756 25.872 51.792 ;
     RECT  25.896 51.756 26.064 51.792 ;
     RECT  26.088 51.756 26.256 51.792 ;
     RECT  26.28 51.756 26.448 51.792 ;
     RECT  26.472 51.756 26.64 51.792 ;
     RECT  26.664 51.756 26.832 51.792 ;
     RECT  26.856 51.756 27.024 51.792 ;
     RECT  27.048 51.756 27.216 51.792 ;
     RECT  27.24 51.756 27.456 51.792 ;
     RECT  27.48 51.756 27.648 51.792 ;
     RECT  27.672 51.756 27.84 51.792 ;
     RECT  27.864 51.756 28.032 51.792 ;
     RECT  28.056 51.756 28.224 51.792 ;
     RECT  28.248 51.756 28.416 51.792 ;
     RECT  28.44 51.756 28.608 51.792 ;
     RECT  28.632 51.756 28.8 51.792 ;
     RECT  28.824 51.756 28.992 51.792 ;
     RECT  29.016 51.756 29.184 51.792 ;
     RECT  29.208 51.756 29.424 51.792 ;
     RECT  29.448 51.756 29.616 51.792 ;
     RECT  29.64 51.756 29.808 51.792 ;
     RECT  29.832 51.756 30 51.792 ;
     RECT  30.024 51.756 30.192 51.792 ;
     RECT  30.216 51.756 30.384 51.792 ;
     RECT  30.408 51.756 30.576 51.792 ;
     RECT  30.6 51.756 30.768 51.792 ;
     RECT  30.792 51.756 30.96 51.792 ;
     RECT  30.984 51.756 31.152 51.792 ;
     RECT  31.176 51.756 31.392 51.792 ;
     RECT  31.416 51.756 31.584 51.792 ;
     RECT  31.608 51.756 31.776 51.792 ;
     RECT  31.8 51.756 31.968 51.792 ;
     RECT  31.992 51.756 32.16 51.792 ;
     RECT  32.184 51.756 32.352 51.792 ;
     RECT  32.376 51.756 32.544 51.792 ;
     RECT  32.568 51.756 32.736 51.792 ;
     RECT  32.76 51.756 32.928 51.792 ;
     RECT  32.952 51.756 33.12 51.792 ;
     RECT  33.144 51.756 33.312 51.792 ;
     RECT  33.336 51.756 33.552 51.792 ;
     RECT  33.576 51.756 33.744 51.792 ;
     RECT  33.768 51.756 33.936 51.792 ;
     RECT  33.96 51.756 34.128 51.792 ;
     RECT  34.152 51.756 34.32 51.792 ;
     RECT  34.344 51.756 34.512 51.792 ;
     RECT  34.536 51.756 34.704 51.792 ;
     RECT  34.728 51.756 34.896 51.792 ;
     RECT  34.92 51.756 35.088 51.792 ;
     RECT  35.112 51.756 35.28 51.792 ;
     RECT  35.304 51.756 35.52 51.792 ;
     RECT  35.544 51.756 35.712 51.792 ;
     RECT  35.736 51.756 35.904 51.792 ;
     RECT  35.928 51.756 36.096 51.792 ;
     RECT  36.12 51.756 36.288 51.792 ;
     RECT  36.312 51.756 36.48 51.792 ;
     RECT  36.504 51.756 36.672 51.792 ;
     RECT  36.696 51.756 36.864 51.792 ;
     RECT  36.888 51.756 37.056 51.792 ;
     RECT  37.08 51.756 37.248 51.792 ;
     RECT  37.272 51.756 37.488 51.792 ;
     RECT  37.512 51.756 37.68 51.792 ;
     RECT  37.704 51.756 37.872 51.792 ;
     RECT  37.896 51.756 38.064 51.792 ;
     RECT  38.088 51.756 38.256 51.792 ;
     RECT  38.28 51.756 38.448 51.792 ;
     RECT  38.472 51.756 38.64 51.792 ;
     RECT  38.664 51.756 38.832 51.792 ;
     RECT  38.856 51.756 39.024 51.792 ;
     RECT  39.048 51.756 39.216 51.792 ;
     RECT  39.24 51.756 39.456 51.792 ;
     RECT  39.48 51.756 39.648 51.792 ;
     RECT  39.672 51.756 39.84 51.792 ;
     RECT  39.864 51.756 40.032 51.792 ;
     RECT  40.056 51.756 40.224 51.792 ;
     RECT  40.248 51.756 40.416 51.792 ;
     RECT  40.44 51.756 40.608 51.792 ;
     RECT  40.632 51.756 40.8 51.792 ;
     RECT  40.824 51.756 40.992 51.792 ;
     RECT  41.016 51.756 41.184 51.792 ;
     RECT  41.208 51.756 41.424 51.792 ;
     RECT  41.448 51.756 41.616 51.792 ;
     RECT  41.64 51.756 41.808 51.792 ;
     RECT  41.832 51.756 42 51.792 ;
     RECT  42.024 51.756 42.192 51.792 ;
     RECT  42.216 51.756 42.384 51.792 ;
     RECT  42.408 51.756 42.576 51.792 ;
     RECT  42.6 51.756 42.768 51.792 ;
     RECT  42.792 51.756 42.96 51.792 ;
     RECT  42.984 51.756 43.152 51.792 ;
     RECT  43.176 51.756 43.392 51.792 ;
     RECT  43.416 51.756 43.584 51.792 ;
     RECT  43.608 51.756 43.776 51.792 ;
     RECT  43.8 51.756 43.968 51.792 ;
     RECT  43.992 51.756 44.16 51.792 ;
     RECT  44.184 51.756 44.352 51.792 ;
     RECT  44.376 51.756 44.544 51.792 ;
     RECT  44.568 51.756 44.736 51.792 ;
     RECT  44.76 51.756 44.928 51.792 ;
     RECT  44.952 51.756 45.12 51.792 ;
     RECT  45.144 51.756 45.36 51.792 ;
     RECT  45.384 51.756 45.552 51.792 ;
     RECT  45.576 51.756 45.744 51.792 ;
     RECT  45.768 51.756 45.936 51.792 ;
     RECT  45.96 51.756 46.128 51.792 ;
     RECT  46.152 51.756 46.32 51.792 ;
     RECT  46.344 51.756 46.512 51.792 ;
     RECT  46.536 51.756 46.704 51.792 ;
     RECT  46.728 51.756 46.896 51.792 ;
     RECT  46.92 51.756 47.088 51.792 ;
     RECT  47.112 51.756 47.328 51.792 ;
     RECT  47.352 51.756 47.52 51.792 ;
     RECT  47.544 51.756 47.712 51.792 ;
     RECT  47.736 51.756 47.904 51.792 ;
     RECT  47.928 51.756 48.096 51.792 ;
     RECT  48.12 51.756 48.288 51.792 ;
     RECT  48.312 51.756 48.48 51.792 ;
     RECT  48.504 51.756 48.672 51.792 ;
     RECT  48.696 51.756 48.864 51.792 ;
     RECT  48.888 51.756 49.056 51.792 ;
     RECT  49.08 51.756 49.248 51.792 ;
     RECT  49.272 51.756 49.488 51.792 ;
     RECT  49.512 51.756 49.68 51.792 ;
     RECT  49.704 51.756 49.872 51.792 ;
     RECT  49.896 51.756 50.064 51.792 ;
     RECT  50.088 51.756 50.256 51.792 ;
     RECT  50.28 51.756 50.448 51.792 ;
     RECT  50.472 51.756 50.64 51.792 ;
     RECT  50.664 51.756 50.832 51.792 ;
     RECT  50.856 51.756 51.024 51.792 ;
     RECT  51.048 51.756 51.216 51.792 ;
     RECT  13.608 18.851 14.592 22.259 ;
     RECT  26.424 18.851 27.552 21.061 ;
     RECT  31.032 18.851 32.352 22.117 ;
     RECT  38.76 18.899 40.032 23.317 ;
     RECT  11.304 18.947 12.288 22.741 ;
     RECT  42.072 21.107 43.2 23.557 ;
     RECT  6.12 21.683 7.632 24.469 ;
     RECT  3.576 21.731 4.752 22.787 ;
     RECT  43.608 22.211 44.736 25.667 ;
     RECT  13.608 22.259 14.64 23.363 ;
     RECT  26.424 22.499 27.552 23.987 ;
     RECT  3.576 22.787 5.232 23.941 ;
     RECT  38.76 23.317 39.84 24.805 ;
     RECT  13.512 23.363 14.64 24.469 ;
     RECT  11.304 23.411 12.288 23.987 ;
     RECT  47.928 23.459 49.008 24.947 ;
     RECT  3.576 23.941 5.136 24.275 ;
     RECT  9.768 23.987 9.864 25.333 ;
     RECT  17.304 23.987 18.6 28.453 ;
     RECT  26.424 23.987 27.744 24.515 ;
     RECT  3.576 24.275 5.328 24.277 ;
     RECT  3.864 24.277 5.328 29.029 ;
     RECT  6.504 24.469 7.632 25.091 ;
     RECT  13.656 24.469 14.64 25.955 ;
     RECT  35.112 24.515 36.24 27.877 ;
     RECT  29.712 24.659 30.816 26.533 ;
     RECT  6.12 25.091 7.632 26.725 ;
     RECT  41.4 25.091 42.624 26.387 ;
     RECT  13.512 25.955 14.64 31.573 ;
     RECT  9.768 26.243 9.864 27.349 ;
     RECT  41.304 26.387 42.624 28.691 ;
     RECT  6.648 26.725 7.632 28.453 ;
     RECT  29.712 27.107 30.816 27.395 ;
     RECT  26.328 27.301 27.744 28.355 ;
     RECT  29.712 27.395 31.008 28.453 ;
     RECT  37.416 27.395 38.496 28.451 ;
     RECT  25.032 27.971 26.304 28.355 ;
     RECT  35.304 28.211 36.432 29.699 ;
     RECT  37.416 28.451 38.736 30.275 ;
     RECT  29.832 28.453 31.008 30.757 ;
     RECT  3.864 29.029 4.992 42.709 ;
     RECT  41.016 29.123 41.208 30.181 ;
     RECT  20.808 29.651 21.936 30.131 ;
     RECT  23.016 29.651 24 30.275 ;
     RECT  27.864 29.699 28.992 45.589 ;
     RECT  25.032 30.181 26.448 30.853 ;
     RECT  26.472 30.181 27.744 31.861 ;
     RECT  17.016 30.275 18.192 46.117 ;
     RECT  22.152 30.275 24 31.285 ;
     RECT  38.64 30.275 38.736 30.805 ;
     RECT  25.032 30.853 26.112 34.259 ;
     RECT  41.544 30.853 42.912 33.011 ;
     RECT  29.832 30.995 31.008 33.637 ;
     RECT  31.8 30.995 32.928 46.117 ;
     RECT  10.728 30.997 11.712 45.589 ;
     RECT  11.736 30.997 13.056 32.437 ;
     RECT  13.512 31.573 14.496 45.541 ;
     RECT  22.152 32.483 23.28 46.117 ;
     RECT  41.016 33.011 42.912 33.061 ;
     RECT  41.016 33.061 42 51.637 ;
     RECT  38.088 33.637 39.216 46.693 ;
     RECT  24.936 34.259 26.448 48.997 ;
     RECT  19.176 34.835 20.352 47.269 ;
     RECT  47.928 46.117 49.2 46.693 ;
     RECT  5.544 46.211 6.576 47.363 ;
     RECT  46.152 47.269 47.328 48.997 ;
     RECT  5.208 47.363 6.576 48.997 ;
     RECT  30.6 47.363 31.776 49.525 ;
     RECT  42.984 47.363 43.416 47.845 ;
     RECT  42.984 47.845 44.352 48.421 ;
     RECT  44.376 47.845 45.6 49.703 ;
     RECT  0.888 48.085 2.304 48.133 ;
     RECT  35.304 48.421 36.48 50.677 ;
     RECT  36.504 48.421 37.68 48.469 ;
     RECT  5.208 48.997 6.192 49.477 ;
     RECT  20.952 49.381 22.128 49.573 ;
     RECT  20.952 49.573 21.936 50.101 ;
     RECT  49.704 49.573 50.832 50.149 ;
     RECT  44.376 49.703 45.744 50.725 ;
  END
END qfd_c_stn516
END LIBRARY
